VERSION 5.7 ;
  NOWIREEXTENSIONATPIN ON ;
  DIVIDERCHAR "/" ;
  BUSBITCHARS "[]" ;
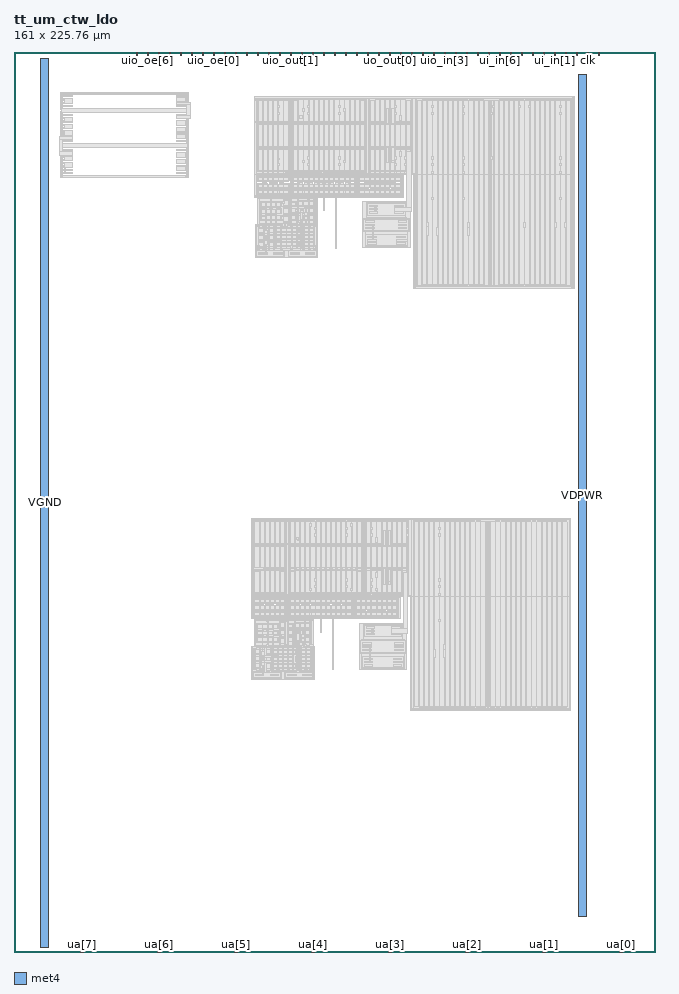
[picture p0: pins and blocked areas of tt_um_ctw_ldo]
MACRO tt_um_ctw_ldo
  CLASS BLOCK ;
  FOREIGN tt_um_ctw_ldo ;
  ORIGIN 0.000 0.000 ;
  SIZE 161.000 BY 225.760 ;
  PIN clk
    DIRECTION INPUT ;
    USE SIGNAL ;
    PORT
      LAYER met4 ;
        RECT 143.830 224.760 144.130 225.760 ;
    END
  END clk
  PIN ena
    DIRECTION INPUT ;
    USE SIGNAL ;
    PORT
      LAYER met4 ;
        RECT 146.590 224.760 146.890 225.760 ;
    END
  END ena
  PIN rst_n
    DIRECTION INPUT ;
    USE SIGNAL ;
    PORT
      LAYER met4 ;
        RECT 141.070 224.760 141.370 225.760 ;
    END
  END rst_n
  PIN ua[0]
    DIRECTION INOUT ;
    USE SIGNAL ;
    ANTENNAGATEAREA 46.000000 ;
    ANTENNADIFFAREA 186.759995 ;
    PORT
      LAYER met4 ;
        RECT 151.810 0.000 152.710 1.000 ;
    END
  END ua[0]
  PIN ua[1]
    DIRECTION INOUT ;
    USE SIGNAL ;
    ANTENNAGATEAREA 46.000000 ;
    ANTENNADIFFAREA 186.759995 ;
    PORT
      LAYER met4 ;
        RECT 132.490 0.000 133.390 1.000 ;
    END
  END ua[1]
  PIN ua[2]
    DIRECTION INOUT ;
    USE SIGNAL ;
    ANTENNAGATEAREA 886.259949 ;
    ANTENNADIFFAREA 831.391174 ;
    PORT
      LAYER met4 ;
        RECT 113.170 0.000 114.070 1.000 ;
    END
  END ua[2]
  PIN ua[3]
    DIRECTION INOUT ;
    USE SIGNAL ;
    ANTENNAGATEAREA 2.000000 ;
    PORT
      LAYER met4 ;
        RECT 93.850 0.000 94.750 1.000 ;
    END
  END ua[3]
  PIN ua[4]
    DIRECTION INOUT ;
    USE SIGNAL ;
    PORT
      LAYER met4 ;
        RECT 74.530 0.000 75.430 1.000 ;
    END
  END ua[4]
  PIN ua[5]
    DIRECTION INOUT ;
    USE SIGNAL ;
    PORT
      LAYER met4 ;
        RECT 55.210 0.000 56.110 1.000 ;
    END
  END ua[5]
  PIN ua[6]
    DIRECTION INOUT ;
    USE SIGNAL ;
    PORT
      LAYER met4 ;
        RECT 35.890 0.000 36.790 1.000 ;
    END
  END ua[6]
  PIN ua[7]
    DIRECTION INOUT ;
    USE SIGNAL ;
    PORT
      LAYER met4 ;
        RECT 16.570 0.000 17.470 1.000 ;
    END
  END ua[7]
  PIN ui_in[0]
    DIRECTION INPUT ;
    USE SIGNAL ;
    PORT
      LAYER met4 ;
        RECT 138.310 224.760 138.610 225.760 ;
    END
  END ui_in[0]
  PIN ui_in[1]
    DIRECTION INPUT ;
    USE SIGNAL ;
    PORT
      LAYER met4 ;
        RECT 135.550 224.760 135.850 225.760 ;
    END
  END ui_in[1]
  PIN ui_in[2]
    DIRECTION INPUT ;
    USE SIGNAL ;
    PORT
      LAYER met4 ;
        RECT 132.790 224.760 133.090 225.760 ;
    END
  END ui_in[2]
  PIN ui_in[3]
    DIRECTION INPUT ;
    USE SIGNAL ;
    PORT
      LAYER met4 ;
        RECT 130.030 224.760 130.330 225.760 ;
    END
  END ui_in[3]
  PIN ui_in[4]
    DIRECTION INPUT ;
    USE SIGNAL ;
    PORT
      LAYER met4 ;
        RECT 127.270 224.760 127.570 225.760 ;
    END
  END ui_in[4]
  PIN ui_in[5]
    DIRECTION INPUT ;
    USE SIGNAL ;
    PORT
      LAYER met4 ;
        RECT 124.510 224.760 124.810 225.760 ;
    END
  END ui_in[5]
  PIN ui_in[6]
    DIRECTION INPUT ;
    USE SIGNAL ;
    PORT
      LAYER met4 ;
        RECT 121.750 224.760 122.050 225.760 ;
    END
  END ui_in[6]
  PIN ui_in[7]
    DIRECTION INPUT ;
    USE SIGNAL ;
    PORT
      LAYER met4 ;
        RECT 118.990 224.760 119.290 225.760 ;
    END
  END ui_in[7]
  PIN uio_in[0]
    DIRECTION INPUT ;
    USE SIGNAL ;
    PORT
      LAYER met4 ;
        RECT 116.230 224.760 116.530 225.760 ;
    END
  END uio_in[0]
  PIN uio_in[1]
    DIRECTION INPUT ;
    USE SIGNAL ;
    PORT
      LAYER met4 ;
        RECT 113.470 224.760 113.770 225.760 ;
    END
  END uio_in[1]
  PIN uio_in[2]
    DIRECTION INPUT ;
    USE SIGNAL ;
    PORT
      LAYER met4 ;
        RECT 110.710 224.760 111.010 225.760 ;
    END
  END uio_in[2]
  PIN uio_in[3]
    DIRECTION INPUT ;
    USE SIGNAL ;
    PORT
      LAYER met4 ;
        RECT 107.950 224.760 108.250 225.760 ;
    END
  END uio_in[3]
  PIN uio_in[4]
    DIRECTION INPUT ;
    USE SIGNAL ;
    PORT
      LAYER met4 ;
        RECT 105.190 224.760 105.490 225.760 ;
    END
  END uio_in[4]
  PIN uio_in[5]
    DIRECTION INPUT ;
    USE SIGNAL ;
    PORT
      LAYER met4 ;
        RECT 102.430 224.760 102.730 225.760 ;
    END
  END uio_in[5]
  PIN uio_in[6]
    DIRECTION INPUT ;
    USE SIGNAL ;
    PORT
      LAYER met4 ;
        RECT 99.670 224.760 99.970 225.760 ;
    END
  END uio_in[6]
  PIN uio_in[7]
    DIRECTION INPUT ;
    USE SIGNAL ;
    PORT
      LAYER met4 ;
        RECT 96.910 224.760 97.210 225.760 ;
    END
  END uio_in[7]
  PIN uio_oe[0]
    DIRECTION OUTPUT ;
    USE SIGNAL ;
    PORT
      LAYER met4 ;
        RECT 49.990 224.760 50.290 225.760 ;
    END
  END uio_oe[0]
  PIN uio_oe[1]
    DIRECTION OUTPUT ;
    USE SIGNAL ;
    PORT
      LAYER met4 ;
        RECT 47.230 224.760 47.530 225.760 ;
    END
  END uio_oe[1]
  PIN uio_oe[2]
    DIRECTION OUTPUT ;
    USE SIGNAL ;
    PORT
      LAYER met4 ;
        RECT 44.470 224.760 44.770 225.760 ;
    END
  END uio_oe[2]
  PIN uio_oe[3]
    DIRECTION OUTPUT ;
    USE SIGNAL ;
    PORT
      LAYER met4 ;
        RECT 41.710 224.760 42.010 225.760 ;
    END
  END uio_oe[3]
  PIN uio_oe[4]
    DIRECTION OUTPUT ;
    USE SIGNAL ;
    PORT
      LAYER met4 ;
        RECT 38.950 224.760 39.250 225.760 ;
    END
  END uio_oe[4]
  PIN uio_oe[5]
    DIRECTION OUTPUT ;
    USE SIGNAL ;
    PORT
      LAYER met4 ;
        RECT 36.190 224.760 36.490 225.760 ;
    END
  END uio_oe[5]
  PIN uio_oe[6]
    DIRECTION OUTPUT ;
    USE SIGNAL ;
    PORT
      LAYER met4 ;
        RECT 33.430 224.760 33.730 225.760 ;
    END
  END uio_oe[6]
  PIN uio_oe[7]
    DIRECTION OUTPUT ;
    USE SIGNAL ;
    PORT
      LAYER met4 ;
        RECT 30.670 224.760 30.970 225.760 ;
    END
  END uio_oe[7]
  PIN uio_out[0]
    DIRECTION OUTPUT ;
    USE SIGNAL ;
    PORT
      LAYER met4 ;
        RECT 72.070 224.760 72.370 225.760 ;
    END
  END uio_out[0]
  PIN uio_out[1]
    DIRECTION OUTPUT ;
    USE SIGNAL ;
    ANTENNAGATEAREA 80.379997 ;
    ANTENNADIFFAREA 155.779800 ;
    PORT
      LAYER met4 ;
        RECT 69.310 224.760 69.610 225.760 ;
    END
  END uio_out[1]
  PIN uio_out[2]
    DIRECTION OUTPUT ;
    USE SIGNAL ;
    PORT
      LAYER met4 ;
        RECT 66.550 224.760 66.850 225.760 ;
    END
  END uio_out[2]
  PIN uio_out[3]
    DIRECTION OUTPUT ;
    USE SIGNAL ;
    PORT
      LAYER met4 ;
        RECT 63.790 224.760 64.090 225.760 ;
    END
  END uio_out[3]
  PIN uio_out[4]
    DIRECTION OUTPUT ;
    USE SIGNAL ;
    PORT
      LAYER met4 ;
        RECT 61.030 224.760 61.330 225.760 ;
    END
  END uio_out[4]
  PIN uio_out[5]
    DIRECTION OUTPUT ;
    USE SIGNAL ;
    PORT
      LAYER met4 ;
        RECT 58.270 224.760 58.570 225.760 ;
    END
  END uio_out[5]
  PIN uio_out[6]
    DIRECTION OUTPUT ;
    USE SIGNAL ;
    PORT
      LAYER met4 ;
        RECT 55.510 224.760 55.810 225.760 ;
    END
  END uio_out[6]
  PIN uio_out[7]
    DIRECTION OUTPUT ;
    USE SIGNAL ;
    PORT
      LAYER met4 ;
        RECT 52.750 224.760 53.050 225.760 ;
    END
  END uio_out[7]
  PIN uo_out[0]
    DIRECTION OUTPUT ;
    USE SIGNAL ;
    PORT
      LAYER met4 ;
        RECT 94.150 224.760 94.450 225.760 ;
    END
  END uo_out[0]
  PIN uo_out[1]
    DIRECTION OUTPUT ;
    USE SIGNAL ;
    PORT
      LAYER met4 ;
        RECT 91.390 224.760 91.690 225.760 ;
    END
  END uo_out[1]
  PIN uo_out[2]
    DIRECTION OUTPUT ;
    USE SIGNAL ;
    PORT
      LAYER met4 ;
        RECT 88.630 224.760 88.930 225.760 ;
    END
  END uo_out[2]
  PIN uo_out[3]
    DIRECTION OUTPUT ;
    USE SIGNAL ;
    PORT
      LAYER met4 ;
        RECT 85.870 224.760 86.170 225.760 ;
    END
  END uo_out[3]
  PIN uo_out[4]
    DIRECTION OUTPUT ;
    USE SIGNAL ;
    PORT
      LAYER met4 ;
        RECT 83.110 224.760 83.410 225.760 ;
    END
  END uo_out[4]
  PIN uo_out[5]
    DIRECTION OUTPUT ;
    USE SIGNAL ;
    PORT
      LAYER met4 ;
        RECT 80.350 224.760 80.650 225.760 ;
    END
  END uo_out[5]
  PIN uo_out[6]
    DIRECTION OUTPUT ;
    USE SIGNAL ;
    PORT
      LAYER met4 ;
        RECT 77.590 224.760 77.890 225.760 ;
    END
  END uo_out[6]
  PIN uo_out[7]
    DIRECTION OUTPUT ;
    USE SIGNAL ;
    PORT
      LAYER met4 ;
        RECT 74.830 224.760 75.130 225.760 ;
    END
  END uo_out[7]
  PIN VDPWR
    DIRECTION INOUT ;
    USE POWER ;
    PORT
      LAYER met4 ;
        RECT 141.725 8.930 143.725 220.105 ;
    END
  END VDPWR
  PIN VGND
    DIRECTION INOUT ;
    USE GROUND ;
    PORT
      LAYER met4 ;
        RECT 6.770 1.140 8.770 224.210 ;
    END
  END VGND
  OBS
      LAYER pwell ;
        RECT 11.760 215.220 43.730 215.650 ;
        RECT 11.760 211.680 12.190 215.220 ;
        RECT 43.300 211.680 43.730 215.220 ;
        RECT 11.760 211.250 43.730 211.680 ;
        RECT 11.760 210.530 43.730 210.960 ;
        RECT 11.760 202.840 12.190 210.530 ;
        RECT 43.300 202.840 43.730 210.530 ;
        RECT 11.760 202.410 43.730 202.840 ;
        RECT 11.760 201.690 43.730 202.120 ;
        RECT 11.760 194.830 12.190 201.690 ;
        RECT 43.300 194.830 43.730 201.690 ;
      LAYER nwell ;
        RECT 60.320 195.050 140.500 214.600 ;
      LAYER pwell ;
        RECT 11.760 194.400 43.730 194.830 ;
        RECT 60.380 194.620 97.740 195.050 ;
        RECT 60.380 189.800 60.810 194.620 ;
        RECT 60.880 193.420 69.170 194.180 ;
        RECT 60.880 191.830 69.170 192.590 ;
        RECT 60.880 190.240 69.170 191.000 ;
        RECT 69.260 189.800 69.690 194.620 ;
        RECT 69.750 193.420 85.780 194.180 ;
        RECT 69.750 191.830 85.780 192.590 ;
        RECT 69.750 190.240 85.780 191.000 ;
        RECT 85.870 189.800 86.300 194.620 ;
        RECT 86.350 193.420 97.220 194.180 ;
        RECT 86.350 191.830 97.220 192.590 ;
        RECT 86.350 190.240 97.220 191.000 ;
        RECT 97.310 189.800 97.740 194.620 ;
        RECT 60.380 189.370 97.740 189.800 ;
      LAYER nwell ;
        RECT 61.055 182.415 76.015 189.370 ;
      LAYER pwell ;
        RECT 60.500 174.220 76.195 182.415 ;
        RECT 87.440 176.680 99.390 188.175 ;
        RECT 87.900 176.670 98.970 176.680 ;
      LAYER nwell ;
        RECT 100.280 166.410 140.500 195.050 ;
        RECT 59.480 89.255 139.660 108.805 ;
      LAYER pwell ;
        RECT 59.540 88.825 96.900 89.255 ;
        RECT 59.540 84.005 59.970 88.825 ;
        RECT 60.040 87.625 68.330 88.385 ;
        RECT 60.040 86.035 68.330 86.795 ;
        RECT 60.040 84.445 68.330 85.205 ;
        RECT 68.420 84.005 68.850 88.825 ;
        RECT 68.910 87.625 84.940 88.385 ;
        RECT 68.910 86.035 84.940 86.795 ;
        RECT 68.910 84.445 84.940 85.205 ;
        RECT 85.030 84.005 85.460 88.825 ;
        RECT 85.510 87.625 96.380 88.385 ;
        RECT 85.510 86.035 96.380 86.795 ;
        RECT 85.510 84.445 96.380 85.205 ;
        RECT 96.470 84.005 96.900 88.825 ;
        RECT 59.540 83.575 96.900 84.005 ;
      LAYER nwell ;
        RECT 60.215 76.620 75.175 83.575 ;
      LAYER pwell ;
        RECT 59.660 68.425 75.355 76.620 ;
        RECT 86.600 70.885 98.550 82.380 ;
        RECT 87.060 70.875 98.130 70.885 ;
      LAYER nwell ;
        RECT 99.440 60.615 139.660 89.255 ;
      LAYER li1 ;
        RECT 12.530 215.520 42.965 215.525 ;
        RECT 11.890 215.350 43.600 215.520 ;
        RECT 11.890 211.550 12.060 215.350 ;
        RECT 12.540 214.520 14.700 214.870 ;
        RECT 40.790 214.520 42.950 214.870 ;
        RECT 12.540 213.690 14.700 214.040 ;
        RECT 40.790 213.690 42.950 214.040 ;
        RECT 12.540 212.860 14.700 213.210 ;
        RECT 40.790 212.860 42.950 213.210 ;
        RECT 12.540 212.030 14.700 212.380 ;
        RECT 40.790 212.030 42.950 212.380 ;
        RECT 43.430 211.550 43.600 215.350 ;
        RECT 11.890 210.660 43.600 211.550 ;
        RECT 11.890 202.710 12.060 210.660 ;
        RECT 12.540 209.830 14.700 210.180 ;
        RECT 40.790 209.830 42.950 210.180 ;
        RECT 12.540 209.000 14.700 209.350 ;
        RECT 40.790 209.000 42.950 209.350 ;
        RECT 12.540 208.170 14.700 208.520 ;
        RECT 40.790 208.170 42.950 208.520 ;
        RECT 12.540 207.340 14.700 207.690 ;
        RECT 40.790 207.340 42.950 207.690 ;
        RECT 12.540 206.510 14.700 206.860 ;
        RECT 40.790 206.510 42.950 206.860 ;
        RECT 12.540 205.680 14.700 206.030 ;
        RECT 40.790 205.680 42.950 206.030 ;
        RECT 12.540 204.850 14.700 205.200 ;
        RECT 40.790 204.850 42.950 205.200 ;
        RECT 12.540 204.020 14.700 204.370 ;
        RECT 40.790 204.020 42.950 204.370 ;
        RECT 12.540 203.190 14.700 203.540 ;
        RECT 40.790 203.190 42.950 203.540 ;
        RECT 43.430 202.710 43.600 210.660 ;
        RECT 11.890 201.820 43.600 202.710 ;
        RECT 11.890 194.700 12.060 201.820 ;
        RECT 12.540 200.990 14.700 201.340 ;
        RECT 40.790 200.990 42.950 201.340 ;
        RECT 12.540 200.160 14.700 200.510 ;
        RECT 40.790 200.160 42.950 200.510 ;
        RECT 12.540 199.330 14.700 199.680 ;
        RECT 40.790 199.330 42.950 199.680 ;
        RECT 12.540 198.500 14.700 198.850 ;
        RECT 40.790 198.500 42.950 198.850 ;
        RECT 12.540 197.670 14.700 198.020 ;
        RECT 40.790 197.670 42.950 198.020 ;
        RECT 12.540 196.840 14.700 197.190 ;
        RECT 40.790 196.840 42.950 197.190 ;
        RECT 12.540 196.010 14.700 196.360 ;
        RECT 40.790 196.010 42.950 196.360 ;
        RECT 12.540 195.180 14.700 195.530 ;
        RECT 40.790 195.180 42.950 195.530 ;
        RECT 43.430 194.700 43.600 201.820 ;
        RECT 60.500 214.250 100.190 214.420 ;
        RECT 60.500 201.550 60.670 214.250 ;
        RECT 61.380 213.740 62.220 213.910 ;
        RECT 62.670 213.740 63.510 213.910 ;
        RECT 63.880 213.740 66.170 213.910 ;
        RECT 66.460 213.740 67.460 213.910 ;
        RECT 67.750 213.740 68.750 213.910 ;
        RECT 61.070 208.485 61.240 213.525 ;
        RECT 62.360 208.485 62.530 213.525 ;
        RECT 63.650 208.485 63.820 213.525 ;
        RECT 64.940 208.270 65.110 213.740 ;
        RECT 66.230 208.485 66.400 213.525 ;
        RECT 67.520 208.485 67.690 213.525 ;
        RECT 68.810 208.485 68.980 213.525 ;
        RECT 61.380 208.100 62.220 208.270 ;
        RECT 62.670 208.100 63.510 208.270 ;
        RECT 63.880 208.100 66.170 208.270 ;
        RECT 66.460 208.100 67.460 208.270 ;
        RECT 67.750 208.100 68.750 208.270 ;
        RECT 61.300 207.560 62.300 207.730 ;
        RECT 62.695 207.560 63.485 207.730 ;
        RECT 63.985 207.560 64.775 207.730 ;
        RECT 65.275 207.560 66.065 207.730 ;
        RECT 66.565 207.560 67.355 207.730 ;
        RECT 67.750 207.560 68.750 207.730 ;
        RECT 61.070 202.305 61.240 207.345 ;
        RECT 62.360 202.305 62.530 207.345 ;
        RECT 63.650 202.305 63.820 207.345 ;
        RECT 64.940 202.305 65.110 207.345 ;
        RECT 66.230 202.305 66.400 207.345 ;
        RECT 67.520 202.305 67.690 207.345 ;
        RECT 68.810 202.305 68.980 207.345 ;
        RECT 61.300 201.920 62.300 202.090 ;
        RECT 62.695 201.920 63.485 202.090 ;
        RECT 63.985 201.920 64.775 202.090 ;
        RECT 65.275 201.920 66.065 202.090 ;
        RECT 66.565 201.920 67.355 202.090 ;
        RECT 67.750 201.920 68.750 202.090 ;
        RECT 69.380 201.550 69.550 214.250 ;
        RECT 69.950 213.910 70.120 214.250 ;
        RECT 72.530 213.910 72.700 214.250 ;
        RECT 73.820 213.910 73.990 214.250 ;
        RECT 75.110 213.910 75.280 214.250 ;
        RECT 76.400 213.910 76.570 214.250 ;
        RECT 77.690 213.910 77.860 214.250 ;
        RECT 78.980 213.910 79.150 214.250 ;
        RECT 80.270 213.910 80.440 214.250 ;
        RECT 81.560 213.910 81.730 214.250 ;
        RECT 82.850 213.910 83.020 214.250 ;
        RECT 84.140 213.910 84.310 214.250 ;
        RECT 85.430 213.910 85.600 214.250 ;
        RECT 86.720 213.910 86.890 214.250 ;
        RECT 88.010 213.910 88.180 214.250 ;
        RECT 69.950 213.740 88.180 213.910 ;
        RECT 69.950 208.270 70.120 213.740 ;
        RECT 71.240 208.485 71.410 213.525 ;
        RECT 72.530 208.270 72.700 213.740 ;
        RECT 73.820 208.270 73.990 213.740 ;
        RECT 75.110 208.270 75.280 213.740 ;
        RECT 76.400 208.270 76.570 213.740 ;
        RECT 77.690 208.270 77.860 213.740 ;
        RECT 78.980 208.270 79.150 213.740 ;
        RECT 80.270 208.270 80.440 213.740 ;
        RECT 81.560 208.270 81.730 213.740 ;
        RECT 82.850 208.270 83.020 213.740 ;
        RECT 84.140 208.270 84.310 213.740 ;
        RECT 85.430 208.270 85.600 213.740 ;
        RECT 86.720 208.270 86.890 213.740 ;
        RECT 88.010 208.270 88.180 213.740 ;
        RECT 69.950 208.100 88.180 208.270 ;
        RECT 70.180 207.560 71.180 207.730 ;
        RECT 71.575 207.560 72.365 207.730 ;
        RECT 72.865 207.560 73.655 207.730 ;
        RECT 74.155 207.560 74.945 207.730 ;
        RECT 75.445 207.560 76.235 207.730 ;
        RECT 76.735 207.560 77.525 207.730 ;
        RECT 78.025 207.560 78.815 207.730 ;
        RECT 79.315 207.560 80.105 207.730 ;
        RECT 80.605 207.560 81.395 207.730 ;
        RECT 81.895 207.560 82.685 207.730 ;
        RECT 83.185 207.560 83.975 207.730 ;
        RECT 84.475 207.560 85.265 207.730 ;
        RECT 85.765 207.560 86.555 207.730 ;
        RECT 86.950 207.560 87.950 207.730 ;
        RECT 69.950 202.305 70.120 207.345 ;
        RECT 71.240 202.305 71.410 207.345 ;
        RECT 72.530 202.305 72.700 207.345 ;
        RECT 73.820 202.305 73.990 207.345 ;
        RECT 75.110 202.305 75.280 207.345 ;
        RECT 76.400 202.305 76.570 207.345 ;
        RECT 77.690 202.305 77.860 207.345 ;
        RECT 78.980 202.305 79.150 207.345 ;
        RECT 80.270 202.305 80.440 207.345 ;
        RECT 81.560 202.305 81.730 207.345 ;
        RECT 82.850 202.305 83.020 207.345 ;
        RECT 84.140 202.305 84.310 207.345 ;
        RECT 85.430 202.305 85.600 207.345 ;
        RECT 86.720 202.305 86.890 207.345 ;
        RECT 88.010 202.305 88.180 207.345 ;
        RECT 70.180 201.920 71.180 202.090 ;
        RECT 71.575 201.920 72.365 202.090 ;
        RECT 72.865 201.920 73.655 202.090 ;
        RECT 74.155 201.920 74.945 202.090 ;
        RECT 75.445 201.920 76.235 202.090 ;
        RECT 76.735 201.920 77.525 202.090 ;
        RECT 78.025 201.920 78.815 202.090 ;
        RECT 79.315 201.920 80.105 202.090 ;
        RECT 80.605 201.920 81.395 202.090 ;
        RECT 81.895 201.920 82.685 202.090 ;
        RECT 83.185 201.920 83.975 202.090 ;
        RECT 84.475 201.920 85.265 202.090 ;
        RECT 85.765 201.920 86.555 202.090 ;
        RECT 86.950 201.920 87.950 202.090 ;
        RECT 88.560 201.550 88.750 214.250 ;
        RECT 89.130 213.910 89.300 214.250 ;
        RECT 90.420 213.910 90.590 214.250 ;
        RECT 91.710 213.910 91.880 214.250 ;
        RECT 93.000 213.910 93.170 214.250 ;
        RECT 94.290 213.910 94.460 214.250 ;
        RECT 95.580 213.910 95.750 214.250 ;
        RECT 96.870 213.910 97.040 214.250 ;
        RECT 98.160 213.910 98.330 214.250 ;
        RECT 99.450 213.910 99.620 214.250 ;
        RECT 89.130 213.740 99.620 213.910 ;
        RECT 89.130 208.270 89.300 213.740 ;
        RECT 90.420 208.270 90.590 213.740 ;
        RECT 91.710 208.270 91.880 213.740 ;
        RECT 93.000 208.270 93.170 213.740 ;
        RECT 94.290 208.270 94.460 213.740 ;
        RECT 95.580 208.270 95.750 213.740 ;
        RECT 96.870 208.270 97.040 213.740 ;
        RECT 98.160 208.270 98.330 213.740 ;
        RECT 99.450 208.270 99.620 213.740 ;
        RECT 89.130 208.100 99.620 208.270 ;
        RECT 89.360 207.560 90.360 207.730 ;
        RECT 90.755 207.560 91.545 207.730 ;
        RECT 92.045 207.560 92.835 207.730 ;
        RECT 93.335 207.560 94.125 207.730 ;
        RECT 94.625 207.560 95.415 207.730 ;
        RECT 95.915 207.560 96.705 207.730 ;
        RECT 97.205 207.560 97.995 207.730 ;
        RECT 98.390 207.560 99.390 207.730 ;
        RECT 89.130 202.305 89.300 207.345 ;
        RECT 90.420 202.305 90.590 207.345 ;
        RECT 91.710 202.305 91.880 207.345 ;
        RECT 93.000 202.305 93.170 207.345 ;
        RECT 94.290 202.305 94.460 207.345 ;
        RECT 95.580 202.305 95.750 207.345 ;
        RECT 96.870 202.305 97.040 207.345 ;
        RECT 98.160 202.305 98.330 207.345 ;
        RECT 99.450 202.305 99.620 207.345 ;
        RECT 89.360 201.920 90.360 202.090 ;
        RECT 90.755 201.920 91.545 202.090 ;
        RECT 92.045 201.920 92.835 202.090 ;
        RECT 93.335 201.920 94.125 202.090 ;
        RECT 94.625 201.920 95.415 202.090 ;
        RECT 95.915 201.920 96.705 202.090 ;
        RECT 97.205 201.920 97.995 202.090 ;
        RECT 98.390 201.920 99.390 202.090 ;
        RECT 100.020 201.550 100.190 214.250 ;
        RECT 60.500 201.380 100.190 201.550 ;
        RECT 60.500 195.910 60.670 201.380 ;
        RECT 61.070 196.125 61.240 201.165 ;
        RECT 62.360 195.910 62.530 201.380 ;
        RECT 63.650 195.910 63.820 201.380 ;
        RECT 64.940 195.910 65.110 201.380 ;
        RECT 66.230 195.910 66.400 201.380 ;
        RECT 67.520 195.910 67.690 201.380 ;
        RECT 68.810 196.125 68.980 201.165 ;
        RECT 69.380 195.910 69.550 201.380 ;
        RECT 69.950 195.910 70.120 201.380 ;
        RECT 71.240 195.910 71.410 201.380 ;
        RECT 72.530 195.910 72.700 201.380 ;
        RECT 73.820 195.910 73.990 201.380 ;
        RECT 75.110 195.910 75.280 201.380 ;
        RECT 76.400 195.910 76.570 201.380 ;
        RECT 77.690 195.910 77.860 201.380 ;
        RECT 78.980 195.910 79.150 201.380 ;
        RECT 80.270 195.910 80.440 201.380 ;
        RECT 81.560 195.910 81.730 201.380 ;
        RECT 82.850 195.910 83.020 201.380 ;
        RECT 84.140 195.910 84.310 201.380 ;
        RECT 85.430 195.910 85.600 201.380 ;
        RECT 86.720 195.910 86.890 201.380 ;
        RECT 88.010 195.910 88.180 201.380 ;
        RECT 88.560 195.910 88.750 201.380 ;
        RECT 89.130 195.910 89.300 201.380 ;
        RECT 90.420 195.910 90.590 201.380 ;
        RECT 91.710 195.910 91.880 201.380 ;
        RECT 93.000 195.910 93.170 201.380 ;
        RECT 94.290 195.910 94.460 201.380 ;
        RECT 95.580 195.910 95.750 201.380 ;
        RECT 96.870 195.910 97.040 201.380 ;
        RECT 98.160 195.910 98.330 201.380 ;
        RECT 99.450 195.910 99.620 201.380 ;
        RECT 100.020 195.910 100.190 201.380 ;
        RECT 100.460 214.250 140.320 214.420 ;
        RECT 100.460 197.840 100.630 214.250 ;
        RECT 101.260 213.740 102.260 213.910 ;
        RECT 102.550 213.740 103.550 213.910 ;
        RECT 103.840 213.740 104.840 213.910 ;
        RECT 105.130 213.740 106.130 213.910 ;
        RECT 106.420 213.740 107.420 213.910 ;
        RECT 107.710 213.740 108.710 213.910 ;
        RECT 109.000 213.740 110.000 213.910 ;
        RECT 110.290 213.740 111.290 213.910 ;
        RECT 111.580 213.740 112.580 213.910 ;
        RECT 112.870 213.740 113.870 213.910 ;
        RECT 114.160 213.740 115.160 213.910 ;
        RECT 115.450 213.740 116.450 213.910 ;
        RECT 116.740 213.740 117.740 213.910 ;
        RECT 118.030 213.740 119.030 213.910 ;
        RECT 100.455 197.200 100.630 197.840 ;
        RECT 60.500 195.740 100.190 195.910 ;
        RECT 60.500 195.400 60.670 195.740 ;
        RECT 69.380 195.400 69.550 195.740 ;
        RECT 69.950 195.400 70.120 195.740 ;
        RECT 71.240 195.400 71.410 195.740 ;
        RECT 72.530 195.400 72.700 195.740 ;
        RECT 73.820 195.400 73.990 195.740 ;
        RECT 75.110 195.400 75.280 195.740 ;
        RECT 76.400 195.400 76.570 195.740 ;
        RECT 77.690 195.400 77.860 195.740 ;
        RECT 78.980 195.400 79.150 195.740 ;
        RECT 80.270 195.400 80.440 195.740 ;
        RECT 81.560 195.400 81.730 195.740 ;
        RECT 82.850 195.400 83.020 195.740 ;
        RECT 84.140 195.400 84.310 195.740 ;
        RECT 85.430 195.400 85.600 195.740 ;
        RECT 86.720 195.400 86.890 195.740 ;
        RECT 88.010 195.400 88.180 195.740 ;
        RECT 88.560 195.400 88.750 195.740 ;
        RECT 89.130 195.400 89.300 195.740 ;
        RECT 90.420 195.400 90.590 195.740 ;
        RECT 91.710 195.400 91.880 195.740 ;
        RECT 93.000 195.400 93.170 195.740 ;
        RECT 94.290 195.400 94.460 195.740 ;
        RECT 95.580 195.400 95.750 195.740 ;
        RECT 96.870 195.400 97.040 195.740 ;
        RECT 98.160 195.400 98.330 195.740 ;
        RECT 99.450 195.400 99.620 195.740 ;
        RECT 100.020 195.400 100.190 195.740 ;
        RECT 60.500 195.230 100.190 195.400 ;
        RECT 11.890 194.530 43.600 194.700 ;
        RECT 60.510 194.750 97.610 194.920 ;
        RECT 60.510 189.670 60.680 194.750 ;
        RECT 61.070 194.410 61.240 194.750 ;
        RECT 62.360 194.410 62.530 194.750 ;
        RECT 63.650 194.410 63.820 194.750 ;
        RECT 64.940 194.410 65.110 194.750 ;
        RECT 66.230 194.410 66.400 194.750 ;
        RECT 67.520 194.410 67.690 194.750 ;
        RECT 68.810 194.410 68.980 194.750 ;
        RECT 61.070 194.240 68.980 194.410 ;
        RECT 61.070 193.360 61.240 194.240 ;
        RECT 62.360 193.360 62.530 194.240 ;
        RECT 63.650 193.360 63.820 194.240 ;
        RECT 64.940 193.360 65.110 194.240 ;
        RECT 66.230 193.360 66.400 194.240 ;
        RECT 67.520 193.360 67.690 194.240 ;
        RECT 68.810 193.360 68.980 194.240 ;
        RECT 61.070 193.190 68.980 193.360 ;
        RECT 61.405 192.650 62.195 192.820 ;
        RECT 62.695 192.650 63.485 192.820 ;
        RECT 63.985 192.650 64.775 192.820 ;
        RECT 65.275 192.650 66.065 192.820 ;
        RECT 66.565 192.650 67.355 192.820 ;
        RECT 67.855 192.650 68.645 192.820 ;
        RECT 61.070 191.940 61.240 192.480 ;
        RECT 62.360 191.940 62.530 192.480 ;
        RECT 63.650 191.940 63.820 192.480 ;
        RECT 64.940 191.940 65.110 192.480 ;
        RECT 66.230 191.940 66.400 192.480 ;
        RECT 67.520 191.940 67.690 192.480 ;
        RECT 68.810 191.940 68.980 192.480 ;
        RECT 61.405 191.600 62.195 191.770 ;
        RECT 62.695 191.600 63.485 191.770 ;
        RECT 63.985 191.600 64.775 191.770 ;
        RECT 65.275 191.600 66.065 191.770 ;
        RECT 66.565 191.600 67.355 191.770 ;
        RECT 67.855 191.600 68.645 191.770 ;
        RECT 61.070 191.060 68.980 191.230 ;
        RECT 61.070 190.180 61.240 191.060 ;
        RECT 62.360 190.180 62.530 191.060 ;
        RECT 63.650 190.180 63.820 191.060 ;
        RECT 64.940 190.180 65.110 191.060 ;
        RECT 66.230 190.180 66.400 191.060 ;
        RECT 67.520 190.180 67.690 191.060 ;
        RECT 68.810 190.180 68.980 191.060 ;
        RECT 61.070 190.010 68.980 190.180 ;
        RECT 61.070 189.670 61.240 190.010 ;
        RECT 62.360 189.670 62.530 190.010 ;
        RECT 63.650 189.670 63.820 190.010 ;
        RECT 64.940 189.670 65.110 190.010 ;
        RECT 66.230 189.670 66.400 190.010 ;
        RECT 67.520 189.670 67.690 190.010 ;
        RECT 69.390 189.670 69.560 194.750 ;
        RECT 69.940 194.410 70.110 194.750 ;
        RECT 71.230 194.410 71.400 194.750 ;
        RECT 72.520 194.410 72.690 194.750 ;
        RECT 73.810 194.410 73.980 194.750 ;
        RECT 75.100 194.410 75.270 194.750 ;
        RECT 76.390 194.410 76.560 194.750 ;
        RECT 78.970 194.410 79.140 194.750 ;
        RECT 80.260 194.410 80.430 194.750 ;
        RECT 81.550 194.410 81.720 194.750 ;
        RECT 82.840 194.410 83.010 194.750 ;
        RECT 84.130 194.410 84.300 194.750 ;
        RECT 85.420 194.410 85.590 194.750 ;
        RECT 69.940 194.240 85.590 194.410 ;
        RECT 69.940 193.360 70.110 194.240 ;
        RECT 71.230 193.360 71.400 194.240 ;
        RECT 72.520 193.360 72.690 194.240 ;
        RECT 73.810 193.360 73.980 194.240 ;
        RECT 75.100 193.360 75.270 194.240 ;
        RECT 76.390 193.360 76.560 194.240 ;
        RECT 77.680 193.360 77.850 194.240 ;
        RECT 78.970 193.360 79.140 194.240 ;
        RECT 80.260 193.360 80.430 194.240 ;
        RECT 81.550 193.360 81.720 194.240 ;
        RECT 82.840 193.360 83.010 194.240 ;
        RECT 84.130 193.360 84.300 194.240 ;
        RECT 85.420 193.360 85.590 194.240 ;
        RECT 69.940 193.190 85.590 193.360 ;
        RECT 70.275 192.650 71.065 192.820 ;
        RECT 71.565 192.650 72.355 192.820 ;
        RECT 72.855 192.650 73.645 192.820 ;
        RECT 74.145 192.650 74.935 192.820 ;
        RECT 75.435 192.650 76.225 192.820 ;
        RECT 76.725 192.650 77.515 192.820 ;
        RECT 78.015 192.650 78.805 192.820 ;
        RECT 79.305 192.650 80.095 192.820 ;
        RECT 80.595 192.650 81.385 192.820 ;
        RECT 81.885 192.650 82.675 192.820 ;
        RECT 83.175 192.650 83.965 192.820 ;
        RECT 84.465 192.650 85.255 192.820 ;
        RECT 69.940 191.940 70.110 192.480 ;
        RECT 71.230 191.940 71.400 192.480 ;
        RECT 72.520 191.940 72.690 192.480 ;
        RECT 73.810 191.940 73.980 192.480 ;
        RECT 75.100 191.940 75.270 192.480 ;
        RECT 76.390 191.940 76.560 192.480 ;
        RECT 77.680 191.940 77.850 192.480 ;
        RECT 78.970 191.940 79.140 192.480 ;
        RECT 80.260 191.940 80.430 192.480 ;
        RECT 81.550 191.940 81.720 192.480 ;
        RECT 82.840 191.940 83.010 192.480 ;
        RECT 84.130 191.940 84.300 192.480 ;
        RECT 85.420 191.940 85.590 192.480 ;
        RECT 70.275 191.600 71.065 191.770 ;
        RECT 71.565 191.600 72.355 191.770 ;
        RECT 72.855 191.600 73.645 191.770 ;
        RECT 74.145 191.600 74.935 191.770 ;
        RECT 75.435 191.600 76.225 191.770 ;
        RECT 76.725 191.600 77.515 191.770 ;
        RECT 78.015 191.600 78.805 191.770 ;
        RECT 79.305 191.600 80.095 191.770 ;
        RECT 80.595 191.600 81.385 191.770 ;
        RECT 81.885 191.600 82.675 191.770 ;
        RECT 83.175 191.600 83.965 191.770 ;
        RECT 84.465 191.600 85.255 191.770 ;
        RECT 69.940 191.060 85.590 191.230 ;
        RECT 69.940 190.180 70.110 191.060 ;
        RECT 71.230 190.180 71.400 191.060 ;
        RECT 72.520 190.180 72.690 191.060 ;
        RECT 73.810 190.180 73.980 191.060 ;
        RECT 75.100 190.180 75.270 191.060 ;
        RECT 76.390 190.180 76.560 191.060 ;
        RECT 77.680 190.180 77.850 191.060 ;
        RECT 78.970 190.180 79.140 191.060 ;
        RECT 80.260 190.180 80.430 191.060 ;
        RECT 81.550 190.180 81.720 191.060 ;
        RECT 82.840 190.180 83.010 191.060 ;
        RECT 84.130 190.180 84.300 191.060 ;
        RECT 85.420 190.180 85.590 191.060 ;
        RECT 69.940 190.010 85.590 190.180 ;
        RECT 69.940 189.670 70.110 190.010 ;
        RECT 71.230 189.670 71.400 190.010 ;
        RECT 72.520 189.670 72.690 190.010 ;
        RECT 73.810 189.670 73.980 190.010 ;
        RECT 75.100 189.670 75.270 190.010 ;
        RECT 76.390 189.670 76.560 190.010 ;
        RECT 77.680 189.670 77.850 190.010 ;
        RECT 78.970 189.670 79.140 190.010 ;
        RECT 80.260 189.670 80.430 190.010 ;
        RECT 81.550 189.670 81.720 190.010 ;
        RECT 82.840 189.670 83.010 190.010 ;
        RECT 84.130 189.670 84.300 190.010 ;
        RECT 85.420 189.670 85.590 190.010 ;
        RECT 86.000 189.670 86.170 194.750 ;
        RECT 86.540 194.410 86.710 194.750 ;
        RECT 87.830 194.410 88.000 194.750 ;
        RECT 89.120 194.410 89.290 194.750 ;
        RECT 90.410 194.410 90.580 194.750 ;
        RECT 91.700 194.410 91.870 194.750 ;
        RECT 92.990 194.410 93.160 194.750 ;
        RECT 94.280 194.410 94.450 194.750 ;
        RECT 95.570 194.410 95.740 194.750 ;
        RECT 96.860 194.410 97.030 194.750 ;
        RECT 86.540 194.240 97.030 194.410 ;
        RECT 86.540 193.360 86.710 194.240 ;
        RECT 87.830 193.360 88.000 194.240 ;
        RECT 89.120 193.360 89.290 194.240 ;
        RECT 90.410 193.360 90.580 194.240 ;
        RECT 91.700 193.360 91.870 194.240 ;
        RECT 92.990 193.360 93.160 194.240 ;
        RECT 94.280 193.360 94.450 194.240 ;
        RECT 95.570 193.360 95.740 194.240 ;
        RECT 96.860 193.360 97.030 194.240 ;
        RECT 86.540 193.190 97.030 193.360 ;
        RECT 86.875 192.650 87.665 192.820 ;
        RECT 88.165 192.650 88.955 192.820 ;
        RECT 89.455 192.650 90.245 192.820 ;
        RECT 90.745 192.650 91.535 192.820 ;
        RECT 92.035 192.650 92.825 192.820 ;
        RECT 93.325 192.650 94.115 192.820 ;
        RECT 94.615 192.650 95.405 192.820 ;
        RECT 95.905 192.650 96.695 192.820 ;
        RECT 86.540 191.940 86.710 192.480 ;
        RECT 87.830 191.940 88.000 192.480 ;
        RECT 89.120 191.940 89.290 192.480 ;
        RECT 90.410 191.940 90.580 192.480 ;
        RECT 91.700 191.940 91.870 192.480 ;
        RECT 92.990 191.940 93.160 192.480 ;
        RECT 94.280 191.940 94.450 192.480 ;
        RECT 95.570 191.940 95.740 192.480 ;
        RECT 96.860 191.940 97.030 192.480 ;
        RECT 86.875 191.600 87.665 191.770 ;
        RECT 88.165 191.600 88.955 191.770 ;
        RECT 89.455 191.600 90.245 191.770 ;
        RECT 90.745 191.600 91.535 191.770 ;
        RECT 92.035 191.600 92.825 191.770 ;
        RECT 93.325 191.600 94.115 191.770 ;
        RECT 94.615 191.600 95.405 191.770 ;
        RECT 95.905 191.600 96.695 191.770 ;
        RECT 86.540 191.060 97.030 191.230 ;
        RECT 86.540 190.180 86.710 191.060 ;
        RECT 87.830 190.180 88.000 191.060 ;
        RECT 89.120 190.180 89.290 191.060 ;
        RECT 90.410 190.180 90.580 191.060 ;
        RECT 91.700 190.180 91.870 191.060 ;
        RECT 92.990 190.180 93.160 191.060 ;
        RECT 94.280 190.180 94.450 191.060 ;
        RECT 95.570 190.180 95.740 191.060 ;
        RECT 96.860 190.180 97.030 191.060 ;
        RECT 86.540 190.010 97.030 190.180 ;
        RECT 86.540 189.670 86.710 190.010 ;
        RECT 87.830 189.670 88.000 190.010 ;
        RECT 89.120 189.670 89.290 190.010 ;
        RECT 90.410 189.670 90.580 190.010 ;
        RECT 91.700 189.670 91.870 190.010 ;
        RECT 92.990 189.670 93.160 190.010 ;
        RECT 94.280 189.670 94.450 190.010 ;
        RECT 95.570 189.670 95.740 190.010 ;
        RECT 96.860 189.670 97.030 190.010 ;
        RECT 97.440 189.670 97.610 194.750 ;
        RECT 60.510 189.500 97.610 189.670 ;
        RECT 61.235 189.020 75.835 189.190 ;
        RECT 61.235 182.765 61.405 189.020 ;
        RECT 67.525 188.505 68.985 188.675 ;
        RECT 67.525 188.160 67.695 188.505 ;
        RECT 62.115 187.990 67.695 188.160 ;
        RECT 61.805 187.235 61.975 187.775 ;
        RECT 63.095 187.235 63.265 187.775 ;
        RECT 64.385 187.020 64.555 187.990 ;
        RECT 65.675 187.020 65.845 187.990 ;
        RECT 66.965 187.055 67.135 187.990 ;
        RECT 67.525 187.235 67.695 187.990 ;
        RECT 68.815 187.235 68.985 188.505 ;
        RECT 69.685 188.085 70.525 188.255 ;
        RECT 71.535 188.210 72.375 188.380 ;
        RECT 72.825 188.210 73.665 188.380 ;
        RECT 74.115 188.210 74.955 188.380 ;
        RECT 69.375 187.330 69.545 187.870 ;
        RECT 70.665 187.330 70.835 187.870 ;
        RECT 71.225 187.365 71.395 187.995 ;
        RECT 72.515 187.365 72.685 187.995 ;
        RECT 73.805 187.365 73.975 187.995 ;
        RECT 75.095 187.365 75.265 187.995 ;
        RECT 67.525 187.065 68.985 187.235 ;
        RECT 67.525 187.055 67.695 187.065 ;
        RECT 66.625 187.020 67.695 187.055 ;
        RECT 62.115 186.885 67.695 187.020 ;
        RECT 69.685 186.945 70.525 187.115 ;
        RECT 71.535 186.980 72.375 187.150 ;
        RECT 72.825 186.980 73.665 187.150 ;
        RECT 74.115 186.980 74.955 187.150 ;
        RECT 62.115 186.850 66.795 186.885 ;
        RECT 67.865 186.525 68.645 186.695 ;
        RECT 71.225 186.575 72.685 186.610 ;
        RECT 62.115 186.310 62.955 186.480 ;
        RECT 63.435 186.310 64.215 186.480 ;
        RECT 64.725 186.310 65.505 186.480 ;
        RECT 65.675 186.310 67.135 186.480 ;
        RECT 69.715 186.440 72.685 186.575 ;
        RECT 72.855 186.440 73.635 186.610 ;
        RECT 74.115 186.440 74.955 186.610 ;
        RECT 69.715 186.405 71.395 186.440 ;
        RECT 61.805 185.555 61.975 186.095 ;
        RECT 63.095 185.555 63.265 186.095 ;
        RECT 64.385 185.555 64.555 186.095 ;
        RECT 65.675 185.340 65.845 186.310 ;
        RECT 66.965 185.340 67.135 186.310 ;
        RECT 67.525 185.470 67.695 186.310 ;
        RECT 68.815 185.470 68.985 186.310 ;
        RECT 69.375 185.650 69.545 186.190 ;
        RECT 70.665 185.650 70.835 186.190 ;
        RECT 71.225 185.435 71.395 186.405 ;
        RECT 62.115 185.170 62.955 185.340 ;
        RECT 63.435 185.170 64.215 185.340 ;
        RECT 64.725 185.170 65.505 185.340 ;
        RECT 65.675 185.170 67.135 185.340 ;
        RECT 69.715 185.380 71.395 185.435 ;
        RECT 72.515 185.380 72.685 186.440 ;
        RECT 73.805 185.595 73.975 186.225 ;
        RECT 75.095 185.595 75.265 186.225 ;
        RECT 69.715 185.265 72.685 185.380 ;
        RECT 67.865 185.085 68.645 185.255 ;
        RECT 71.225 185.210 72.685 185.265 ;
        RECT 72.855 185.210 73.635 185.380 ;
        RECT 74.115 185.210 74.955 185.380 ;
        RECT 69.375 184.840 71.400 184.895 ;
        RECT 62.115 184.715 67.135 184.800 ;
        RECT 69.375 184.725 74.955 184.840 ;
        RECT 62.115 184.630 68.985 184.715 ;
        RECT 61.805 183.875 61.975 184.415 ;
        RECT 63.095 183.875 63.265 184.415 ;
        RECT 64.385 183.660 64.555 184.630 ;
        RECT 65.675 183.660 65.845 184.630 ;
        RECT 66.965 184.545 68.985 184.630 ;
        RECT 66.965 183.660 67.135 184.545 ;
        RECT 67.525 183.660 67.695 184.545 ;
        RECT 62.115 183.490 67.695 183.660 ;
        RECT 67.525 183.275 67.695 183.490 ;
        RECT 68.815 183.275 68.985 184.545 ;
        RECT 69.375 183.755 69.545 184.725 ;
        RECT 70.665 183.755 70.835 184.725 ;
        RECT 71.225 184.670 74.955 184.725 ;
        RECT 71.225 183.755 71.395 184.670 ;
        RECT 69.375 183.610 71.395 183.755 ;
        RECT 72.515 183.610 72.685 184.670 ;
        RECT 73.805 183.825 73.975 184.455 ;
        RECT 75.095 183.825 75.265 184.455 ;
        RECT 69.375 183.585 74.955 183.610 ;
        RECT 71.225 183.440 74.955 183.585 ;
        RECT 67.525 183.105 68.985 183.275 ;
        RECT 71.275 182.765 71.470 182.770 ;
        RECT 75.665 182.765 75.835 189.020 ;
        RECT 88.490 187.810 98.330 187.980 ;
        RECT 88.490 184.840 88.660 187.810 ;
        RECT 89.140 186.980 91.300 187.330 ;
        RECT 95.520 186.980 97.680 187.330 ;
        RECT 89.140 186.150 91.300 186.500 ;
        RECT 95.520 186.150 97.680 186.500 ;
        RECT 89.140 185.320 91.300 185.670 ;
        RECT 95.520 185.320 97.680 185.670 ;
        RECT 98.160 184.840 98.330 187.810 ;
        RECT 88.490 184.040 98.330 184.840 ;
        RECT 61.235 182.595 75.835 182.765 ;
        RECT 87.620 183.870 99.210 184.040 ;
        RECT 60.680 182.115 76.015 182.285 ;
        RECT 60.680 176.515 60.850 182.115 ;
        RECT 61.595 181.600 65.295 181.770 ;
        RECT 61.255 180.720 61.425 181.430 ;
        RECT 62.545 180.720 62.715 181.430 ;
        RECT 63.835 180.550 64.005 181.600 ;
        RECT 65.125 180.550 65.295 181.600 ;
        RECT 61.595 180.380 65.295 180.550 ;
        RECT 65.685 181.520 73.815 181.690 ;
        RECT 74.325 181.520 75.105 181.690 ;
        RECT 65.685 180.640 65.855 181.520 ;
        RECT 66.975 180.640 67.145 181.520 ;
        RECT 68.265 180.640 68.435 181.520 ;
        RECT 69.555 180.640 69.725 181.520 ;
        RECT 70.845 180.640 71.015 181.520 ;
        RECT 71.405 180.640 71.575 181.520 ;
        RECT 72.695 180.640 72.865 181.520 ;
        RECT 73.985 180.810 74.155 181.350 ;
        RECT 75.275 180.810 75.445 181.350 ;
        RECT 65.685 180.470 73.815 180.640 ;
        RECT 74.325 180.470 75.105 180.640 ;
        RECT 61.595 179.840 62.375 180.010 ;
        RECT 62.885 179.840 63.665 180.010 ;
        RECT 64.145 179.840 64.985 180.010 ;
        RECT 66.025 179.760 66.805 179.930 ;
        RECT 67.315 179.760 68.435 179.930 ;
        RECT 68.605 179.760 69.385 179.930 ;
        RECT 69.895 179.760 70.675 179.930 ;
        RECT 71.405 179.760 72.865 179.930 ;
        RECT 73.035 179.760 73.815 179.930 ;
        RECT 74.325 179.760 75.105 179.930 ;
        RECT 61.255 178.960 61.425 179.670 ;
        RECT 62.545 178.960 62.715 179.670 ;
        RECT 63.835 178.960 64.005 179.670 ;
        RECT 65.125 178.960 65.295 179.670 ;
        RECT 65.685 179.050 65.855 179.590 ;
        RECT 66.975 179.050 67.145 179.590 ;
        RECT 68.265 178.880 68.435 179.760 ;
        RECT 69.555 179.050 69.725 179.590 ;
        RECT 70.845 179.050 71.015 179.590 ;
        RECT 71.405 178.880 71.575 179.760 ;
        RECT 72.695 178.880 72.865 179.760 ;
        RECT 73.985 179.050 74.155 179.590 ;
        RECT 75.275 179.050 75.445 179.590 ;
        RECT 61.595 178.620 62.375 178.790 ;
        RECT 62.885 178.620 63.665 178.790 ;
        RECT 64.145 178.620 64.985 178.790 ;
        RECT 66.025 178.710 66.805 178.880 ;
        RECT 67.315 178.710 68.435 178.880 ;
        RECT 68.605 178.710 69.385 178.880 ;
        RECT 69.895 178.710 70.675 178.880 ;
        RECT 71.405 178.710 72.865 178.880 ;
        RECT 73.035 178.710 73.815 178.880 ;
        RECT 74.325 178.710 75.105 178.880 ;
        RECT 61.595 178.080 65.295 178.250 ;
        RECT 61.255 177.200 61.425 177.910 ;
        RECT 62.545 177.200 62.715 177.910 ;
        RECT 63.835 177.030 64.005 178.080 ;
        RECT 65.125 177.030 65.295 178.080 ;
        RECT 61.595 176.860 65.295 177.030 ;
        RECT 65.685 178.000 73.815 178.170 ;
        RECT 74.295 178.000 75.135 178.170 ;
        RECT 65.685 177.120 65.855 178.000 ;
        RECT 66.975 177.120 67.145 178.000 ;
        RECT 68.265 177.120 68.435 178.000 ;
        RECT 69.555 177.120 69.725 178.000 ;
        RECT 70.845 177.120 71.015 178.000 ;
        RECT 71.405 177.120 71.575 178.000 ;
        RECT 72.695 177.120 72.865 178.000 ;
        RECT 73.985 177.290 74.155 177.830 ;
        RECT 75.275 177.290 75.445 177.830 ;
        RECT 65.685 176.950 73.815 177.120 ;
        RECT 74.295 176.950 75.135 177.120 ;
        RECT 75.845 176.515 76.015 182.115 ;
        RECT 87.620 180.900 87.790 183.870 ;
        RECT 88.270 183.040 90.430 183.390 ;
        RECT 96.400 183.040 98.560 183.390 ;
        RECT 88.270 182.210 90.430 182.560 ;
        RECT 96.400 182.210 98.560 182.560 ;
        RECT 88.270 181.380 90.430 181.730 ;
        RECT 96.400 181.380 98.560 181.730 ;
        RECT 99.040 180.900 99.210 183.870 ;
        RECT 87.620 180.730 99.210 180.900 ;
        RECT 88.080 179.990 98.790 180.730 ;
        RECT 88.080 177.020 88.250 179.990 ;
        RECT 88.730 179.160 90.890 179.510 ;
        RECT 95.980 179.160 98.140 179.510 ;
        RECT 98.620 178.690 98.790 179.990 ;
        RECT 97.990 178.680 98.790 178.690 ;
        RECT 88.730 178.330 90.890 178.680 ;
        RECT 95.980 178.340 98.790 178.680 ;
        RECT 95.980 178.330 98.140 178.340 ;
        RECT 88.730 177.500 90.890 177.850 ;
        RECT 95.980 177.500 98.140 177.850 ;
        RECT 88.560 177.020 98.310 177.030 ;
        RECT 98.620 177.020 98.790 178.340 ;
        RECT 88.080 176.850 98.790 177.020 ;
        RECT 60.680 176.045 76.015 176.515 ;
        RECT 60.680 175.880 67.890 176.045 ;
        RECT 60.680 174.570 60.850 175.880 ;
        RECT 61.330 175.050 63.490 175.400 ;
        RECT 65.080 175.050 67.240 175.400 ;
        RECT 67.720 174.570 67.890 175.880 ;
        RECT 60.680 174.400 67.890 174.570 ;
        RECT 68.805 175.880 76.015 176.045 ;
        RECT 68.805 174.570 68.975 175.880 ;
        RECT 69.455 175.050 71.615 175.400 ;
        RECT 73.205 175.050 75.365 175.400 ;
        RECT 75.845 174.570 76.015 175.880 ;
        RECT 68.805 174.400 76.015 174.570 ;
        RECT 100.460 166.760 100.630 197.200 ;
        RECT 101.030 167.485 101.200 213.525 ;
        RECT 102.320 167.485 102.490 213.525 ;
        RECT 103.610 167.485 103.780 213.525 ;
        RECT 104.900 167.485 105.070 213.525 ;
        RECT 106.190 167.485 106.360 213.525 ;
        RECT 107.480 167.485 107.650 213.525 ;
        RECT 108.770 167.485 108.940 213.525 ;
        RECT 110.060 167.485 110.230 213.525 ;
        RECT 111.350 167.485 111.520 213.525 ;
        RECT 112.640 167.485 112.810 213.525 ;
        RECT 113.930 167.485 114.100 213.525 ;
        RECT 115.220 167.485 115.390 213.525 ;
        RECT 116.510 167.485 116.680 213.525 ;
        RECT 117.800 167.485 117.970 213.525 ;
        RECT 119.090 167.485 119.260 213.525 ;
        RECT 101.260 167.100 102.260 167.270 ;
        RECT 102.550 167.100 103.550 167.270 ;
        RECT 103.840 167.100 104.840 167.270 ;
        RECT 105.130 167.100 106.130 167.270 ;
        RECT 106.420 167.100 107.420 167.270 ;
        RECT 107.710 167.100 108.710 167.270 ;
        RECT 109.000 167.100 110.000 167.270 ;
        RECT 110.290 167.100 111.290 167.270 ;
        RECT 111.580 167.100 112.580 167.270 ;
        RECT 112.870 167.100 113.870 167.270 ;
        RECT 114.160 167.100 115.160 167.270 ;
        RECT 115.450 167.100 116.450 167.270 ;
        RECT 116.740 167.100 117.740 167.270 ;
        RECT 118.030 167.100 119.030 167.270 ;
        RECT 119.660 166.760 119.830 214.250 ;
        RECT 120.460 213.740 121.460 213.910 ;
        RECT 121.750 213.740 122.750 213.910 ;
        RECT 123.040 213.740 124.040 213.910 ;
        RECT 124.330 213.740 125.330 213.910 ;
        RECT 125.620 213.740 126.620 213.910 ;
        RECT 126.910 213.740 127.910 213.910 ;
        RECT 128.200 213.740 129.200 213.910 ;
        RECT 129.490 213.740 130.490 213.910 ;
        RECT 130.780 213.740 131.780 213.910 ;
        RECT 132.070 213.740 133.070 213.910 ;
        RECT 133.360 213.740 134.360 213.910 ;
        RECT 134.650 213.740 135.650 213.910 ;
        RECT 135.940 213.740 136.940 213.910 ;
        RECT 137.230 213.740 138.230 213.910 ;
        RECT 138.520 213.740 139.520 213.910 ;
        RECT 120.230 167.485 120.400 213.525 ;
        RECT 121.520 167.485 121.690 213.525 ;
        RECT 122.810 167.485 122.980 213.525 ;
        RECT 124.100 167.485 124.270 213.525 ;
        RECT 125.390 167.485 125.560 213.525 ;
        RECT 126.680 167.485 126.850 213.525 ;
        RECT 127.970 167.485 128.140 213.525 ;
        RECT 129.260 167.485 129.430 213.525 ;
        RECT 130.550 167.485 130.720 213.525 ;
        RECT 131.840 167.485 132.010 213.525 ;
        RECT 133.130 167.485 133.300 213.525 ;
        RECT 134.420 167.485 134.590 213.525 ;
        RECT 135.710 167.485 135.880 213.525 ;
        RECT 137.000 167.485 137.170 213.525 ;
        RECT 138.290 167.485 138.460 213.525 ;
        RECT 139.580 167.485 139.750 213.525 ;
        RECT 120.460 167.100 121.460 167.270 ;
        RECT 121.750 167.100 122.750 167.270 ;
        RECT 123.040 167.100 124.040 167.270 ;
        RECT 124.330 167.100 125.330 167.270 ;
        RECT 125.620 167.100 126.620 167.270 ;
        RECT 126.910 167.100 127.910 167.270 ;
        RECT 128.200 167.100 129.200 167.270 ;
        RECT 129.490 167.100 130.490 167.270 ;
        RECT 130.780 167.100 131.780 167.270 ;
        RECT 132.070 167.100 133.070 167.270 ;
        RECT 133.360 167.100 134.360 167.270 ;
        RECT 134.650 167.100 135.650 167.270 ;
        RECT 135.940 167.100 136.940 167.270 ;
        RECT 137.230 167.100 138.230 167.270 ;
        RECT 138.520 167.100 139.520 167.270 ;
        RECT 140.150 166.760 140.320 214.250 ;
        RECT 100.460 166.590 140.320 166.760 ;
        RECT 59.660 108.455 99.350 108.625 ;
        RECT 59.660 95.755 59.830 108.455 ;
        RECT 60.540 107.945 61.380 108.115 ;
        RECT 61.830 107.945 62.670 108.115 ;
        RECT 63.040 107.945 65.330 108.115 ;
        RECT 65.620 107.945 66.620 108.115 ;
        RECT 66.910 107.945 67.910 108.115 ;
        RECT 60.230 102.690 60.400 107.730 ;
        RECT 61.520 102.690 61.690 107.730 ;
        RECT 62.810 102.690 62.980 107.730 ;
        RECT 64.100 102.475 64.270 107.945 ;
        RECT 65.390 102.690 65.560 107.730 ;
        RECT 66.680 102.690 66.850 107.730 ;
        RECT 67.970 102.690 68.140 107.730 ;
        RECT 60.540 102.305 61.380 102.475 ;
        RECT 61.830 102.305 62.670 102.475 ;
        RECT 63.040 102.305 65.330 102.475 ;
        RECT 65.620 102.305 66.620 102.475 ;
        RECT 66.910 102.305 67.910 102.475 ;
        RECT 60.460 101.765 61.460 101.935 ;
        RECT 61.855 101.765 62.645 101.935 ;
        RECT 63.145 101.765 63.935 101.935 ;
        RECT 64.435 101.765 65.225 101.935 ;
        RECT 65.725 101.765 66.515 101.935 ;
        RECT 66.910 101.765 67.910 101.935 ;
        RECT 60.230 96.510 60.400 101.550 ;
        RECT 61.520 96.510 61.690 101.550 ;
        RECT 62.810 96.510 62.980 101.550 ;
        RECT 64.100 96.510 64.270 101.550 ;
        RECT 65.390 96.510 65.560 101.550 ;
        RECT 66.680 96.510 66.850 101.550 ;
        RECT 67.970 96.510 68.140 101.550 ;
        RECT 60.460 96.125 61.460 96.295 ;
        RECT 61.855 96.125 62.645 96.295 ;
        RECT 63.145 96.125 63.935 96.295 ;
        RECT 64.435 96.125 65.225 96.295 ;
        RECT 65.725 96.125 66.515 96.295 ;
        RECT 66.910 96.125 67.910 96.295 ;
        RECT 68.540 95.755 68.710 108.455 ;
        RECT 69.110 108.115 69.280 108.455 ;
        RECT 71.690 108.115 71.860 108.455 ;
        RECT 72.980 108.115 73.150 108.455 ;
        RECT 74.270 108.115 74.440 108.455 ;
        RECT 75.560 108.115 75.730 108.455 ;
        RECT 76.850 108.115 77.020 108.455 ;
        RECT 78.140 108.115 78.310 108.455 ;
        RECT 79.430 108.115 79.600 108.455 ;
        RECT 80.720 108.115 80.890 108.455 ;
        RECT 82.010 108.115 82.180 108.455 ;
        RECT 83.300 108.115 83.470 108.455 ;
        RECT 84.590 108.115 84.760 108.455 ;
        RECT 85.880 108.115 86.050 108.455 ;
        RECT 87.170 108.115 87.340 108.455 ;
        RECT 69.110 107.945 87.340 108.115 ;
        RECT 69.110 102.475 69.280 107.945 ;
        RECT 70.400 102.690 70.570 107.730 ;
        RECT 71.690 102.475 71.860 107.945 ;
        RECT 72.980 102.475 73.150 107.945 ;
        RECT 74.270 102.475 74.440 107.945 ;
        RECT 75.560 102.475 75.730 107.945 ;
        RECT 76.850 102.475 77.020 107.945 ;
        RECT 78.140 102.475 78.310 107.945 ;
        RECT 79.430 102.475 79.600 107.945 ;
        RECT 80.720 102.475 80.890 107.945 ;
        RECT 82.010 102.475 82.180 107.945 ;
        RECT 83.300 102.475 83.470 107.945 ;
        RECT 84.590 102.475 84.760 107.945 ;
        RECT 85.880 102.475 86.050 107.945 ;
        RECT 87.170 102.475 87.340 107.945 ;
        RECT 69.110 102.305 87.340 102.475 ;
        RECT 69.340 101.765 70.340 101.935 ;
        RECT 70.735 101.765 71.525 101.935 ;
        RECT 72.025 101.765 72.815 101.935 ;
        RECT 73.315 101.765 74.105 101.935 ;
        RECT 74.605 101.765 75.395 101.935 ;
        RECT 75.895 101.765 76.685 101.935 ;
        RECT 77.185 101.765 77.975 101.935 ;
        RECT 78.475 101.765 79.265 101.935 ;
        RECT 79.765 101.765 80.555 101.935 ;
        RECT 81.055 101.765 81.845 101.935 ;
        RECT 82.345 101.765 83.135 101.935 ;
        RECT 83.635 101.765 84.425 101.935 ;
        RECT 84.925 101.765 85.715 101.935 ;
        RECT 86.110 101.765 87.110 101.935 ;
        RECT 69.110 96.510 69.280 101.550 ;
        RECT 70.400 96.510 70.570 101.550 ;
        RECT 71.690 96.510 71.860 101.550 ;
        RECT 72.980 96.510 73.150 101.550 ;
        RECT 74.270 96.510 74.440 101.550 ;
        RECT 75.560 96.510 75.730 101.550 ;
        RECT 76.850 96.510 77.020 101.550 ;
        RECT 78.140 96.510 78.310 101.550 ;
        RECT 79.430 96.510 79.600 101.550 ;
        RECT 80.720 96.510 80.890 101.550 ;
        RECT 82.010 96.510 82.180 101.550 ;
        RECT 83.300 96.510 83.470 101.550 ;
        RECT 84.590 96.510 84.760 101.550 ;
        RECT 85.880 96.510 86.050 101.550 ;
        RECT 87.170 96.510 87.340 101.550 ;
        RECT 69.340 96.125 70.340 96.295 ;
        RECT 70.735 96.125 71.525 96.295 ;
        RECT 72.025 96.125 72.815 96.295 ;
        RECT 73.315 96.125 74.105 96.295 ;
        RECT 74.605 96.125 75.395 96.295 ;
        RECT 75.895 96.125 76.685 96.295 ;
        RECT 77.185 96.125 77.975 96.295 ;
        RECT 78.475 96.125 79.265 96.295 ;
        RECT 79.765 96.125 80.555 96.295 ;
        RECT 81.055 96.125 81.845 96.295 ;
        RECT 82.345 96.125 83.135 96.295 ;
        RECT 83.635 96.125 84.425 96.295 ;
        RECT 84.925 96.125 85.715 96.295 ;
        RECT 86.110 96.125 87.110 96.295 ;
        RECT 87.720 95.755 87.910 108.455 ;
        RECT 88.290 108.115 88.460 108.455 ;
        RECT 89.580 108.115 89.750 108.455 ;
        RECT 90.870 108.115 91.040 108.455 ;
        RECT 92.160 108.115 92.330 108.455 ;
        RECT 93.450 108.115 93.620 108.455 ;
        RECT 94.740 108.115 94.910 108.455 ;
        RECT 96.030 108.115 96.200 108.455 ;
        RECT 97.320 108.115 97.490 108.455 ;
        RECT 98.610 108.115 98.780 108.455 ;
        RECT 88.290 107.945 98.780 108.115 ;
        RECT 88.290 102.475 88.460 107.945 ;
        RECT 89.580 102.475 89.750 107.945 ;
        RECT 90.870 102.475 91.040 107.945 ;
        RECT 92.160 102.475 92.330 107.945 ;
        RECT 93.450 102.475 93.620 107.945 ;
        RECT 94.740 102.475 94.910 107.945 ;
        RECT 96.030 102.475 96.200 107.945 ;
        RECT 97.320 102.475 97.490 107.945 ;
        RECT 98.610 102.475 98.780 107.945 ;
        RECT 88.290 102.305 98.780 102.475 ;
        RECT 88.520 101.765 89.520 101.935 ;
        RECT 89.915 101.765 90.705 101.935 ;
        RECT 91.205 101.765 91.995 101.935 ;
        RECT 92.495 101.765 93.285 101.935 ;
        RECT 93.785 101.765 94.575 101.935 ;
        RECT 95.075 101.765 95.865 101.935 ;
        RECT 96.365 101.765 97.155 101.935 ;
        RECT 97.550 101.765 98.550 101.935 ;
        RECT 88.290 96.510 88.460 101.550 ;
        RECT 89.580 96.510 89.750 101.550 ;
        RECT 90.870 96.510 91.040 101.550 ;
        RECT 92.160 96.510 92.330 101.550 ;
        RECT 93.450 96.510 93.620 101.550 ;
        RECT 94.740 96.510 94.910 101.550 ;
        RECT 96.030 96.510 96.200 101.550 ;
        RECT 97.320 96.510 97.490 101.550 ;
        RECT 98.610 96.510 98.780 101.550 ;
        RECT 88.520 96.125 89.520 96.295 ;
        RECT 89.915 96.125 90.705 96.295 ;
        RECT 91.205 96.125 91.995 96.295 ;
        RECT 92.495 96.125 93.285 96.295 ;
        RECT 93.785 96.125 94.575 96.295 ;
        RECT 95.075 96.125 95.865 96.295 ;
        RECT 96.365 96.125 97.155 96.295 ;
        RECT 97.550 96.125 98.550 96.295 ;
        RECT 99.180 95.755 99.350 108.455 ;
        RECT 59.660 95.585 99.350 95.755 ;
        RECT 59.660 90.115 59.830 95.585 ;
        RECT 60.230 90.330 60.400 95.370 ;
        RECT 61.520 90.115 61.690 95.585 ;
        RECT 62.810 90.115 62.980 95.585 ;
        RECT 64.100 90.115 64.270 95.585 ;
        RECT 65.390 90.115 65.560 95.585 ;
        RECT 66.680 90.115 66.850 95.585 ;
        RECT 67.970 90.330 68.140 95.370 ;
        RECT 68.540 90.115 68.710 95.585 ;
        RECT 69.110 90.115 69.280 95.585 ;
        RECT 70.400 90.115 70.570 95.585 ;
        RECT 71.690 90.115 71.860 95.585 ;
        RECT 72.980 90.115 73.150 95.585 ;
        RECT 74.270 90.115 74.440 95.585 ;
        RECT 75.560 90.115 75.730 95.585 ;
        RECT 76.850 90.115 77.020 95.585 ;
        RECT 78.140 90.115 78.310 95.585 ;
        RECT 79.430 90.115 79.600 95.585 ;
        RECT 80.720 90.115 80.890 95.585 ;
        RECT 82.010 90.115 82.180 95.585 ;
        RECT 83.300 90.115 83.470 95.585 ;
        RECT 84.590 90.115 84.760 95.585 ;
        RECT 85.880 90.115 86.050 95.585 ;
        RECT 87.170 90.115 87.340 95.585 ;
        RECT 87.720 90.115 87.910 95.585 ;
        RECT 88.290 90.115 88.460 95.585 ;
        RECT 89.580 90.115 89.750 95.585 ;
        RECT 90.870 90.115 91.040 95.585 ;
        RECT 92.160 90.115 92.330 95.585 ;
        RECT 93.450 90.115 93.620 95.585 ;
        RECT 94.740 90.115 94.910 95.585 ;
        RECT 96.030 90.115 96.200 95.585 ;
        RECT 97.320 90.115 97.490 95.585 ;
        RECT 98.610 90.115 98.780 95.585 ;
        RECT 99.180 90.115 99.350 95.585 ;
        RECT 99.620 108.455 139.480 108.625 ;
        RECT 99.620 92.045 99.790 108.455 ;
        RECT 100.420 107.945 101.420 108.115 ;
        RECT 101.710 107.945 102.710 108.115 ;
        RECT 103.000 107.945 104.000 108.115 ;
        RECT 104.290 107.945 105.290 108.115 ;
        RECT 105.580 107.945 106.580 108.115 ;
        RECT 106.870 107.945 107.870 108.115 ;
        RECT 108.160 107.945 109.160 108.115 ;
        RECT 109.450 107.945 110.450 108.115 ;
        RECT 110.740 107.945 111.740 108.115 ;
        RECT 112.030 107.945 113.030 108.115 ;
        RECT 113.320 107.945 114.320 108.115 ;
        RECT 114.610 107.945 115.610 108.115 ;
        RECT 115.900 107.945 116.900 108.115 ;
        RECT 117.190 107.945 118.190 108.115 ;
        RECT 99.615 91.405 99.790 92.045 ;
        RECT 59.660 89.945 99.350 90.115 ;
        RECT 59.660 89.605 59.830 89.945 ;
        RECT 68.540 89.605 68.710 89.945 ;
        RECT 69.110 89.605 69.280 89.945 ;
        RECT 70.400 89.605 70.570 89.945 ;
        RECT 71.690 89.605 71.860 89.945 ;
        RECT 72.980 89.605 73.150 89.945 ;
        RECT 74.270 89.605 74.440 89.945 ;
        RECT 75.560 89.605 75.730 89.945 ;
        RECT 76.850 89.605 77.020 89.945 ;
        RECT 78.140 89.605 78.310 89.945 ;
        RECT 79.430 89.605 79.600 89.945 ;
        RECT 80.720 89.605 80.890 89.945 ;
        RECT 82.010 89.605 82.180 89.945 ;
        RECT 83.300 89.605 83.470 89.945 ;
        RECT 84.590 89.605 84.760 89.945 ;
        RECT 85.880 89.605 86.050 89.945 ;
        RECT 87.170 89.605 87.340 89.945 ;
        RECT 87.720 89.605 87.910 89.945 ;
        RECT 88.290 89.605 88.460 89.945 ;
        RECT 89.580 89.605 89.750 89.945 ;
        RECT 90.870 89.605 91.040 89.945 ;
        RECT 92.160 89.605 92.330 89.945 ;
        RECT 93.450 89.605 93.620 89.945 ;
        RECT 94.740 89.605 94.910 89.945 ;
        RECT 96.030 89.605 96.200 89.945 ;
        RECT 97.320 89.605 97.490 89.945 ;
        RECT 98.610 89.605 98.780 89.945 ;
        RECT 99.180 89.605 99.350 89.945 ;
        RECT 59.660 89.435 99.350 89.605 ;
        RECT 59.670 88.955 96.770 89.125 ;
        RECT 59.670 83.875 59.840 88.955 ;
        RECT 60.230 88.615 60.400 88.955 ;
        RECT 61.520 88.615 61.690 88.955 ;
        RECT 62.810 88.615 62.980 88.955 ;
        RECT 64.100 88.615 64.270 88.955 ;
        RECT 65.390 88.615 65.560 88.955 ;
        RECT 66.680 88.615 66.850 88.955 ;
        RECT 67.970 88.615 68.140 88.955 ;
        RECT 60.230 88.445 68.140 88.615 ;
        RECT 60.230 87.565 60.400 88.445 ;
        RECT 61.520 87.565 61.690 88.445 ;
        RECT 62.810 87.565 62.980 88.445 ;
        RECT 64.100 87.565 64.270 88.445 ;
        RECT 65.390 87.565 65.560 88.445 ;
        RECT 66.680 87.565 66.850 88.445 ;
        RECT 67.970 87.565 68.140 88.445 ;
        RECT 60.230 87.395 68.140 87.565 ;
        RECT 60.565 86.855 61.355 87.025 ;
        RECT 61.855 86.855 62.645 87.025 ;
        RECT 63.145 86.855 63.935 87.025 ;
        RECT 64.435 86.855 65.225 87.025 ;
        RECT 65.725 86.855 66.515 87.025 ;
        RECT 67.015 86.855 67.805 87.025 ;
        RECT 60.230 86.145 60.400 86.685 ;
        RECT 61.520 86.145 61.690 86.685 ;
        RECT 62.810 86.145 62.980 86.685 ;
        RECT 64.100 86.145 64.270 86.685 ;
        RECT 65.390 86.145 65.560 86.685 ;
        RECT 66.680 86.145 66.850 86.685 ;
        RECT 67.970 86.145 68.140 86.685 ;
        RECT 60.565 85.805 61.355 85.975 ;
        RECT 61.855 85.805 62.645 85.975 ;
        RECT 63.145 85.805 63.935 85.975 ;
        RECT 64.435 85.805 65.225 85.975 ;
        RECT 65.725 85.805 66.515 85.975 ;
        RECT 67.015 85.805 67.805 85.975 ;
        RECT 60.230 85.265 68.140 85.435 ;
        RECT 60.230 84.385 60.400 85.265 ;
        RECT 61.520 84.385 61.690 85.265 ;
        RECT 62.810 84.385 62.980 85.265 ;
        RECT 64.100 84.385 64.270 85.265 ;
        RECT 65.390 84.385 65.560 85.265 ;
        RECT 66.680 84.385 66.850 85.265 ;
        RECT 67.970 84.385 68.140 85.265 ;
        RECT 60.230 84.215 68.140 84.385 ;
        RECT 60.230 83.875 60.400 84.215 ;
        RECT 61.520 83.875 61.690 84.215 ;
        RECT 62.810 83.875 62.980 84.215 ;
        RECT 64.100 83.875 64.270 84.215 ;
        RECT 65.390 83.875 65.560 84.215 ;
        RECT 66.680 83.875 66.850 84.215 ;
        RECT 68.550 83.875 68.720 88.955 ;
        RECT 69.100 88.615 69.270 88.955 ;
        RECT 70.390 88.615 70.560 88.955 ;
        RECT 71.680 88.615 71.850 88.955 ;
        RECT 72.970 88.615 73.140 88.955 ;
        RECT 74.260 88.615 74.430 88.955 ;
        RECT 75.550 88.615 75.720 88.955 ;
        RECT 78.130 88.615 78.300 88.955 ;
        RECT 79.420 88.615 79.590 88.955 ;
        RECT 80.710 88.615 80.880 88.955 ;
        RECT 82.000 88.615 82.170 88.955 ;
        RECT 83.290 88.615 83.460 88.955 ;
        RECT 84.580 88.615 84.750 88.955 ;
        RECT 69.100 88.445 84.750 88.615 ;
        RECT 69.100 87.565 69.270 88.445 ;
        RECT 70.390 87.565 70.560 88.445 ;
        RECT 71.680 87.565 71.850 88.445 ;
        RECT 72.970 87.565 73.140 88.445 ;
        RECT 74.260 87.565 74.430 88.445 ;
        RECT 75.550 87.565 75.720 88.445 ;
        RECT 76.840 87.565 77.010 88.445 ;
        RECT 78.130 87.565 78.300 88.445 ;
        RECT 79.420 87.565 79.590 88.445 ;
        RECT 80.710 87.565 80.880 88.445 ;
        RECT 82.000 87.565 82.170 88.445 ;
        RECT 83.290 87.565 83.460 88.445 ;
        RECT 84.580 87.565 84.750 88.445 ;
        RECT 69.100 87.395 84.750 87.565 ;
        RECT 69.435 86.855 70.225 87.025 ;
        RECT 70.725 86.855 71.515 87.025 ;
        RECT 72.015 86.855 72.805 87.025 ;
        RECT 73.305 86.855 74.095 87.025 ;
        RECT 74.595 86.855 75.385 87.025 ;
        RECT 75.885 86.855 76.675 87.025 ;
        RECT 77.175 86.855 77.965 87.025 ;
        RECT 78.465 86.855 79.255 87.025 ;
        RECT 79.755 86.855 80.545 87.025 ;
        RECT 81.045 86.855 81.835 87.025 ;
        RECT 82.335 86.855 83.125 87.025 ;
        RECT 83.625 86.855 84.415 87.025 ;
        RECT 69.100 86.145 69.270 86.685 ;
        RECT 70.390 86.145 70.560 86.685 ;
        RECT 71.680 86.145 71.850 86.685 ;
        RECT 72.970 86.145 73.140 86.685 ;
        RECT 74.260 86.145 74.430 86.685 ;
        RECT 75.550 86.145 75.720 86.685 ;
        RECT 76.840 86.145 77.010 86.685 ;
        RECT 78.130 86.145 78.300 86.685 ;
        RECT 79.420 86.145 79.590 86.685 ;
        RECT 80.710 86.145 80.880 86.685 ;
        RECT 82.000 86.145 82.170 86.685 ;
        RECT 83.290 86.145 83.460 86.685 ;
        RECT 84.580 86.145 84.750 86.685 ;
        RECT 69.435 85.805 70.225 85.975 ;
        RECT 70.725 85.805 71.515 85.975 ;
        RECT 72.015 85.805 72.805 85.975 ;
        RECT 73.305 85.805 74.095 85.975 ;
        RECT 74.595 85.805 75.385 85.975 ;
        RECT 75.885 85.805 76.675 85.975 ;
        RECT 77.175 85.805 77.965 85.975 ;
        RECT 78.465 85.805 79.255 85.975 ;
        RECT 79.755 85.805 80.545 85.975 ;
        RECT 81.045 85.805 81.835 85.975 ;
        RECT 82.335 85.805 83.125 85.975 ;
        RECT 83.625 85.805 84.415 85.975 ;
        RECT 69.100 85.265 84.750 85.435 ;
        RECT 69.100 84.385 69.270 85.265 ;
        RECT 70.390 84.385 70.560 85.265 ;
        RECT 71.680 84.385 71.850 85.265 ;
        RECT 72.970 84.385 73.140 85.265 ;
        RECT 74.260 84.385 74.430 85.265 ;
        RECT 75.550 84.385 75.720 85.265 ;
        RECT 76.840 84.385 77.010 85.265 ;
        RECT 78.130 84.385 78.300 85.265 ;
        RECT 79.420 84.385 79.590 85.265 ;
        RECT 80.710 84.385 80.880 85.265 ;
        RECT 82.000 84.385 82.170 85.265 ;
        RECT 83.290 84.385 83.460 85.265 ;
        RECT 84.580 84.385 84.750 85.265 ;
        RECT 69.100 84.215 84.750 84.385 ;
        RECT 69.100 83.875 69.270 84.215 ;
        RECT 70.390 83.875 70.560 84.215 ;
        RECT 71.680 83.875 71.850 84.215 ;
        RECT 72.970 83.875 73.140 84.215 ;
        RECT 74.260 83.875 74.430 84.215 ;
        RECT 75.550 83.875 75.720 84.215 ;
        RECT 76.840 83.875 77.010 84.215 ;
        RECT 78.130 83.875 78.300 84.215 ;
        RECT 79.420 83.875 79.590 84.215 ;
        RECT 80.710 83.875 80.880 84.215 ;
        RECT 82.000 83.875 82.170 84.215 ;
        RECT 83.290 83.875 83.460 84.215 ;
        RECT 84.580 83.875 84.750 84.215 ;
        RECT 85.160 83.875 85.330 88.955 ;
        RECT 85.700 88.615 85.870 88.955 ;
        RECT 86.990 88.615 87.160 88.955 ;
        RECT 88.280 88.615 88.450 88.955 ;
        RECT 89.570 88.615 89.740 88.955 ;
        RECT 90.860 88.615 91.030 88.955 ;
        RECT 92.150 88.615 92.320 88.955 ;
        RECT 93.440 88.615 93.610 88.955 ;
        RECT 94.730 88.615 94.900 88.955 ;
        RECT 96.020 88.615 96.190 88.955 ;
        RECT 85.700 88.445 96.190 88.615 ;
        RECT 85.700 87.565 85.870 88.445 ;
        RECT 86.990 87.565 87.160 88.445 ;
        RECT 88.280 87.565 88.450 88.445 ;
        RECT 89.570 87.565 89.740 88.445 ;
        RECT 90.860 87.565 91.030 88.445 ;
        RECT 92.150 87.565 92.320 88.445 ;
        RECT 93.440 87.565 93.610 88.445 ;
        RECT 94.730 87.565 94.900 88.445 ;
        RECT 96.020 87.565 96.190 88.445 ;
        RECT 85.700 87.395 96.190 87.565 ;
        RECT 86.035 86.855 86.825 87.025 ;
        RECT 87.325 86.855 88.115 87.025 ;
        RECT 88.615 86.855 89.405 87.025 ;
        RECT 89.905 86.855 90.695 87.025 ;
        RECT 91.195 86.855 91.985 87.025 ;
        RECT 92.485 86.855 93.275 87.025 ;
        RECT 93.775 86.855 94.565 87.025 ;
        RECT 95.065 86.855 95.855 87.025 ;
        RECT 85.700 86.145 85.870 86.685 ;
        RECT 86.990 86.145 87.160 86.685 ;
        RECT 88.280 86.145 88.450 86.685 ;
        RECT 89.570 86.145 89.740 86.685 ;
        RECT 90.860 86.145 91.030 86.685 ;
        RECT 92.150 86.145 92.320 86.685 ;
        RECT 93.440 86.145 93.610 86.685 ;
        RECT 94.730 86.145 94.900 86.685 ;
        RECT 96.020 86.145 96.190 86.685 ;
        RECT 86.035 85.805 86.825 85.975 ;
        RECT 87.325 85.805 88.115 85.975 ;
        RECT 88.615 85.805 89.405 85.975 ;
        RECT 89.905 85.805 90.695 85.975 ;
        RECT 91.195 85.805 91.985 85.975 ;
        RECT 92.485 85.805 93.275 85.975 ;
        RECT 93.775 85.805 94.565 85.975 ;
        RECT 95.065 85.805 95.855 85.975 ;
        RECT 85.700 85.265 96.190 85.435 ;
        RECT 85.700 84.385 85.870 85.265 ;
        RECT 86.990 84.385 87.160 85.265 ;
        RECT 88.280 84.385 88.450 85.265 ;
        RECT 89.570 84.385 89.740 85.265 ;
        RECT 90.860 84.385 91.030 85.265 ;
        RECT 92.150 84.385 92.320 85.265 ;
        RECT 93.440 84.385 93.610 85.265 ;
        RECT 94.730 84.385 94.900 85.265 ;
        RECT 96.020 84.385 96.190 85.265 ;
        RECT 85.700 84.215 96.190 84.385 ;
        RECT 85.700 83.875 85.870 84.215 ;
        RECT 86.990 83.875 87.160 84.215 ;
        RECT 88.280 83.875 88.450 84.215 ;
        RECT 89.570 83.875 89.740 84.215 ;
        RECT 90.860 83.875 91.030 84.215 ;
        RECT 92.150 83.875 92.320 84.215 ;
        RECT 93.440 83.875 93.610 84.215 ;
        RECT 94.730 83.875 94.900 84.215 ;
        RECT 96.020 83.875 96.190 84.215 ;
        RECT 96.600 83.875 96.770 88.955 ;
        RECT 59.670 83.705 96.770 83.875 ;
        RECT 60.395 83.225 74.995 83.395 ;
        RECT 60.395 76.970 60.565 83.225 ;
        RECT 66.685 82.710 68.145 82.880 ;
        RECT 66.685 82.365 66.855 82.710 ;
        RECT 61.275 82.195 66.855 82.365 ;
        RECT 60.965 81.440 61.135 81.980 ;
        RECT 62.255 81.440 62.425 81.980 ;
        RECT 63.545 81.225 63.715 82.195 ;
        RECT 64.835 81.225 65.005 82.195 ;
        RECT 66.125 81.260 66.295 82.195 ;
        RECT 66.685 81.440 66.855 82.195 ;
        RECT 67.975 81.440 68.145 82.710 ;
        RECT 68.845 82.290 69.685 82.460 ;
        RECT 70.695 82.415 71.535 82.585 ;
        RECT 71.985 82.415 72.825 82.585 ;
        RECT 73.275 82.415 74.115 82.585 ;
        RECT 68.535 81.535 68.705 82.075 ;
        RECT 69.825 81.535 69.995 82.075 ;
        RECT 70.385 81.570 70.555 82.200 ;
        RECT 71.675 81.570 71.845 82.200 ;
        RECT 72.965 81.570 73.135 82.200 ;
        RECT 74.255 81.570 74.425 82.200 ;
        RECT 66.685 81.270 68.145 81.440 ;
        RECT 66.685 81.260 66.855 81.270 ;
        RECT 65.785 81.225 66.855 81.260 ;
        RECT 61.275 81.090 66.855 81.225 ;
        RECT 68.845 81.150 69.685 81.320 ;
        RECT 70.695 81.185 71.535 81.355 ;
        RECT 71.985 81.185 72.825 81.355 ;
        RECT 73.275 81.185 74.115 81.355 ;
        RECT 61.275 81.055 65.955 81.090 ;
        RECT 67.025 80.730 67.805 80.900 ;
        RECT 70.385 80.780 71.845 80.815 ;
        RECT 61.275 80.515 62.115 80.685 ;
        RECT 62.595 80.515 63.375 80.685 ;
        RECT 63.885 80.515 64.665 80.685 ;
        RECT 64.835 80.515 66.295 80.685 ;
        RECT 68.875 80.645 71.845 80.780 ;
        RECT 72.015 80.645 72.795 80.815 ;
        RECT 73.275 80.645 74.115 80.815 ;
        RECT 68.875 80.610 70.555 80.645 ;
        RECT 60.965 79.760 61.135 80.300 ;
        RECT 62.255 79.760 62.425 80.300 ;
        RECT 63.545 79.760 63.715 80.300 ;
        RECT 64.835 79.545 65.005 80.515 ;
        RECT 66.125 79.545 66.295 80.515 ;
        RECT 66.685 79.675 66.855 80.515 ;
        RECT 67.975 79.675 68.145 80.515 ;
        RECT 68.535 79.855 68.705 80.395 ;
        RECT 69.825 79.855 69.995 80.395 ;
        RECT 70.385 79.640 70.555 80.610 ;
        RECT 61.275 79.375 62.115 79.545 ;
        RECT 62.595 79.375 63.375 79.545 ;
        RECT 63.885 79.375 64.665 79.545 ;
        RECT 64.835 79.375 66.295 79.545 ;
        RECT 68.875 79.585 70.555 79.640 ;
        RECT 71.675 79.585 71.845 80.645 ;
        RECT 72.965 79.800 73.135 80.430 ;
        RECT 74.255 79.800 74.425 80.430 ;
        RECT 68.875 79.470 71.845 79.585 ;
        RECT 67.025 79.290 67.805 79.460 ;
        RECT 70.385 79.415 71.845 79.470 ;
        RECT 72.015 79.415 72.795 79.585 ;
        RECT 73.275 79.415 74.115 79.585 ;
        RECT 68.535 79.045 70.560 79.100 ;
        RECT 61.275 78.920 66.295 79.005 ;
        RECT 68.535 78.930 74.115 79.045 ;
        RECT 61.275 78.835 68.145 78.920 ;
        RECT 60.965 78.080 61.135 78.620 ;
        RECT 62.255 78.080 62.425 78.620 ;
        RECT 63.545 77.865 63.715 78.835 ;
        RECT 64.835 77.865 65.005 78.835 ;
        RECT 66.125 78.750 68.145 78.835 ;
        RECT 66.125 77.865 66.295 78.750 ;
        RECT 66.685 77.865 66.855 78.750 ;
        RECT 61.275 77.695 66.855 77.865 ;
        RECT 66.685 77.480 66.855 77.695 ;
        RECT 67.975 77.480 68.145 78.750 ;
        RECT 68.535 77.960 68.705 78.930 ;
        RECT 69.825 77.960 69.995 78.930 ;
        RECT 70.385 78.875 74.115 78.930 ;
        RECT 70.385 77.960 70.555 78.875 ;
        RECT 68.535 77.815 70.555 77.960 ;
        RECT 71.675 77.815 71.845 78.875 ;
        RECT 72.965 78.030 73.135 78.660 ;
        RECT 74.255 78.030 74.425 78.660 ;
        RECT 68.535 77.790 74.115 77.815 ;
        RECT 70.385 77.645 74.115 77.790 ;
        RECT 66.685 77.310 68.145 77.480 ;
        RECT 70.435 76.970 70.630 76.975 ;
        RECT 74.825 76.970 74.995 83.225 ;
        RECT 87.650 82.015 97.490 82.185 ;
        RECT 87.650 79.045 87.820 82.015 ;
        RECT 88.300 81.185 90.460 81.535 ;
        RECT 94.680 81.185 96.840 81.535 ;
        RECT 88.300 80.355 90.460 80.705 ;
        RECT 94.680 80.355 96.840 80.705 ;
        RECT 88.300 79.525 90.460 79.875 ;
        RECT 94.680 79.525 96.840 79.875 ;
        RECT 97.320 79.045 97.490 82.015 ;
        RECT 87.650 78.245 97.490 79.045 ;
        RECT 60.395 76.800 74.995 76.970 ;
        RECT 86.780 78.075 98.370 78.245 ;
        RECT 59.840 76.320 75.175 76.490 ;
        RECT 59.840 70.720 60.010 76.320 ;
        RECT 60.755 75.805 64.455 75.975 ;
        RECT 60.415 74.925 60.585 75.635 ;
        RECT 61.705 74.925 61.875 75.635 ;
        RECT 62.995 74.755 63.165 75.805 ;
        RECT 64.285 74.755 64.455 75.805 ;
        RECT 60.755 74.585 64.455 74.755 ;
        RECT 64.845 75.725 72.975 75.895 ;
        RECT 73.485 75.725 74.265 75.895 ;
        RECT 64.845 74.845 65.015 75.725 ;
        RECT 66.135 74.845 66.305 75.725 ;
        RECT 67.425 74.845 67.595 75.725 ;
        RECT 68.715 74.845 68.885 75.725 ;
        RECT 70.005 74.845 70.175 75.725 ;
        RECT 70.565 74.845 70.735 75.725 ;
        RECT 71.855 74.845 72.025 75.725 ;
        RECT 73.145 75.015 73.315 75.555 ;
        RECT 74.435 75.015 74.605 75.555 ;
        RECT 64.845 74.675 72.975 74.845 ;
        RECT 73.485 74.675 74.265 74.845 ;
        RECT 60.755 74.045 61.535 74.215 ;
        RECT 62.045 74.045 62.825 74.215 ;
        RECT 63.305 74.045 64.145 74.215 ;
        RECT 65.185 73.965 65.965 74.135 ;
        RECT 66.475 73.965 67.595 74.135 ;
        RECT 67.765 73.965 68.545 74.135 ;
        RECT 69.055 73.965 69.835 74.135 ;
        RECT 70.565 73.965 72.025 74.135 ;
        RECT 72.195 73.965 72.975 74.135 ;
        RECT 73.485 73.965 74.265 74.135 ;
        RECT 60.415 73.165 60.585 73.875 ;
        RECT 61.705 73.165 61.875 73.875 ;
        RECT 62.995 73.165 63.165 73.875 ;
        RECT 64.285 73.165 64.455 73.875 ;
        RECT 64.845 73.255 65.015 73.795 ;
        RECT 66.135 73.255 66.305 73.795 ;
        RECT 67.425 73.085 67.595 73.965 ;
        RECT 68.715 73.255 68.885 73.795 ;
        RECT 70.005 73.255 70.175 73.795 ;
        RECT 70.565 73.085 70.735 73.965 ;
        RECT 71.855 73.085 72.025 73.965 ;
        RECT 73.145 73.255 73.315 73.795 ;
        RECT 74.435 73.255 74.605 73.795 ;
        RECT 60.755 72.825 61.535 72.995 ;
        RECT 62.045 72.825 62.825 72.995 ;
        RECT 63.305 72.825 64.145 72.995 ;
        RECT 65.185 72.915 65.965 73.085 ;
        RECT 66.475 72.915 67.595 73.085 ;
        RECT 67.765 72.915 68.545 73.085 ;
        RECT 69.055 72.915 69.835 73.085 ;
        RECT 70.565 72.915 72.025 73.085 ;
        RECT 72.195 72.915 72.975 73.085 ;
        RECT 73.485 72.915 74.265 73.085 ;
        RECT 60.755 72.285 64.455 72.455 ;
        RECT 60.415 71.405 60.585 72.115 ;
        RECT 61.705 71.405 61.875 72.115 ;
        RECT 62.995 71.235 63.165 72.285 ;
        RECT 64.285 71.235 64.455 72.285 ;
        RECT 60.755 71.065 64.455 71.235 ;
        RECT 64.845 72.205 72.975 72.375 ;
        RECT 73.455 72.205 74.295 72.375 ;
        RECT 64.845 71.325 65.015 72.205 ;
        RECT 66.135 71.325 66.305 72.205 ;
        RECT 67.425 71.325 67.595 72.205 ;
        RECT 68.715 71.325 68.885 72.205 ;
        RECT 70.005 71.325 70.175 72.205 ;
        RECT 70.565 71.325 70.735 72.205 ;
        RECT 71.855 71.325 72.025 72.205 ;
        RECT 73.145 71.495 73.315 72.035 ;
        RECT 74.435 71.495 74.605 72.035 ;
        RECT 64.845 71.155 72.975 71.325 ;
        RECT 73.455 71.155 74.295 71.325 ;
        RECT 75.005 70.720 75.175 76.320 ;
        RECT 86.780 75.105 86.950 78.075 ;
        RECT 87.430 77.245 89.590 77.595 ;
        RECT 95.560 77.245 97.720 77.595 ;
        RECT 87.430 76.415 89.590 76.765 ;
        RECT 95.560 76.415 97.720 76.765 ;
        RECT 87.430 75.585 89.590 75.935 ;
        RECT 95.560 75.585 97.720 75.935 ;
        RECT 98.200 75.105 98.370 78.075 ;
        RECT 86.780 74.935 98.370 75.105 ;
        RECT 87.240 74.195 97.950 74.935 ;
        RECT 87.240 71.225 87.410 74.195 ;
        RECT 87.890 73.365 90.050 73.715 ;
        RECT 95.140 73.365 97.300 73.715 ;
        RECT 97.780 72.895 97.950 74.195 ;
        RECT 97.150 72.885 97.950 72.895 ;
        RECT 87.890 72.535 90.050 72.885 ;
        RECT 95.140 72.545 97.950 72.885 ;
        RECT 95.140 72.535 97.300 72.545 ;
        RECT 87.890 71.705 90.050 72.055 ;
        RECT 95.140 71.705 97.300 72.055 ;
        RECT 87.720 71.225 97.470 71.235 ;
        RECT 97.780 71.225 97.950 72.545 ;
        RECT 87.240 71.055 97.950 71.225 ;
        RECT 59.840 70.250 75.175 70.720 ;
        RECT 59.840 70.085 67.050 70.250 ;
        RECT 59.840 68.775 60.010 70.085 ;
        RECT 60.490 69.255 62.650 69.605 ;
        RECT 64.240 69.255 66.400 69.605 ;
        RECT 66.880 68.775 67.050 70.085 ;
        RECT 59.840 68.605 67.050 68.775 ;
        RECT 67.965 70.085 75.175 70.250 ;
        RECT 67.965 68.775 68.135 70.085 ;
        RECT 68.615 69.255 70.775 69.605 ;
        RECT 72.365 69.255 74.525 69.605 ;
        RECT 75.005 68.775 75.175 70.085 ;
        RECT 67.965 68.605 75.175 68.775 ;
        RECT 99.620 60.965 99.790 91.405 ;
        RECT 100.190 61.690 100.360 107.730 ;
        RECT 101.480 61.690 101.650 107.730 ;
        RECT 102.770 61.690 102.940 107.730 ;
        RECT 104.060 61.690 104.230 107.730 ;
        RECT 105.350 61.690 105.520 107.730 ;
        RECT 106.640 61.690 106.810 107.730 ;
        RECT 107.930 61.690 108.100 107.730 ;
        RECT 109.220 61.690 109.390 107.730 ;
        RECT 110.510 61.690 110.680 107.730 ;
        RECT 111.800 61.690 111.970 107.730 ;
        RECT 113.090 61.690 113.260 107.730 ;
        RECT 114.380 61.690 114.550 107.730 ;
        RECT 115.670 61.690 115.840 107.730 ;
        RECT 116.960 61.690 117.130 107.730 ;
        RECT 118.250 61.690 118.420 107.730 ;
        RECT 100.420 61.305 101.420 61.475 ;
        RECT 101.710 61.305 102.710 61.475 ;
        RECT 103.000 61.305 104.000 61.475 ;
        RECT 104.290 61.305 105.290 61.475 ;
        RECT 105.580 61.305 106.580 61.475 ;
        RECT 106.870 61.305 107.870 61.475 ;
        RECT 108.160 61.305 109.160 61.475 ;
        RECT 109.450 61.305 110.450 61.475 ;
        RECT 110.740 61.305 111.740 61.475 ;
        RECT 112.030 61.305 113.030 61.475 ;
        RECT 113.320 61.305 114.320 61.475 ;
        RECT 114.610 61.305 115.610 61.475 ;
        RECT 115.900 61.305 116.900 61.475 ;
        RECT 117.190 61.305 118.190 61.475 ;
        RECT 118.820 60.965 118.990 108.455 ;
        RECT 119.620 107.945 120.620 108.115 ;
        RECT 120.910 107.945 121.910 108.115 ;
        RECT 122.200 107.945 123.200 108.115 ;
        RECT 123.490 107.945 124.490 108.115 ;
        RECT 124.780 107.945 125.780 108.115 ;
        RECT 126.070 107.945 127.070 108.115 ;
        RECT 127.360 107.945 128.360 108.115 ;
        RECT 128.650 107.945 129.650 108.115 ;
        RECT 129.940 107.945 130.940 108.115 ;
        RECT 131.230 107.945 132.230 108.115 ;
        RECT 132.520 107.945 133.520 108.115 ;
        RECT 133.810 107.945 134.810 108.115 ;
        RECT 135.100 107.945 136.100 108.115 ;
        RECT 136.390 107.945 137.390 108.115 ;
        RECT 137.680 107.945 138.680 108.115 ;
        RECT 119.390 61.690 119.560 107.730 ;
        RECT 120.680 61.690 120.850 107.730 ;
        RECT 121.970 61.690 122.140 107.730 ;
        RECT 123.260 61.690 123.430 107.730 ;
        RECT 124.550 61.690 124.720 107.730 ;
        RECT 125.840 61.690 126.010 107.730 ;
        RECT 127.130 61.690 127.300 107.730 ;
        RECT 128.420 61.690 128.590 107.730 ;
        RECT 129.710 61.690 129.880 107.730 ;
        RECT 131.000 61.690 131.170 107.730 ;
        RECT 132.290 61.690 132.460 107.730 ;
        RECT 133.580 61.690 133.750 107.730 ;
        RECT 134.870 61.690 135.040 107.730 ;
        RECT 136.160 61.690 136.330 107.730 ;
        RECT 137.450 61.690 137.620 107.730 ;
        RECT 138.740 61.690 138.910 107.730 ;
        RECT 119.620 61.305 120.620 61.475 ;
        RECT 120.910 61.305 121.910 61.475 ;
        RECT 122.200 61.305 123.200 61.475 ;
        RECT 123.490 61.305 124.490 61.475 ;
        RECT 124.780 61.305 125.780 61.475 ;
        RECT 126.070 61.305 127.070 61.475 ;
        RECT 127.360 61.305 128.360 61.475 ;
        RECT 128.650 61.305 129.650 61.475 ;
        RECT 129.940 61.305 130.940 61.475 ;
        RECT 131.230 61.305 132.230 61.475 ;
        RECT 132.520 61.305 133.520 61.475 ;
        RECT 133.810 61.305 134.810 61.475 ;
        RECT 135.100 61.305 136.100 61.475 ;
        RECT 136.390 61.305 137.390 61.475 ;
        RECT 137.680 61.305 138.680 61.475 ;
        RECT 139.310 60.965 139.480 108.455 ;
        RECT 99.620 60.795 139.480 60.965 ;
      LAYER met1 ;
        RECT 12.430 215.235 43.015 215.655 ;
        RECT 12.570 214.570 14.675 214.820 ;
        RECT 40.815 214.570 42.920 214.820 ;
        RECT 60.420 214.500 60.740 214.505 ;
        RECT 60.420 214.495 136.335 214.500 ;
        RECT 12.570 212.910 14.675 213.990 ;
        RECT 40.815 213.380 42.920 214.340 ;
        RECT 60.420 214.180 140.000 214.495 ;
        RECT 60.420 213.940 62.560 214.180 ;
        RECT 63.620 213.940 63.850 214.180 ;
        RECT 66.200 213.940 66.430 214.180 ;
        RECT 67.490 213.940 67.720 214.180 ;
        RECT 68.780 213.940 69.625 214.180 ;
        RECT 60.420 213.710 64.755 213.940 ;
        RECT 65.295 213.710 69.625 213.940 ;
        RECT 42.905 213.160 44.255 213.165 ;
        RECT 40.815 212.475 44.255 213.160 ;
        RECT 12.570 212.080 14.675 212.330 ;
        RECT 40.815 212.080 42.920 212.330 ;
        RECT 12.570 209.880 14.675 210.130 ;
        RECT 40.815 209.880 42.920 210.130 ;
        RECT 43.355 209.740 44.255 212.475 ;
        RECT 12.570 208.220 14.675 209.300 ;
        RECT 40.815 209.050 44.255 209.740 ;
        RECT 42.780 209.045 44.255 209.050 ;
        RECT 12.570 206.560 14.675 207.640 ;
        RECT 40.815 207.390 42.920 208.470 ;
        RECT 60.420 208.300 60.740 213.710 ;
        RECT 61.040 208.300 61.270 213.710 ;
        RECT 62.330 208.300 62.560 213.710 ;
        RECT 63.620 212.380 63.850 213.710 ;
        RECT 66.200 212.380 66.430 213.710 ;
        RECT 63.575 211.740 63.895 212.380 ;
        RECT 66.155 211.740 66.475 212.380 ;
        RECT 63.620 210.650 63.850 211.740 ;
        RECT 66.200 210.650 66.430 211.740 ;
        RECT 63.575 210.010 63.895 210.650 ;
        RECT 66.155 210.010 66.475 210.650 ;
        RECT 63.620 208.300 63.850 210.010 ;
        RECT 64.865 209.145 65.185 209.785 ;
        RECT 60.420 208.070 64.755 208.300 ;
        RECT 12.570 204.900 14.675 205.980 ;
        RECT 40.815 205.730 42.920 206.810 ;
        RECT 11.320 203.735 14.675 204.650 ;
        RECT 40.815 204.070 42.920 205.150 ;
        RECT 11.320 200.805 12.255 203.735 ;
        RECT 12.570 203.240 14.675 203.490 ;
        RECT 40.815 203.240 42.920 203.490 ;
        RECT 12.570 201.040 14.675 201.290 ;
        RECT 40.815 201.040 42.920 201.290 ;
        RECT 11.320 199.890 14.675 200.805 ;
        RECT 12.570 198.550 14.675 199.630 ;
        RECT 40.815 199.380 42.920 200.460 ;
        RECT 12.570 196.890 14.675 197.970 ;
        RECT 40.815 197.720 42.920 198.800 ;
        RECT 12.570 196.310 12.890 196.665 ;
        RECT 12.570 196.060 14.675 196.310 ;
        RECT 40.815 196.060 42.920 197.140 ;
        RECT 12.570 195.705 12.890 196.060 ;
        RECT 12.570 195.230 14.675 195.480 ;
        RECT 40.815 195.230 42.920 195.480 ;
        RECT 60.420 195.135 60.740 208.070 ;
        RECT 61.040 207.855 62.745 207.860 ;
        RECT 61.040 207.535 63.470 207.855 ;
        RECT 61.040 202.125 61.270 207.535 ;
        RECT 61.425 207.530 62.175 207.535 ;
        RECT 62.715 207.530 63.465 207.535 ;
        RECT 62.330 203.015 62.560 207.325 ;
        RECT 62.330 202.325 62.565 203.015 ;
        RECT 62.335 202.125 62.565 202.325 ;
        RECT 61.040 201.805 63.470 202.125 ;
        RECT 61.040 201.800 62.565 201.805 ;
        RECT 61.040 201.350 62.175 201.580 ;
        RECT 61.040 195.940 61.270 201.350 ;
        RECT 61.040 195.710 62.175 195.940 ;
        RECT 12.260 194.390 43.065 194.830 ;
        RECT 60.395 189.755 60.755 194.995 ;
        RECT 62.335 192.850 62.565 201.800 ;
        RECT 63.620 199.475 63.850 208.070 ;
        RECT 64.010 207.760 64.760 207.855 ;
        RECT 64.005 207.535 64.760 207.760 ;
        RECT 64.005 207.530 64.755 207.535 ;
        RECT 64.010 202.120 64.760 202.125 ;
        RECT 64.005 201.890 64.760 202.120 ;
        RECT 64.010 201.805 64.760 201.890 ;
        RECT 64.060 201.800 64.700 201.805 ;
        RECT 64.910 200.520 65.140 209.145 ;
        RECT 66.200 208.300 66.430 210.010 ;
        RECT 67.490 208.300 67.720 213.710 ;
        RECT 68.780 208.300 69.010 213.710 ;
        RECT 69.305 208.300 69.625 213.710 ;
        RECT 69.920 213.940 70.150 214.180 ;
        RECT 71.210 213.940 71.450 214.180 ;
        RECT 69.920 213.710 71.490 213.940 ;
        RECT 73.745 213.830 74.065 214.180 ;
        RECT 76.325 213.830 76.645 214.180 ;
        RECT 78.905 213.830 79.225 214.180 ;
        RECT 81.485 213.830 81.805 214.180 ;
        RECT 84.065 213.830 84.385 214.180 ;
        RECT 86.645 213.830 88.250 214.180 ;
        RECT 69.920 212.380 70.150 213.710 ;
        RECT 71.210 212.380 71.450 213.710 ;
        RECT 73.790 212.380 74.020 213.830 ;
        RECT 75.035 212.610 75.355 213.250 ;
        RECT 69.875 211.740 70.195 212.380 ;
        RECT 71.165 211.740 71.485 212.380 ;
        RECT 73.745 211.740 74.065 212.380 ;
        RECT 69.920 210.650 70.150 211.740 ;
        RECT 71.210 210.650 71.450 211.740 ;
        RECT 72.455 210.855 72.775 211.495 ;
        RECT 69.875 210.010 70.195 210.650 ;
        RECT 71.165 210.010 71.485 210.650 ;
        RECT 65.295 208.070 69.625 208.300 ;
        RECT 65.300 207.760 66.050 207.855 ;
        RECT 65.295 207.535 66.050 207.760 ;
        RECT 65.295 207.530 66.045 207.535 ;
        RECT 65.300 202.120 66.050 202.125 ;
        RECT 65.295 201.890 66.050 202.120 ;
        RECT 65.300 201.805 66.050 201.890 ;
        RECT 65.350 201.800 65.990 201.805 ;
        RECT 64.865 199.880 65.185 200.520 ;
        RECT 63.575 198.835 63.895 199.475 ;
        RECT 63.620 197.840 63.850 198.835 ;
        RECT 63.575 197.200 63.895 197.840 ;
        RECT 63.620 195.230 63.850 197.200 ;
        RECT 63.575 194.995 63.895 195.000 ;
        RECT 62.705 194.690 64.770 194.995 ;
        RECT 63.575 194.680 63.895 194.690 ;
        RECT 62.770 192.850 63.410 192.940 ;
        RECT 64.060 192.850 64.700 192.940 ;
        RECT 61.040 192.620 62.565 192.850 ;
        RECT 62.715 192.620 63.465 192.850 ;
        RECT 64.005 192.620 64.755 192.850 ;
        RECT 61.040 191.800 61.270 192.620 ;
        RECT 62.330 191.800 62.565 192.620 ;
        RECT 61.040 191.570 62.565 191.800 ;
        RECT 62.715 191.570 63.465 191.800 ;
        RECT 62.770 191.480 63.410 191.570 ;
        RECT 61.040 191.030 62.560 191.260 ;
        RECT 61.040 190.210 61.270 191.030 ;
        RECT 62.330 190.210 62.560 191.030 ;
        RECT 63.620 190.925 63.850 192.460 ;
        RECT 64.910 191.960 65.140 199.880 ;
        RECT 66.200 199.475 66.430 208.070 ;
        RECT 67.315 207.855 69.010 207.860 ;
        RECT 66.590 207.760 69.010 207.855 ;
        RECT 66.585 207.535 69.010 207.760 ;
        RECT 66.585 207.530 67.335 207.535 ;
        RECT 67.875 207.530 68.625 207.535 ;
        RECT 67.490 203.005 67.720 207.325 ;
        RECT 67.490 202.325 67.725 203.005 ;
        RECT 67.495 202.130 67.725 202.325 ;
        RECT 68.780 202.130 69.010 207.535 ;
        RECT 67.315 202.125 69.010 202.130 ;
        RECT 66.590 202.120 69.010 202.125 ;
        RECT 66.585 201.890 69.010 202.120 ;
        RECT 66.590 201.805 69.010 201.890 ;
        RECT 66.640 201.800 67.280 201.805 ;
        RECT 66.150 199.155 66.470 199.475 ;
        RECT 66.155 198.835 66.475 199.155 ;
        RECT 66.200 197.840 66.430 198.835 ;
        RECT 66.155 197.200 66.475 197.840 ;
        RECT 66.200 195.230 66.430 197.200 ;
        RECT 65.280 194.690 67.355 194.995 ;
        RECT 66.155 194.675 66.475 194.690 ;
        RECT 65.350 192.850 65.990 192.940 ;
        RECT 66.640 192.850 67.280 192.940 ;
        RECT 67.495 192.850 67.725 201.805 ;
        RECT 67.875 201.350 69.010 201.580 ;
        RECT 68.780 195.940 69.010 201.350 ;
        RECT 67.875 195.710 69.010 195.940 ;
        RECT 68.780 195.705 69.010 195.710 ;
        RECT 69.305 195.455 69.625 208.070 ;
        RECT 69.920 208.300 70.150 210.010 ;
        RECT 71.210 208.300 71.450 210.010 ;
        RECT 71.655 209.780 71.975 209.785 ;
        RECT 71.655 209.145 72.295 209.780 ;
        RECT 71.975 209.140 72.295 209.145 ;
        RECT 69.920 208.070 71.450 208.300 ;
        RECT 69.920 207.760 70.150 208.070 ;
        RECT 71.210 207.760 71.450 208.070 ;
        RECT 69.920 207.530 71.450 207.760 ;
        RECT 71.595 207.530 72.345 207.850 ;
        RECT 69.920 202.120 70.150 207.530 ;
        RECT 71.210 207.160 71.450 207.530 ;
        RECT 71.210 202.120 71.440 207.160 ;
        RECT 69.920 201.890 71.440 202.120 ;
        RECT 69.920 201.580 70.150 201.890 ;
        RECT 71.210 201.580 71.440 201.890 ;
        RECT 71.595 201.800 72.345 202.120 ;
        RECT 69.920 201.350 71.440 201.580 ;
        RECT 69.920 199.475 70.150 201.350 ;
        RECT 71.210 199.475 71.440 201.350 ;
        RECT 69.875 198.835 70.195 199.475 ;
        RECT 71.165 198.835 71.485 199.475 ;
        RECT 69.920 197.840 70.150 198.835 ;
        RECT 71.210 197.840 71.440 198.835 ;
        RECT 72.500 198.650 72.730 210.855 ;
        RECT 73.790 210.650 74.020 211.740 ;
        RECT 73.745 210.010 74.065 210.650 ;
        RECT 72.885 207.530 73.635 207.850 ;
        RECT 72.885 201.800 73.635 202.120 ;
        RECT 73.790 199.475 74.020 210.010 ;
        RECT 74.175 207.530 74.925 207.850 ;
        RECT 74.175 201.800 74.925 202.120 ;
        RECT 73.745 198.835 74.065 199.475 ;
        RECT 72.455 198.010 72.775 198.650 ;
        RECT 73.790 197.840 74.020 198.835 ;
        RECT 69.875 197.200 70.195 197.840 ;
        RECT 71.165 197.200 71.485 197.840 ;
        RECT 73.745 197.200 74.065 197.840 ;
        RECT 69.920 195.940 70.150 197.200 ;
        RECT 71.210 195.940 71.440 197.200 ;
        RECT 69.920 195.805 71.485 195.940 ;
        RECT 73.790 195.805 74.020 197.200 ;
        RECT 75.080 197.050 75.310 212.610 ;
        RECT 76.370 212.380 76.600 213.830 ;
        RECT 78.950 212.385 79.180 213.830 ;
        RECT 80.195 212.610 80.515 213.250 ;
        RECT 76.320 211.740 76.640 212.380 ;
        RECT 78.905 211.745 79.225 212.385 ;
        RECT 76.370 210.650 76.600 211.740 ;
        RECT 77.615 210.855 77.935 211.495 ;
        RECT 76.325 210.010 76.645 210.650 ;
        RECT 75.465 207.530 76.215 207.850 ;
        RECT 75.465 201.800 76.215 202.120 ;
        RECT 76.370 199.475 76.600 210.010 ;
        RECT 76.755 207.530 77.505 207.850 ;
        RECT 77.665 207.325 77.895 210.855 ;
        RECT 78.950 210.650 79.180 211.745 ;
        RECT 78.905 210.010 79.225 210.650 ;
        RECT 78.045 207.530 78.795 207.850 ;
        RECT 77.660 202.325 77.895 207.325 ;
        RECT 76.755 201.800 77.505 202.120 ;
        RECT 76.325 198.835 76.645 199.475 ;
        RECT 76.370 197.840 76.600 198.835 ;
        RECT 77.665 198.650 77.895 202.325 ;
        RECT 78.045 201.800 78.795 202.120 ;
        RECT 78.950 199.475 79.180 210.010 ;
        RECT 79.335 207.530 80.085 207.850 ;
        RECT 79.335 201.800 80.085 202.120 ;
        RECT 78.905 198.835 79.225 199.475 ;
        RECT 77.615 198.010 77.935 198.650 ;
        RECT 76.325 197.200 76.645 197.840 ;
        RECT 75.035 196.410 75.355 197.050 ;
        RECT 76.370 195.805 76.600 197.200 ;
        RECT 69.875 195.710 71.485 195.805 ;
        RECT 69.875 195.455 70.195 195.710 ;
        RECT 71.165 195.455 71.485 195.710 ;
        RECT 73.745 195.455 74.065 195.805 ;
        RECT 76.325 195.455 76.645 195.805 ;
        RECT 68.045 195.185 77.220 195.455 ;
        RECT 69.875 195.165 70.195 195.185 ;
        RECT 71.165 195.165 71.485 195.185 ;
        RECT 73.745 195.165 74.065 195.185 ;
        RECT 76.325 195.165 76.645 195.185 ;
        RECT 68.025 194.690 77.265 194.995 ;
        RECT 69.305 194.600 69.625 194.690 ;
        RECT 65.295 192.620 66.045 192.850 ;
        RECT 66.585 192.620 67.335 192.850 ;
        RECT 67.495 192.620 69.010 192.850 ;
        RECT 67.495 192.460 67.725 192.620 ;
        RECT 64.005 191.570 64.755 191.800 ;
        RECT 64.060 191.480 64.700 191.570 ;
        RECT 63.575 190.285 63.895 190.925 ;
        RECT 61.040 189.980 62.560 190.210 ;
        RECT 61.040 189.755 61.270 189.980 ;
        RECT 62.330 189.755 62.560 189.980 ;
        RECT 64.910 189.755 65.140 191.785 ;
        RECT 65.295 191.570 66.045 191.800 ;
        RECT 65.350 191.480 65.990 191.570 ;
        RECT 66.200 190.935 66.430 192.460 ;
        RECT 67.490 192.445 67.725 192.460 ;
        RECT 67.490 191.800 67.720 192.445 ;
        RECT 68.780 191.800 69.010 192.620 ;
        RECT 66.585 191.570 67.335 191.800 ;
        RECT 67.490 191.570 69.010 191.800 ;
        RECT 66.640 191.480 67.280 191.570 ;
        RECT 67.490 191.030 69.010 191.260 ;
        RECT 66.155 190.295 66.475 190.935 ;
        RECT 67.490 190.210 67.720 191.030 ;
        RECT 68.780 190.210 69.010 191.030 ;
        RECT 67.490 189.980 69.010 190.210 ;
        RECT 69.360 190.070 69.590 194.600 ;
        RECT 69.865 194.440 70.185 194.690 ;
        RECT 71.155 194.440 71.475 194.690 ;
        RECT 73.735 194.440 74.055 194.690 ;
        RECT 76.315 194.440 76.635 194.690 ;
        RECT 69.865 194.355 77.495 194.440 ;
        RECT 69.910 194.210 77.495 194.355 ;
        RECT 69.910 193.390 70.140 194.210 ;
        RECT 71.200 193.390 71.430 194.210 ;
        RECT 72.490 193.390 72.720 194.210 ;
        RECT 73.780 193.390 74.010 194.210 ;
        RECT 75.070 193.390 75.300 194.210 ;
        RECT 76.360 193.390 76.590 194.210 ;
        RECT 69.910 193.160 77.515 193.390 ;
        RECT 69.910 192.850 70.140 193.160 ;
        RECT 71.200 192.850 71.430 193.160 ;
        RECT 69.910 192.620 71.430 192.850 ;
        RECT 71.585 192.620 72.335 192.940 ;
        RECT 72.875 192.620 73.625 192.940 ;
        RECT 69.910 191.800 70.140 192.620 ;
        RECT 71.200 191.800 71.430 192.620 ;
        RECT 69.910 191.570 71.430 191.800 ;
        RECT 69.910 191.260 70.140 191.570 ;
        RECT 71.200 191.260 71.430 191.570 ;
        RECT 71.585 191.480 72.335 191.800 ;
        RECT 69.910 191.030 71.430 191.260 ;
        RECT 69.910 190.210 70.140 191.030 ;
        RECT 71.200 190.210 71.430 191.030 ;
        RECT 72.490 190.935 72.720 192.460 ;
        RECT 72.875 191.480 73.625 191.800 ;
        RECT 72.445 190.295 72.765 190.935 ;
        RECT 72.490 190.285 72.720 190.295 ;
        RECT 69.910 190.070 71.430 190.210 ;
        RECT 73.780 190.070 74.010 193.160 ;
        RECT 74.165 192.620 74.915 192.940 ;
        RECT 75.455 192.620 76.205 192.940 ;
        RECT 74.165 191.480 74.915 191.800 ;
        RECT 75.070 190.935 75.300 192.460 ;
        RECT 75.455 191.480 76.205 191.800 ;
        RECT 75.025 190.295 75.345 190.935 ;
        RECT 75.070 190.285 75.300 190.295 ;
        RECT 76.360 190.070 76.590 193.160 ;
        RECT 76.745 192.620 77.495 192.940 ;
        RECT 77.665 192.460 77.895 198.010 ;
        RECT 78.950 197.840 79.180 198.835 ;
        RECT 78.905 197.200 79.225 197.840 ;
        RECT 78.950 195.805 79.180 197.200 ;
        RECT 80.240 197.050 80.470 212.610 ;
        RECT 81.530 212.380 81.760 213.830 ;
        RECT 84.110 212.380 84.340 213.830 ;
        RECT 86.645 213.710 88.210 213.830 ;
        RECT 85.355 212.610 85.675 213.250 ;
        RECT 81.485 211.740 81.805 212.380 ;
        RECT 84.065 211.740 84.385 212.380 ;
        RECT 81.530 210.650 81.760 211.740 ;
        RECT 82.775 210.855 83.095 211.495 ;
        RECT 81.485 210.010 81.805 210.650 ;
        RECT 80.625 207.530 81.375 207.850 ;
        RECT 80.625 201.800 81.375 202.120 ;
        RECT 81.530 199.475 81.760 210.010 ;
        RECT 81.915 207.530 82.665 207.850 ;
        RECT 81.915 201.800 82.665 202.120 ;
        RECT 81.485 198.835 81.805 199.475 ;
        RECT 81.530 197.840 81.760 198.835 ;
        RECT 82.820 198.650 83.050 210.855 ;
        RECT 84.110 210.650 84.340 211.740 ;
        RECT 84.065 210.010 84.385 210.650 ;
        RECT 83.205 207.530 83.955 207.850 ;
        RECT 83.205 201.800 83.955 202.120 ;
        RECT 84.110 199.475 84.340 210.010 ;
        RECT 84.495 207.530 85.245 207.850 ;
        RECT 84.495 201.800 85.245 202.120 ;
        RECT 84.065 198.835 84.385 199.475 ;
        RECT 82.775 198.010 83.095 198.650 ;
        RECT 84.110 197.840 84.340 198.835 ;
        RECT 81.485 197.200 81.805 197.840 ;
        RECT 84.065 197.200 84.385 197.840 ;
        RECT 80.195 196.410 80.515 197.050 ;
        RECT 81.530 195.805 81.760 197.200 ;
        RECT 84.110 195.805 84.340 197.200 ;
        RECT 85.400 197.050 85.630 212.610 ;
        RECT 86.690 212.380 86.920 213.710 ;
        RECT 87.980 212.380 88.210 213.710 ;
        RECT 86.645 211.740 86.965 212.380 ;
        RECT 87.935 211.740 88.255 212.380 ;
        RECT 86.690 210.650 86.920 211.740 ;
        RECT 87.980 210.650 88.210 211.740 ;
        RECT 86.645 210.010 86.965 210.650 ;
        RECT 87.935 210.010 88.255 210.650 ;
        RECT 86.690 208.300 86.920 210.010 ;
        RECT 87.980 208.300 88.210 210.010 ;
        RECT 86.690 208.070 88.210 208.300 ;
        RECT 85.785 207.530 86.535 207.850 ;
        RECT 86.690 207.760 86.920 208.070 ;
        RECT 87.980 207.760 88.210 208.070 ;
        RECT 86.690 207.530 88.210 207.760 ;
        RECT 86.690 202.120 86.920 207.530 ;
        RECT 87.980 202.120 88.210 207.530 ;
        RECT 85.785 201.800 86.535 202.120 ;
        RECT 86.690 201.890 88.210 202.120 ;
        RECT 86.690 201.580 86.920 201.890 ;
        RECT 87.980 201.580 88.210 201.890 ;
        RECT 86.690 201.350 88.210 201.580 ;
        RECT 86.690 199.475 86.920 201.350 ;
        RECT 87.980 199.475 88.210 201.350 ;
        RECT 86.645 198.835 86.965 199.475 ;
        RECT 87.935 198.835 88.255 199.475 ;
        RECT 86.690 197.840 86.920 198.835 ;
        RECT 87.980 197.840 88.210 198.835 ;
        RECT 86.645 197.200 86.965 197.840 ;
        RECT 87.935 197.200 88.255 197.840 ;
        RECT 85.360 196.410 85.680 197.050 ;
        RECT 86.690 195.940 86.920 197.200 ;
        RECT 87.980 195.940 88.210 197.200 ;
        RECT 86.645 195.805 88.210 195.940 ;
        RECT 78.905 195.445 79.225 195.805 ;
        RECT 81.485 195.445 81.805 195.805 ;
        RECT 84.065 195.445 84.385 195.805 ;
        RECT 86.645 195.710 88.250 195.805 ;
        RECT 86.645 195.445 86.965 195.710 ;
        RECT 87.930 195.445 88.250 195.710 ;
        RECT 78.200 195.170 88.250 195.445 ;
        RECT 88.500 195.220 88.820 214.180 ;
        RECT 89.100 213.710 90.620 214.180 ;
        RECT 89.100 213.505 89.325 213.710 ;
        RECT 89.100 212.380 89.330 213.505 ;
        RECT 90.390 212.380 90.620 213.710 ;
        RECT 92.970 212.380 93.200 214.180 ;
        RECT 95.550 212.380 95.780 214.180 ;
        RECT 98.130 213.710 99.650 214.180 ;
        RECT 98.130 212.380 98.360 213.710 ;
        RECT 99.420 212.380 99.650 213.710 ;
        RECT 89.055 211.740 89.375 212.380 ;
        RECT 90.345 211.740 90.665 212.380 ;
        RECT 92.925 211.740 93.245 212.380 ;
        RECT 95.505 211.740 95.825 212.380 ;
        RECT 98.085 211.740 98.405 212.380 ;
        RECT 99.375 211.740 99.695 212.380 ;
        RECT 89.100 210.650 89.330 211.740 ;
        RECT 90.390 210.650 90.620 211.740 ;
        RECT 92.970 210.650 93.200 211.740 ;
        RECT 89.055 210.010 89.375 210.650 ;
        RECT 90.345 210.010 90.665 210.650 ;
        RECT 92.925 210.010 93.245 210.650 ;
        RECT 89.100 208.300 89.330 210.010 ;
        RECT 90.390 208.300 90.620 210.010 ;
        RECT 91.635 208.535 91.955 209.870 ;
        RECT 89.100 208.070 90.620 208.300 ;
        RECT 89.100 207.760 89.330 208.070 ;
        RECT 90.390 207.760 90.620 208.070 ;
        RECT 90.830 207.760 91.470 207.850 ;
        RECT 89.100 207.530 90.620 207.760 ;
        RECT 90.775 207.530 91.525 207.760 ;
        RECT 89.100 202.120 89.330 207.530 ;
        RECT 90.390 202.120 90.620 207.530 ;
        RECT 89.100 201.890 90.620 202.120 ;
        RECT 90.775 201.890 91.525 202.120 ;
        RECT 89.100 201.140 89.330 201.890 ;
        RECT 89.055 199.630 89.375 200.910 ;
        RECT 78.905 195.165 79.225 195.170 ;
        RECT 81.485 195.165 81.805 195.170 ;
        RECT 84.065 195.165 84.385 195.170 ;
        RECT 86.645 195.165 86.965 195.170 ;
        RECT 87.930 195.165 88.250 195.170 ;
        RECT 78.175 194.700 88.075 194.995 ;
        RECT 78.900 194.440 79.220 194.700 ;
        RECT 81.475 194.440 81.795 194.700 ;
        RECT 84.055 194.440 84.375 194.700 ;
        RECT 85.345 194.440 85.665 194.700 ;
        RECT 78.035 194.355 85.665 194.440 ;
        RECT 78.035 194.210 85.620 194.355 ;
        RECT 78.940 193.390 79.170 194.210 ;
        RECT 80.230 193.390 80.460 194.210 ;
        RECT 81.520 193.390 81.750 194.210 ;
        RECT 82.810 193.390 83.040 194.210 ;
        RECT 84.100 193.390 84.330 194.210 ;
        RECT 85.390 193.390 85.620 194.210 ;
        RECT 78.035 193.160 85.620 193.390 ;
        RECT 78.035 192.620 78.785 192.940 ;
        RECT 77.650 191.960 77.895 192.460 ;
        RECT 76.745 191.480 77.495 191.800 ;
        RECT 67.490 189.755 67.720 189.980 ;
        RECT 68.780 189.755 69.010 189.980 ;
        RECT 69.305 189.755 69.625 190.070 ;
        RECT 69.855 189.980 71.465 190.070 ;
        RECT 69.855 189.755 70.175 189.980 ;
        RECT 71.145 189.755 71.465 189.980 ;
        RECT 73.725 189.755 74.045 190.070 ;
        RECT 76.305 189.755 76.625 190.070 ;
        RECT 60.395 189.430 77.300 189.755 ;
        RECT 76.360 189.420 76.590 189.430 ;
        RECT 61.155 189.285 61.475 189.290 ;
        RECT 69.020 189.285 69.340 189.290 ;
        RECT 71.150 189.285 71.470 189.290 ;
        RECT 73.730 189.285 74.050 189.290 ;
        RECT 74.785 189.285 75.330 189.290 ;
        RECT 61.155 188.945 75.900 189.285 ;
        RECT 61.155 182.595 61.475 188.945 ;
        RECT 64.290 188.645 64.610 188.945 ;
        RECT 68.785 188.650 69.575 188.945 ;
        RECT 71.150 188.650 71.470 188.945 ;
        RECT 73.730 188.650 74.050 188.945 ;
        RECT 75.010 188.650 75.330 188.945 ;
        RECT 61.775 187.960 63.295 188.190 ;
        RECT 61.775 187.050 62.005 187.960 ;
        RECT 63.065 187.050 63.295 187.960 ;
        RECT 61.775 186.820 63.295 187.050 ;
        RECT 61.775 186.510 62.005 186.820 ;
        RECT 63.065 186.510 63.295 186.820 ;
        RECT 61.775 186.280 63.295 186.510 ;
        RECT 63.450 186.280 64.200 186.745 ;
        RECT 61.775 185.370 62.005 186.280 ;
        RECT 63.065 185.370 63.295 186.280 ;
        RECT 61.775 185.140 63.295 185.370 ;
        RECT 61.775 184.830 62.005 185.140 ;
        RECT 63.065 184.830 63.295 185.140 ;
        RECT 63.450 185.005 64.200 185.370 ;
        RECT 61.775 184.600 63.295 184.830 ;
        RECT 61.775 183.690 62.005 184.600 ;
        RECT 63.065 183.690 63.295 184.600 ;
        RECT 61.775 183.460 63.295 183.690 ;
        RECT 60.595 182.340 60.915 182.395 ;
        RECT 60.595 182.050 61.640 182.340 ;
        RECT 62.285 182.335 62.905 182.345 ;
        RECT 62.275 182.065 62.905 182.335 ;
        RECT 62.285 182.055 62.905 182.065 ;
        RECT 60.595 176.570 60.915 182.050 ;
        RECT 61.225 181.800 61.455 182.050 ;
        RECT 62.515 181.800 62.755 182.055 ;
        RECT 61.225 181.570 62.755 181.800 ;
        RECT 61.225 180.580 61.455 181.570 ;
        RECT 62.515 180.580 62.755 181.570 ;
        RECT 63.065 181.050 63.295 183.460 ;
        RECT 64.355 182.830 64.585 188.645 ;
        RECT 67.440 187.635 67.760 188.275 ;
        RECT 64.740 186.280 65.885 186.745 ;
        RECT 65.645 185.370 65.885 186.280 ;
        RECT 64.740 185.005 65.885 185.370 ;
        RECT 64.175 182.540 64.765 182.830 ;
        RECT 61.225 180.350 62.755 180.580 ;
        RECT 61.225 180.040 61.455 180.350 ;
        RECT 62.515 180.040 62.755 180.350 ;
        RECT 62.900 180.270 63.655 181.050 ;
        RECT 61.225 179.810 62.755 180.040 ;
        RECT 61.225 178.820 61.455 179.810 ;
        RECT 62.515 178.830 62.755 179.810 ;
        RECT 62.900 179.810 63.650 180.130 ;
        RECT 62.515 178.820 62.745 178.830 ;
        RECT 61.225 178.590 62.745 178.820 ;
        RECT 61.225 178.280 61.455 178.590 ;
        RECT 62.515 178.280 62.745 178.590 ;
        RECT 62.900 178.820 63.145 179.810 ;
        RECT 63.395 178.820 63.650 179.810 ;
        RECT 62.900 178.500 63.650 178.820 ;
        RECT 63.800 180.100 64.120 182.070 ;
        RECT 65.095 180.100 65.325 182.020 ;
        RECT 63.800 179.780 65.325 180.100 ;
        RECT 63.800 178.850 64.120 179.780 ;
        RECT 65.095 178.850 65.325 179.780 ;
        RECT 63.800 178.530 65.325 178.850 ;
        RECT 61.225 178.050 62.745 178.280 ;
        RECT 61.225 177.255 61.455 178.050 ;
        RECT 61.165 177.060 61.485 177.255 ;
        RECT 62.515 177.220 62.745 178.050 ;
        RECT 62.900 177.580 63.650 178.360 ;
        RECT 62.470 177.060 62.790 177.220 ;
        RECT 61.165 176.830 62.790 177.060 ;
        RECT 61.165 176.570 61.485 176.830 ;
        RECT 62.470 176.575 62.790 176.830 ;
        RECT 60.595 176.280 61.670 176.570 ;
        RECT 62.325 176.310 62.915 176.575 ;
        RECT 60.595 174.845 60.915 176.280 ;
        RECT 63.140 175.350 63.460 177.580 ;
        RECT 63.800 176.020 64.120 178.530 ;
        RECT 65.095 176.340 65.325 178.530 ;
        RECT 65.645 176.515 65.885 185.005 ;
        RECT 67.495 182.740 67.725 187.635 ;
        RECT 67.945 186.725 68.585 186.745 ;
        RECT 67.880 186.495 68.630 186.725 ;
        RECT 67.945 186.425 68.585 186.495 ;
        RECT 67.880 185.005 68.630 185.325 ;
        RECT 68.785 182.845 69.015 188.650 ;
        RECT 69.345 188.285 69.575 188.650 ;
        RECT 71.195 188.410 71.425 188.650 ;
        RECT 73.775 188.410 74.005 188.650 ;
        RECT 75.065 188.410 75.295 188.650 ;
        RECT 71.195 188.285 75.295 188.410 ;
        RECT 69.345 188.180 75.295 188.285 ;
        RECT 69.345 188.055 71.425 188.180 ;
        RECT 69.345 187.180 69.575 188.055 ;
        RECT 70.635 187.180 70.865 188.055 ;
        RECT 71.195 187.180 71.425 188.055 ;
        RECT 72.485 187.180 72.715 188.180 ;
        RECT 73.775 187.180 74.005 188.180 ;
        RECT 75.065 187.180 75.295 188.180 ;
        RECT 69.345 186.915 75.295 187.180 ;
        RECT 69.345 182.845 69.575 186.915 ;
        RECT 70.635 185.670 71.045 186.170 ;
        RECT 66.885 182.085 67.235 182.345 ;
        RECT 67.440 182.100 67.760 182.740 ;
        RECT 68.200 182.100 68.520 182.740 ;
        RECT 68.785 182.555 69.575 182.845 ;
        RECT 66.090 179.960 66.730 180.080 ;
        RECT 66.040 179.730 66.790 179.960 ;
        RECT 66.040 178.680 66.790 178.910 ;
        RECT 66.105 178.560 66.745 178.680 ;
        RECT 66.945 177.270 67.175 182.085 ;
        RECT 66.910 176.950 67.230 177.270 ;
        RECT 66.905 176.565 67.225 176.950 ;
        RECT 65.050 176.020 65.370 176.340 ;
        RECT 66.755 176.315 67.345 176.565 ;
        RECT 68.235 176.515 68.465 182.100 ;
        RECT 69.330 182.060 69.950 182.350 ;
        RECT 68.675 179.960 69.315 180.030 ;
        RECT 68.620 179.730 69.370 179.960 ;
        RECT 68.675 179.710 69.315 179.730 ;
        RECT 68.670 178.910 69.310 178.950 ;
        RECT 68.620 178.680 69.370 178.910 ;
        RECT 68.670 178.630 69.310 178.680 ;
        RECT 69.525 177.270 69.755 182.060 ;
        RECT 70.815 180.030 71.045 185.670 ;
        RECT 71.195 182.890 71.425 186.915 ;
        RECT 73.775 186.640 74.005 186.915 ;
        RECT 75.065 186.640 75.295 186.915 ;
        RECT 72.875 186.410 73.615 186.640 ;
        RECT 71.780 186.040 72.715 186.205 ;
        RECT 71.775 185.615 72.715 186.040 ;
        RECT 71.775 183.845 72.415 185.615 ;
        RECT 73.125 185.410 73.355 186.410 ;
        RECT 73.775 186.405 75.295 186.640 ;
        RECT 73.775 185.415 74.005 186.405 ;
        RECT 75.065 185.415 75.295 186.405 ;
        RECT 72.875 184.630 73.615 185.410 ;
        RECT 73.775 185.180 75.295 185.415 ;
        RECT 73.775 184.875 74.005 185.180 ;
        RECT 75.065 184.875 75.295 185.180 ;
        RECT 73.775 184.640 75.295 184.875 ;
        RECT 71.195 182.540 71.530 182.890 ;
        RECT 69.960 179.960 71.045 180.030 ;
        RECT 69.910 179.730 71.045 179.960 ;
        RECT 69.960 179.710 71.045 179.730 ;
        RECT 70.815 178.950 71.045 179.710 ;
        RECT 69.965 178.910 71.045 178.950 ;
        RECT 69.910 178.680 71.045 178.910 ;
        RECT 69.965 178.630 71.045 178.680 ;
        RECT 69.480 176.565 69.800 177.270 ;
        RECT 69.345 176.310 69.935 176.565 ;
        RECT 70.815 176.515 71.045 178.630 ;
        RECT 71.775 176.345 71.990 183.845 ;
        RECT 72.180 176.345 72.415 183.845 ;
        RECT 72.875 183.710 73.615 184.490 ;
        RECT 73.125 182.780 73.355 183.710 ;
        RECT 73.775 183.640 74.005 184.640 ;
        RECT 75.065 183.640 75.295 184.640 ;
        RECT 73.775 183.405 75.295 183.640 ;
        RECT 73.775 182.825 74.005 183.405 ;
        RECT 75.065 182.825 75.295 183.405 ;
        RECT 75.580 182.825 75.900 188.945 ;
        RECT 77.655 186.695 77.895 191.960 ;
        RECT 78.035 191.480 78.785 191.800 ;
        RECT 78.940 190.070 79.170 193.160 ;
        RECT 79.325 192.620 80.075 192.940 ;
        RECT 80.615 192.620 81.365 192.940 ;
        RECT 79.325 191.480 80.075 191.800 ;
        RECT 80.230 190.935 80.460 192.460 ;
        RECT 80.615 191.480 81.365 191.800 ;
        RECT 80.185 190.295 80.505 190.935 ;
        RECT 80.230 190.285 80.460 190.295 ;
        RECT 81.520 190.070 81.750 193.160 ;
        RECT 81.905 192.620 82.655 192.940 ;
        RECT 83.195 192.620 83.945 192.940 ;
        RECT 84.100 192.850 84.330 193.160 ;
        RECT 85.390 192.850 85.620 193.160 ;
        RECT 84.100 192.620 85.620 192.850 ;
        RECT 81.905 191.480 82.655 191.800 ;
        RECT 82.810 190.935 83.040 192.460 ;
        RECT 84.100 191.800 84.330 192.620 ;
        RECT 85.390 191.800 85.620 192.620 ;
        RECT 83.195 191.480 83.945 191.800 ;
        RECT 84.100 191.570 85.620 191.800 ;
        RECT 84.100 191.260 84.330 191.570 ;
        RECT 85.390 191.260 85.620 191.570 ;
        RECT 84.100 191.030 85.620 191.260 ;
        RECT 82.765 190.295 83.085 190.935 ;
        RECT 82.810 190.285 83.040 190.295 ;
        RECT 84.100 190.210 84.330 191.030 ;
        RECT 85.390 190.210 85.620 191.030 ;
        RECT 84.100 190.070 85.620 190.210 ;
        RECT 78.890 189.755 79.210 190.070 ;
        RECT 81.470 189.755 81.790 190.070 ;
        RECT 84.050 189.980 85.660 190.070 ;
        RECT 84.050 189.755 84.370 189.980 ;
        RECT 85.340 189.755 85.660 189.980 ;
        RECT 85.970 189.755 86.200 194.700 ;
        RECT 86.465 194.440 86.785 194.700 ;
        RECT 87.755 194.440 88.075 194.700 ;
        RECT 86.465 194.355 88.075 194.440 ;
        RECT 86.510 194.210 88.030 194.355 ;
        RECT 86.510 193.390 86.740 194.210 ;
        RECT 87.800 193.390 88.030 194.210 ;
        RECT 86.510 193.160 88.030 193.390 ;
        RECT 86.510 192.850 86.740 193.160 ;
        RECT 87.800 192.850 88.030 193.160 ;
        RECT 88.240 192.850 88.880 192.940 ;
        RECT 86.510 192.620 88.030 192.850 ;
        RECT 88.185 192.620 88.935 192.850 ;
        RECT 86.510 191.800 86.740 192.620 ;
        RECT 87.800 191.800 88.030 192.620 ;
        RECT 89.090 192.415 89.330 199.630 ;
        RECT 90.390 199.475 90.620 201.890 ;
        RECT 90.830 201.800 91.470 201.890 ;
        RECT 91.680 200.910 91.910 208.535 ;
        RECT 92.120 207.760 92.760 207.850 ;
        RECT 92.065 207.530 92.815 207.760 ;
        RECT 92.065 201.890 92.815 202.120 ;
        RECT 92.120 201.800 92.760 201.890 ;
        RECT 91.635 199.630 91.955 200.910 ;
        RECT 92.970 199.475 93.200 210.010 ;
        RECT 93.410 207.760 94.050 211.495 ;
        RECT 94.260 209.815 94.490 210.095 ;
        RECT 94.215 208.535 94.535 209.815 ;
        RECT 93.355 207.530 94.105 207.760 ;
        RECT 93.355 201.890 94.105 202.120 ;
        RECT 90.345 198.835 90.665 199.475 ;
        RECT 92.925 198.835 93.245 199.475 ;
        RECT 90.390 197.840 90.620 198.835 ;
        RECT 92.970 197.840 93.200 198.835 ;
        RECT 93.410 198.010 94.050 201.890 ;
        RECT 94.260 200.915 94.490 208.535 ;
        RECT 94.700 207.760 95.340 211.495 ;
        RECT 95.550 210.650 95.780 211.740 ;
        RECT 98.130 210.650 98.360 211.740 ;
        RECT 99.420 210.650 99.650 211.740 ;
        RECT 95.505 210.010 95.825 210.650 ;
        RECT 94.645 207.530 95.395 207.760 ;
        RECT 94.645 201.890 95.395 202.120 ;
        RECT 94.700 201.790 95.340 201.890 ;
        RECT 94.215 199.630 94.535 200.915 ;
        RECT 90.345 197.200 90.665 197.840 ;
        RECT 92.925 197.200 93.245 197.840 ;
        RECT 90.390 195.805 90.620 197.200 ;
        RECT 91.670 197.050 91.900 197.100 ;
        RECT 91.635 196.410 91.955 197.050 ;
        RECT 90.340 195.165 90.660 195.805 ;
        RECT 89.470 194.695 91.520 194.995 ;
        RECT 90.335 194.355 90.655 194.695 ;
        RECT 89.530 192.850 90.170 192.940 ;
        RECT 89.475 192.620 90.225 192.850 ;
        RECT 89.090 191.960 89.320 192.415 ;
        RECT 86.510 191.570 88.030 191.800 ;
        RECT 88.185 191.570 88.935 191.800 ;
        RECT 89.475 191.570 90.225 191.800 ;
        RECT 86.510 191.260 86.740 191.570 ;
        RECT 87.800 191.260 88.030 191.570 ;
        RECT 88.240 191.480 88.880 191.570 ;
        RECT 89.530 191.480 90.170 191.570 ;
        RECT 86.510 191.030 88.030 191.260 ;
        RECT 86.510 190.210 86.740 191.030 ;
        RECT 87.800 190.210 88.030 191.030 ;
        RECT 86.510 190.070 88.030 190.210 ;
        RECT 90.380 190.070 90.610 194.355 ;
        RECT 90.820 192.850 91.460 192.940 ;
        RECT 91.670 192.850 91.900 196.410 ;
        RECT 92.970 195.800 93.200 197.200 ;
        RECT 92.920 195.160 93.240 195.800 ;
        RECT 92.060 194.695 94.110 194.995 ;
        RECT 92.920 194.355 93.240 194.695 ;
        RECT 92.110 192.850 92.750 192.940 ;
        RECT 90.765 192.620 92.805 192.850 ;
        RECT 91.670 191.800 91.900 192.620 ;
        RECT 90.765 191.570 92.805 191.800 ;
        RECT 90.820 191.480 91.460 191.570 ;
        RECT 92.110 191.480 92.750 191.570 ;
        RECT 92.960 190.070 93.190 194.355 ;
        RECT 93.400 192.850 94.040 192.940 ;
        RECT 93.345 192.620 94.095 192.850 ;
        RECT 94.250 192.430 94.490 199.630 ;
        RECT 94.700 198.650 95.335 201.790 ;
        RECT 95.550 199.475 95.780 210.010 ;
        RECT 96.840 209.815 97.070 210.120 ;
        RECT 98.085 210.010 98.405 210.650 ;
        RECT 99.375 210.010 99.695 210.650 ;
        RECT 96.795 208.535 97.115 209.815 ;
        RECT 95.990 207.760 96.630 207.850 ;
        RECT 95.935 207.530 96.685 207.760 ;
        RECT 95.935 201.890 96.685 202.120 ;
        RECT 95.990 201.800 96.630 201.890 ;
        RECT 96.840 200.910 97.070 208.535 ;
        RECT 98.130 208.300 98.360 210.010 ;
        RECT 99.420 208.300 99.650 210.010 ;
        RECT 98.130 208.070 99.650 208.300 ;
        RECT 97.280 207.760 97.920 207.850 ;
        RECT 98.130 207.760 98.360 208.070 ;
        RECT 99.420 207.760 99.650 208.070 ;
        RECT 97.225 207.530 97.975 207.760 ;
        RECT 98.130 207.530 99.650 207.760 ;
        RECT 98.130 202.120 98.360 207.530 ;
        RECT 99.420 202.120 99.650 207.530 ;
        RECT 97.225 201.890 97.975 202.120 ;
        RECT 98.130 201.890 99.650 202.120 ;
        RECT 97.280 201.800 97.920 201.890 ;
        RECT 96.795 199.630 97.115 200.910 ;
        RECT 98.130 199.475 98.360 201.890 ;
        RECT 99.420 201.185 99.650 201.890 ;
        RECT 95.505 198.835 95.825 199.475 ;
        RECT 98.075 198.835 98.395 199.475 ;
        RECT 94.695 198.010 95.335 198.650 ;
        RECT 95.550 197.840 95.780 198.835 ;
        RECT 98.130 197.840 98.360 198.835 ;
        RECT 95.505 197.200 95.825 197.840 ;
        RECT 98.075 197.200 98.395 197.840 ;
        RECT 95.550 195.800 95.780 197.200 ;
        RECT 98.130 195.805 98.360 197.200 ;
        RECT 95.505 195.160 95.825 195.800 ;
        RECT 98.075 195.165 98.395 195.805 ;
        RECT 94.650 194.700 97.705 195.000 ;
        RECT 95.495 194.495 95.815 194.700 ;
        RECT 96.780 194.495 97.100 194.700 ;
        RECT 95.495 194.355 97.100 194.495 ;
        RECT 95.540 194.210 97.060 194.355 ;
        RECT 95.540 193.390 95.770 194.210 ;
        RECT 96.830 193.390 97.060 194.210 ;
        RECT 95.540 193.160 97.060 193.390 ;
        RECT 94.690 192.850 95.330 192.940 ;
        RECT 95.540 192.850 95.770 193.160 ;
        RECT 96.830 192.850 97.060 193.160 ;
        RECT 94.635 192.620 95.385 192.850 ;
        RECT 95.540 192.620 97.060 192.850 ;
        RECT 94.250 191.960 94.480 192.430 ;
        RECT 95.540 191.800 95.770 192.620 ;
        RECT 96.830 191.800 97.060 192.620 ;
        RECT 93.345 191.570 94.095 191.800 ;
        RECT 94.635 191.570 95.385 191.800 ;
        RECT 95.540 191.570 97.060 191.800 ;
        RECT 93.400 191.480 94.040 191.570 ;
        RECT 94.690 191.480 95.330 191.570 ;
        RECT 95.540 191.260 95.770 191.570 ;
        RECT 96.830 191.260 97.060 191.570 ;
        RECT 95.540 191.030 97.060 191.260 ;
        RECT 95.540 190.210 95.770 191.030 ;
        RECT 96.830 190.210 97.060 191.030 ;
        RECT 95.540 190.070 97.060 190.210 ;
        RECT 86.465 189.980 88.070 190.070 ;
        RECT 86.465 189.755 86.785 189.980 ;
        RECT 87.750 189.755 88.070 189.980 ;
        RECT 90.330 189.755 90.650 190.070 ;
        RECT 92.910 189.755 93.230 190.070 ;
        RECT 95.495 189.980 97.105 190.070 ;
        RECT 95.495 189.755 95.815 189.980 ;
        RECT 96.785 189.755 97.105 189.980 ;
        RECT 78.105 189.435 97.105 189.755 ;
        RECT 97.345 189.435 97.705 194.700 ;
        RECT 78.890 189.430 79.210 189.435 ;
        RECT 77.610 186.055 77.930 186.695 ;
        RECT 72.610 182.140 72.930 182.780 ;
        RECT 73.075 182.140 73.395 182.780 ;
        RECT 73.670 182.535 74.260 182.825 ;
        RECT 74.900 182.535 75.900 182.825 ;
        RECT 75.580 182.510 75.900 182.535 ;
        RECT 72.665 179.070 72.895 182.140 ;
        RECT 73.760 182.055 74.380 182.345 ;
        RECT 75.040 182.070 76.085 182.360 ;
        RECT 73.925 181.720 74.185 182.055 ;
        RECT 75.245 181.720 75.475 182.070 ;
        RECT 73.050 181.490 75.475 181.720 ;
        RECT 73.925 180.670 74.185 181.490 ;
        RECT 75.245 180.670 75.475 181.490 ;
        RECT 73.050 180.440 75.475 180.670 ;
        RECT 73.110 179.710 73.750 180.030 ;
        RECT 73.925 179.960 74.185 180.440 ;
        RECT 75.245 179.960 75.475 180.440 ;
        RECT 73.925 179.730 75.475 179.960 ;
        RECT 71.775 176.025 72.415 176.345 ;
        RECT 72.635 176.345 72.895 179.070 ;
        RECT 73.105 178.630 73.745 178.950 ;
        RECT 73.925 178.910 74.185 179.730 ;
        RECT 75.245 178.910 75.475 179.730 ;
        RECT 73.925 178.680 75.475 178.910 ;
        RECT 73.925 178.200 74.185 178.680 ;
        RECT 75.245 178.200 75.475 178.680 ;
        RECT 73.050 177.970 75.475 178.200 ;
        RECT 73.925 177.270 74.185 177.970 ;
        RECT 75.245 177.285 75.475 177.970 ;
        RECT 73.895 177.150 74.215 177.270 ;
        RECT 75.200 177.150 75.520 177.285 ;
        RECT 73.050 176.965 75.520 177.150 ;
        RECT 73.050 176.920 75.525 176.965 ;
        RECT 73.895 176.575 74.215 176.920 ;
        RECT 75.205 176.585 75.525 176.920 ;
        RECT 75.765 176.585 76.085 182.070 ;
        RECT 72.635 176.025 72.955 176.345 ;
        RECT 73.755 176.285 74.345 176.575 ;
        RECT 75.045 176.295 76.085 176.585 ;
        RECT 80.700 176.550 81.020 189.435 ;
        RECT 81.470 189.430 81.790 189.435 ;
        RECT 84.050 189.430 84.370 189.435 ;
        RECT 85.340 189.430 85.660 189.435 ;
        RECT 86.465 189.430 86.785 189.435 ;
        RECT 87.750 189.430 88.070 189.435 ;
        RECT 90.330 189.430 90.650 189.435 ;
        RECT 92.910 189.430 93.230 189.435 ;
        RECT 95.495 189.430 95.815 189.435 ;
        RECT 96.785 189.430 97.105 189.435 ;
        RECT 98.535 186.865 99.595 200.915 ;
        RECT 99.915 195.165 100.675 214.180 ;
        RECT 101.000 213.710 102.520 214.180 ;
        RECT 102.730 213.940 103.370 214.020 ;
        RECT 104.020 213.940 104.660 214.020 ;
        RECT 102.675 213.710 103.425 213.940 ;
        RECT 103.965 213.710 104.715 213.940 ;
        RECT 101.000 212.380 101.230 213.710 ;
        RECT 102.290 212.380 102.520 213.710 ;
        RECT 102.730 213.700 103.370 213.710 ;
        RECT 104.020 213.700 104.660 213.710 ;
        RECT 100.955 211.740 101.275 212.380 ;
        RECT 102.245 211.740 102.565 212.380 ;
        RECT 101.000 210.650 101.230 211.740 ;
        RECT 102.290 210.650 102.520 211.740 ;
        RECT 100.955 210.010 101.275 210.650 ;
        RECT 102.245 210.010 102.565 210.650 ;
        RECT 101.000 199.475 101.230 210.010 ;
        RECT 102.290 199.475 102.520 210.010 ;
        RECT 100.955 198.835 101.275 199.475 ;
        RECT 102.245 198.835 102.565 199.475 ;
        RECT 101.000 197.840 101.230 198.835 ;
        RECT 102.290 197.840 102.520 198.835 ;
        RECT 100.955 197.200 101.275 197.840 ;
        RECT 102.245 197.200 102.565 197.840 ;
        RECT 101.000 195.805 101.230 197.200 ;
        RECT 102.290 195.805 102.520 197.200 ;
        RECT 100.955 195.165 101.275 195.805 ;
        RECT 102.245 195.165 102.565 195.805 ;
        RECT 101.000 189.290 101.230 195.165 ;
        RECT 102.290 189.290 102.520 195.165 ;
        RECT 100.955 188.650 101.275 189.290 ;
        RECT 102.245 188.650 102.565 189.290 ;
        RECT 90.400 186.450 91.040 186.695 ;
        RECT 89.170 186.200 91.275 186.450 ;
        RECT 90.400 186.055 91.040 186.200 ;
        RECT 95.545 185.640 99.595 186.865 ;
        RECT 88.640 184.115 98.340 184.210 ;
        RECT 88.630 184.085 98.350 184.115 ;
        RECT 87.980 183.825 98.840 184.085 ;
        RECT 96.745 182.510 98.025 182.540 ;
        RECT 88.300 182.260 90.405 182.510 ;
        RECT 96.425 182.260 98.530 182.510 ;
        RECT 89.905 178.655 90.225 182.260 ;
        RECT 96.745 182.220 98.025 182.260 ;
        RECT 88.795 178.345 90.890 178.655 ;
        RECT 88.510 177.060 98.360 177.115 ;
        RECT 88.500 176.830 98.370 177.060 ;
        RECT 88.510 176.810 98.360 176.830 ;
        RECT 65.105 175.350 65.425 175.410 ;
        RECT 71.270 175.350 71.590 175.390 ;
        RECT 61.360 175.100 63.465 175.350 ;
        RECT 65.105 175.100 67.210 175.350 ;
        RECT 69.485 175.100 71.590 175.350 ;
        RECT 65.105 175.090 65.425 175.100 ;
        RECT 71.270 175.070 71.590 175.100 ;
        RECT 73.230 175.350 73.550 175.385 ;
        RECT 73.230 175.100 75.335 175.350 ;
        RECT 73.230 175.065 73.550 175.100 ;
        RECT 75.765 174.810 76.085 176.295 ;
        RECT 101.000 167.300 101.230 188.650 ;
        RECT 102.290 167.300 102.520 188.650 ;
        RECT 103.580 183.020 103.810 213.505 ;
        RECT 104.870 212.380 105.100 214.180 ;
        RECT 105.310 213.940 105.950 214.020 ;
        RECT 106.600 213.940 107.240 214.020 ;
        RECT 105.255 213.710 106.005 213.940 ;
        RECT 106.545 213.710 107.295 213.940 ;
        RECT 105.310 213.700 105.950 213.710 ;
        RECT 106.600 213.700 107.240 213.710 ;
        RECT 104.825 211.740 105.145 212.380 ;
        RECT 104.870 210.650 105.100 211.740 ;
        RECT 104.825 210.010 105.145 210.650 ;
        RECT 104.870 199.475 105.100 210.010 ;
        RECT 104.825 198.835 105.145 199.475 ;
        RECT 104.870 197.840 105.100 198.835 ;
        RECT 104.825 197.200 105.145 197.840 ;
        RECT 104.870 195.805 105.100 197.200 ;
        RECT 104.825 195.165 105.145 195.805 ;
        RECT 104.870 189.290 105.100 195.165 ;
        RECT 104.825 188.650 105.145 189.290 ;
        RECT 103.535 181.965 103.855 183.020 ;
        RECT 103.515 179.695 103.875 181.965 ;
        RECT 103.580 167.505 103.810 179.695 ;
        RECT 102.730 167.300 103.370 167.390 ;
        RECT 104.020 167.300 104.660 167.390 ;
        RECT 101.000 166.835 102.520 167.300 ;
        RECT 102.675 167.070 103.425 167.300 ;
        RECT 103.965 167.070 104.715 167.300 ;
        RECT 104.870 166.835 105.100 188.650 ;
        RECT 106.160 183.020 106.390 213.505 ;
        RECT 107.450 212.380 107.680 214.180 ;
        RECT 107.890 213.940 108.530 214.020 ;
        RECT 109.180 213.940 109.820 214.020 ;
        RECT 107.835 213.710 108.585 213.940 ;
        RECT 109.125 213.710 109.875 213.940 ;
        RECT 107.890 213.700 108.530 213.710 ;
        RECT 109.180 213.700 109.820 213.710 ;
        RECT 107.405 211.740 107.725 212.380 ;
        RECT 107.450 210.650 107.680 211.740 ;
        RECT 107.405 210.010 107.725 210.650 ;
        RECT 107.450 199.475 107.680 210.010 ;
        RECT 107.405 198.835 107.725 199.475 ;
        RECT 107.450 197.840 107.680 198.835 ;
        RECT 107.405 197.200 107.725 197.840 ;
        RECT 107.450 195.805 107.680 197.200 ;
        RECT 107.405 195.165 107.725 195.805 ;
        RECT 107.450 189.290 107.680 195.165 ;
        RECT 107.405 188.650 107.725 189.290 ;
        RECT 106.110 181.795 106.430 183.020 ;
        RECT 106.090 179.630 106.450 181.795 ;
        RECT 106.160 167.505 106.390 179.630 ;
        RECT 105.310 167.300 105.950 167.390 ;
        RECT 106.600 167.300 107.240 167.390 ;
        RECT 105.255 167.070 106.005 167.300 ;
        RECT 106.545 167.070 107.295 167.300 ;
        RECT 107.450 166.835 107.680 188.650 ;
        RECT 108.740 183.020 108.970 213.505 ;
        RECT 110.030 212.380 110.260 214.180 ;
        RECT 110.470 213.940 111.110 214.020 ;
        RECT 111.760 213.940 112.400 214.020 ;
        RECT 110.415 213.710 111.165 213.940 ;
        RECT 111.705 213.710 112.455 213.940 ;
        RECT 110.470 213.700 111.110 213.710 ;
        RECT 111.760 213.700 112.400 213.710 ;
        RECT 109.985 211.740 110.305 212.380 ;
        RECT 110.030 210.650 110.260 211.740 ;
        RECT 109.985 210.010 110.305 210.650 ;
        RECT 110.030 199.475 110.260 210.010 ;
        RECT 109.985 198.835 110.305 199.475 ;
        RECT 110.030 197.840 110.260 198.835 ;
        RECT 109.985 197.200 110.305 197.840 ;
        RECT 110.030 195.805 110.260 197.200 ;
        RECT 109.985 195.165 110.305 195.805 ;
        RECT 110.030 189.290 110.260 195.165 ;
        RECT 109.985 188.650 110.305 189.290 ;
        RECT 108.695 181.775 109.015 183.020 ;
        RECT 108.675 179.635 109.035 181.775 ;
        RECT 108.740 167.505 108.970 179.635 ;
        RECT 107.890 167.300 108.530 167.390 ;
        RECT 109.175 167.300 109.815 167.390 ;
        RECT 107.835 167.070 108.585 167.300 ;
        RECT 109.125 167.070 109.875 167.300 ;
        RECT 110.030 166.835 110.260 188.650 ;
        RECT 111.320 183.020 111.550 213.505 ;
        RECT 112.610 212.380 112.840 214.180 ;
        RECT 113.050 213.940 113.690 214.020 ;
        RECT 114.340 213.940 114.980 214.020 ;
        RECT 112.995 213.710 113.745 213.940 ;
        RECT 114.285 213.710 115.035 213.940 ;
        RECT 113.050 213.700 113.690 213.710 ;
        RECT 114.340 213.700 114.980 213.710 ;
        RECT 112.565 211.740 112.885 212.380 ;
        RECT 112.610 210.650 112.840 211.740 ;
        RECT 112.565 210.010 112.885 210.650 ;
        RECT 112.610 199.475 112.840 210.010 ;
        RECT 112.565 198.835 112.885 199.475 ;
        RECT 112.610 197.840 112.840 198.835 ;
        RECT 112.565 197.200 112.885 197.840 ;
        RECT 112.610 195.805 112.840 197.200 ;
        RECT 112.565 195.165 112.885 195.805 ;
        RECT 112.610 189.290 112.840 195.165 ;
        RECT 112.565 188.650 112.885 189.290 ;
        RECT 111.275 181.765 111.595 183.020 ;
        RECT 111.255 179.615 111.615 181.765 ;
        RECT 111.275 179.140 111.595 179.615 ;
        RECT 111.320 167.505 111.550 179.140 ;
        RECT 110.465 167.300 111.105 167.390 ;
        RECT 111.755 167.300 112.395 167.390 ;
        RECT 110.415 167.070 111.165 167.300 ;
        RECT 111.705 167.070 112.455 167.300 ;
        RECT 100.790 166.830 102.730 166.835 ;
        RECT 104.660 166.830 105.300 166.835 ;
        RECT 107.240 166.830 107.895 166.835 ;
        RECT 109.780 166.830 110.420 166.835 ;
        RECT 112.610 166.830 112.840 188.650 ;
        RECT 113.900 183.020 114.130 213.505 ;
        RECT 115.190 212.380 115.420 214.180 ;
        RECT 115.630 213.940 116.270 214.020 ;
        RECT 116.920 213.940 117.560 214.020 ;
        RECT 115.575 213.710 116.325 213.940 ;
        RECT 116.865 213.710 117.615 213.940 ;
        RECT 117.770 213.710 121.720 214.180 ;
        RECT 121.930 213.940 122.570 214.020 ;
        RECT 123.220 213.940 123.860 214.020 ;
        RECT 121.875 213.710 122.625 213.940 ;
        RECT 123.165 213.710 123.915 213.940 ;
        RECT 115.630 213.700 116.270 213.710 ;
        RECT 116.920 213.700 117.560 213.710 ;
        RECT 115.145 211.740 115.465 212.380 ;
        RECT 115.190 210.650 115.420 211.740 ;
        RECT 115.145 210.010 115.465 210.650 ;
        RECT 115.190 199.475 115.420 210.010 ;
        RECT 115.145 198.835 115.465 199.475 ;
        RECT 115.190 197.840 115.420 198.835 ;
        RECT 115.145 197.200 115.465 197.840 ;
        RECT 115.190 195.805 115.420 197.200 ;
        RECT 115.145 195.165 115.465 195.805 ;
        RECT 115.190 189.290 115.420 195.165 ;
        RECT 115.145 188.650 115.465 189.290 ;
        RECT 113.855 181.785 114.175 183.020 ;
        RECT 113.835 179.645 114.195 181.785 ;
        RECT 113.900 167.505 114.130 179.645 ;
        RECT 113.050 167.300 113.690 167.390 ;
        RECT 114.340 167.300 114.980 167.390 ;
        RECT 112.995 167.070 113.745 167.300 ;
        RECT 114.285 167.070 115.035 167.300 ;
        RECT 115.190 166.830 115.420 188.650 ;
        RECT 116.480 183.020 116.710 213.505 ;
        RECT 117.770 212.380 118.000 213.710 ;
        RECT 117.725 211.740 118.045 212.380 ;
        RECT 119.060 212.350 119.290 213.710 ;
        RECT 119.630 212.380 119.860 213.710 ;
        RECT 118.995 211.770 119.355 212.350 ;
        RECT 117.770 210.650 118.000 211.740 ;
        RECT 119.060 210.650 119.290 211.770 ;
        RECT 119.580 211.740 119.900 212.380 ;
        RECT 120.200 212.350 120.430 213.710 ;
        RECT 121.490 212.350 121.720 213.710 ;
        RECT 121.930 213.700 122.570 213.710 ;
        RECT 123.220 213.700 123.860 213.710 ;
        RECT 120.135 211.770 120.495 212.350 ;
        RECT 121.425 211.770 121.785 212.350 ;
        RECT 119.630 210.650 119.860 211.740 ;
        RECT 120.200 210.650 120.430 211.770 ;
        RECT 121.490 210.650 121.720 211.770 ;
        RECT 117.725 210.010 118.045 210.650 ;
        RECT 119.015 210.010 119.335 210.650 ;
        RECT 119.585 210.010 119.905 210.650 ;
        RECT 120.155 210.010 120.475 210.650 ;
        RECT 121.445 210.010 121.765 210.650 ;
        RECT 117.770 199.475 118.000 210.010 ;
        RECT 117.725 198.835 118.045 199.475 ;
        RECT 119.060 199.470 119.290 210.010 ;
        RECT 119.630 199.475 119.860 210.010 ;
        RECT 120.200 199.475 120.430 210.010 ;
        RECT 121.490 199.475 121.720 210.010 ;
        RECT 117.770 197.840 118.000 198.835 ;
        RECT 119.015 198.830 119.335 199.470 ;
        RECT 119.585 198.835 119.905 199.475 ;
        RECT 120.160 198.835 120.480 199.475 ;
        RECT 121.445 198.835 121.765 199.475 ;
        RECT 119.060 197.840 119.290 198.830 ;
        RECT 119.630 197.840 119.860 198.835 ;
        RECT 120.200 197.840 120.430 198.835 ;
        RECT 121.490 197.840 121.720 198.835 ;
        RECT 117.725 197.200 118.045 197.840 ;
        RECT 119.015 197.200 119.335 197.840 ;
        RECT 119.575 197.200 119.895 197.840 ;
        RECT 120.155 197.200 120.475 197.840 ;
        RECT 121.445 197.200 121.765 197.840 ;
        RECT 117.770 195.800 118.000 197.200 ;
        RECT 119.060 195.805 119.290 197.200 ;
        RECT 119.630 195.805 119.860 197.200 ;
        RECT 120.200 195.805 120.430 197.200 ;
        RECT 121.490 195.805 121.720 197.200 ;
        RECT 117.725 195.160 118.045 195.800 ;
        RECT 119.015 195.165 119.335 195.805 ;
        RECT 119.580 195.165 119.900 195.805 ;
        RECT 120.155 195.165 120.475 195.805 ;
        RECT 121.445 195.165 121.765 195.805 ;
        RECT 117.770 189.290 118.000 195.160 ;
        RECT 119.060 189.290 119.290 195.165 ;
        RECT 119.630 189.290 119.860 195.165 ;
        RECT 120.200 189.290 120.430 195.165 ;
        RECT 121.490 189.290 121.720 195.165 ;
        RECT 117.725 188.650 118.045 189.290 ;
        RECT 119.015 188.650 119.335 189.290 ;
        RECT 119.580 188.650 119.900 189.290 ;
        RECT 120.155 188.650 120.475 189.290 ;
        RECT 121.445 188.650 121.765 189.290 ;
        RECT 116.435 181.790 116.755 183.020 ;
        RECT 116.415 179.640 116.775 181.790 ;
        RECT 116.480 167.505 116.710 179.640 ;
        RECT 115.625 167.300 116.265 167.390 ;
        RECT 116.920 167.300 117.560 167.390 ;
        RECT 117.770 167.300 118.000 188.650 ;
        RECT 119.060 180.435 119.290 188.650 ;
        RECT 119.015 179.140 119.335 180.435 ;
        RECT 119.060 167.300 119.290 179.140 ;
        RECT 119.630 167.300 119.860 188.650 ;
        RECT 120.200 167.300 120.430 188.650 ;
        RECT 121.490 167.300 121.720 188.650 ;
        RECT 122.780 182.930 123.010 213.505 ;
        RECT 124.070 212.350 124.300 214.180 ;
        RECT 124.510 213.940 125.150 214.020 ;
        RECT 125.800 213.940 126.440 214.020 ;
        RECT 124.455 213.710 125.205 213.940 ;
        RECT 125.745 213.710 126.495 213.940 ;
        RECT 124.510 213.700 125.150 213.710 ;
        RECT 125.800 213.700 126.440 213.710 ;
        RECT 124.005 211.770 124.365 212.350 ;
        RECT 124.070 210.650 124.300 211.770 ;
        RECT 124.025 210.010 124.345 210.650 ;
        RECT 124.070 199.475 124.300 210.010 ;
        RECT 124.025 198.835 124.345 199.475 ;
        RECT 124.070 197.840 124.300 198.835 ;
        RECT 124.025 197.200 124.345 197.840 ;
        RECT 124.070 195.805 124.300 197.200 ;
        RECT 124.025 195.165 124.345 195.805 ;
        RECT 124.070 189.290 124.300 195.165 ;
        RECT 124.025 188.650 124.345 189.290 ;
        RECT 122.715 181.665 123.075 182.930 ;
        RECT 122.780 167.505 123.010 181.665 ;
        RECT 121.930 167.300 122.570 167.390 ;
        RECT 123.220 167.300 123.860 167.390 ;
        RECT 115.575 167.070 116.325 167.300 ;
        RECT 116.865 167.070 117.615 167.300 ;
        RECT 117.770 166.830 121.720 167.300 ;
        RECT 121.875 167.070 122.625 167.300 ;
        RECT 123.165 167.070 123.915 167.300 ;
        RECT 124.070 166.830 124.300 188.650 ;
        RECT 125.360 182.915 125.590 213.505 ;
        RECT 126.650 212.350 126.880 214.180 ;
        RECT 127.090 213.940 127.730 214.020 ;
        RECT 128.380 213.940 129.020 214.020 ;
        RECT 127.035 213.710 127.785 213.940 ;
        RECT 128.325 213.710 129.075 213.940 ;
        RECT 127.090 213.700 127.730 213.710 ;
        RECT 128.380 213.700 129.020 213.710 ;
        RECT 126.585 211.770 126.945 212.350 ;
        RECT 126.650 210.650 126.880 211.770 ;
        RECT 126.605 210.010 126.925 210.650 ;
        RECT 126.650 199.475 126.880 210.010 ;
        RECT 126.605 198.835 126.925 199.475 ;
        RECT 126.650 197.840 126.880 198.835 ;
        RECT 126.605 197.200 126.925 197.840 ;
        RECT 126.650 195.805 126.880 197.200 ;
        RECT 126.605 195.165 126.925 195.805 ;
        RECT 126.650 189.290 126.880 195.165 ;
        RECT 126.605 188.650 126.925 189.290 ;
        RECT 125.295 181.665 125.655 182.915 ;
        RECT 125.360 167.505 125.590 181.665 ;
        RECT 124.510 167.300 125.150 167.390 ;
        RECT 125.800 167.300 126.440 167.390 ;
        RECT 124.455 167.070 125.205 167.300 ;
        RECT 125.745 167.070 126.495 167.300 ;
        RECT 125.305 166.830 125.945 166.835 ;
        RECT 126.650 166.830 126.880 188.650 ;
        RECT 127.940 182.930 128.170 213.505 ;
        RECT 129.230 212.350 129.460 214.180 ;
        RECT 129.670 213.940 130.310 214.020 ;
        RECT 130.960 213.940 131.600 214.020 ;
        RECT 129.615 213.710 130.365 213.940 ;
        RECT 130.905 213.710 131.655 213.940 ;
        RECT 129.670 213.700 130.310 213.710 ;
        RECT 130.960 213.700 131.600 213.710 ;
        RECT 129.165 211.770 129.525 212.350 ;
        RECT 129.230 210.650 129.460 211.770 ;
        RECT 129.185 210.010 129.505 210.650 ;
        RECT 129.230 199.475 129.460 210.010 ;
        RECT 129.185 198.835 129.505 199.475 ;
        RECT 129.230 197.840 129.460 198.835 ;
        RECT 129.185 197.200 129.505 197.840 ;
        RECT 129.230 195.805 129.460 197.200 ;
        RECT 129.185 195.165 129.505 195.805 ;
        RECT 129.230 189.290 129.460 195.165 ;
        RECT 129.185 188.650 129.505 189.290 ;
        RECT 127.875 181.665 128.235 182.930 ;
        RECT 127.940 167.505 128.170 181.665 ;
        RECT 127.090 167.300 127.730 167.390 ;
        RECT 128.380 167.300 129.020 167.390 ;
        RECT 127.035 167.070 127.785 167.300 ;
        RECT 128.325 167.070 129.075 167.300 ;
        RECT 127.885 166.830 128.525 166.835 ;
        RECT 129.230 166.830 129.460 188.650 ;
        RECT 130.520 182.930 130.750 213.505 ;
        RECT 131.810 212.350 132.040 214.180 ;
        RECT 132.250 213.940 132.890 214.020 ;
        RECT 133.540 213.940 134.180 214.020 ;
        RECT 132.195 213.710 132.945 213.940 ;
        RECT 133.485 213.710 134.235 213.940 ;
        RECT 132.250 213.700 132.890 213.710 ;
        RECT 133.540 213.700 134.180 213.710 ;
        RECT 131.745 211.770 132.105 212.350 ;
        RECT 131.810 210.650 132.040 211.770 ;
        RECT 131.765 210.010 132.085 210.650 ;
        RECT 131.810 199.475 132.040 210.010 ;
        RECT 131.765 198.835 132.085 199.475 ;
        RECT 131.810 197.840 132.040 198.835 ;
        RECT 131.765 197.200 132.085 197.840 ;
        RECT 131.810 195.805 132.040 197.200 ;
        RECT 131.765 195.165 132.085 195.805 ;
        RECT 131.810 189.290 132.040 195.165 ;
        RECT 131.765 188.650 132.085 189.290 ;
        RECT 130.455 181.665 130.815 182.930 ;
        RECT 130.520 167.505 130.750 181.665 ;
        RECT 129.670 167.300 130.310 167.390 ;
        RECT 130.960 167.300 131.600 167.390 ;
        RECT 129.615 167.070 130.365 167.300 ;
        RECT 130.905 167.070 131.655 167.300 ;
        RECT 130.465 166.830 131.105 166.835 ;
        RECT 131.810 166.830 132.040 188.650 ;
        RECT 133.100 182.950 133.330 213.505 ;
        RECT 134.390 212.350 134.620 214.180 ;
        RECT 134.830 213.940 135.470 214.020 ;
        RECT 136.120 213.940 136.760 214.020 ;
        RECT 134.775 213.710 135.525 213.940 ;
        RECT 136.065 213.710 136.815 213.940 ;
        RECT 134.830 213.700 135.470 213.710 ;
        RECT 136.120 213.700 136.760 213.710 ;
        RECT 134.325 211.770 134.685 212.350 ;
        RECT 134.390 210.650 134.620 211.770 ;
        RECT 134.345 210.010 134.665 210.650 ;
        RECT 134.390 199.475 134.620 210.010 ;
        RECT 134.345 198.835 134.665 199.475 ;
        RECT 134.390 197.840 134.620 198.835 ;
        RECT 134.345 197.200 134.665 197.840 ;
        RECT 134.390 195.805 134.620 197.200 ;
        RECT 134.345 195.165 134.665 195.805 ;
        RECT 134.390 189.290 134.620 195.165 ;
        RECT 134.345 188.650 134.665 189.290 ;
        RECT 133.035 181.665 133.395 182.950 ;
        RECT 133.100 167.505 133.330 181.665 ;
        RECT 132.250 167.300 132.890 167.390 ;
        RECT 133.540 167.300 134.180 167.390 ;
        RECT 132.195 167.070 132.945 167.300 ;
        RECT 133.485 167.070 134.235 167.300 ;
        RECT 133.050 166.830 133.690 166.835 ;
        RECT 134.390 166.830 134.620 188.650 ;
        RECT 135.680 182.935 135.910 213.505 ;
        RECT 136.970 212.350 137.200 214.180 ;
        RECT 137.410 213.940 138.050 214.020 ;
        RECT 137.355 213.710 138.105 213.940 ;
        RECT 138.260 213.710 139.780 213.940 ;
        RECT 137.410 213.700 138.050 213.710 ;
        RECT 136.905 211.770 137.265 212.350 ;
        RECT 136.970 210.650 137.200 211.770 ;
        RECT 136.925 210.010 137.245 210.650 ;
        RECT 136.970 199.475 137.200 210.010 ;
        RECT 136.925 198.835 137.245 199.475 ;
        RECT 136.970 197.840 137.200 198.835 ;
        RECT 136.925 197.200 137.245 197.840 ;
        RECT 136.970 195.805 137.200 197.200 ;
        RECT 136.925 195.165 137.245 195.805 ;
        RECT 136.970 189.290 137.200 195.165 ;
        RECT 136.925 188.650 137.245 189.290 ;
        RECT 135.615 181.665 135.975 182.935 ;
        RECT 135.680 167.505 135.910 181.665 ;
        RECT 134.830 167.300 135.470 167.390 ;
        RECT 136.120 167.300 136.760 167.390 ;
        RECT 134.775 167.070 135.525 167.300 ;
        RECT 136.065 167.070 136.815 167.300 ;
        RECT 136.970 166.830 137.200 188.650 ;
        RECT 138.260 182.920 138.490 213.710 ;
        RECT 139.550 182.930 139.780 213.710 ;
        RECT 138.195 181.665 138.555 182.920 ;
        RECT 139.485 181.670 139.845 182.930 ;
        RECT 137.410 167.300 138.050 167.390 ;
        RECT 138.260 167.300 138.490 181.665 ;
        RECT 139.550 167.300 139.780 181.670 ;
        RECT 137.355 167.070 138.105 167.300 ;
        RECT 138.260 167.070 139.780 167.300 ;
        RECT 100.790 166.515 139.900 166.830 ;
        RECT 59.580 108.705 59.900 108.710 ;
        RECT 59.580 108.700 135.495 108.705 ;
        RECT 59.580 108.385 139.160 108.700 ;
        RECT 59.580 108.145 60.430 108.385 ;
        RECT 61.490 108.145 61.720 108.385 ;
        RECT 62.780 108.145 63.010 108.385 ;
        RECT 65.360 108.145 65.590 108.385 ;
        RECT 66.650 108.145 66.880 108.385 ;
        RECT 67.940 108.145 68.785 108.385 ;
        RECT 59.580 107.915 63.915 108.145 ;
        RECT 64.455 107.915 68.785 108.145 ;
        RECT 59.580 102.505 59.900 107.915 ;
        RECT 60.200 102.505 60.430 107.915 ;
        RECT 61.490 102.505 61.720 107.915 ;
        RECT 62.780 106.585 63.010 107.915 ;
        RECT 65.360 106.585 65.590 107.915 ;
        RECT 62.735 105.945 63.055 106.585 ;
        RECT 65.315 105.945 65.635 106.585 ;
        RECT 62.780 104.855 63.010 105.945 ;
        RECT 65.360 104.855 65.590 105.945 ;
        RECT 62.735 104.215 63.055 104.855 ;
        RECT 65.315 104.215 65.635 104.855 ;
        RECT 62.780 102.505 63.010 104.215 ;
        RECT 64.025 103.350 64.345 103.990 ;
        RECT 59.580 102.275 63.915 102.505 ;
        RECT 59.580 89.340 59.900 102.275 ;
        RECT 60.200 102.060 61.905 102.065 ;
        RECT 60.200 101.740 62.630 102.060 ;
        RECT 60.200 96.330 60.430 101.740 ;
        RECT 60.585 101.735 61.335 101.740 ;
        RECT 61.875 101.735 62.625 101.740 ;
        RECT 61.490 97.220 61.720 101.530 ;
        RECT 61.490 96.530 61.725 97.220 ;
        RECT 61.495 96.330 61.725 96.530 ;
        RECT 60.200 96.010 62.630 96.330 ;
        RECT 60.200 96.005 61.725 96.010 ;
        RECT 60.200 95.555 61.335 95.785 ;
        RECT 60.200 90.145 60.430 95.555 ;
        RECT 60.200 89.915 61.335 90.145 ;
        RECT 59.555 83.960 59.915 89.200 ;
        RECT 61.495 87.055 61.725 96.005 ;
        RECT 62.780 93.680 63.010 102.275 ;
        RECT 63.170 101.965 63.920 102.060 ;
        RECT 63.165 101.740 63.920 101.965 ;
        RECT 63.165 101.735 63.915 101.740 ;
        RECT 63.170 96.325 63.920 96.330 ;
        RECT 63.165 96.095 63.920 96.325 ;
        RECT 63.170 96.010 63.920 96.095 ;
        RECT 63.220 96.005 63.860 96.010 ;
        RECT 64.070 94.725 64.300 103.350 ;
        RECT 65.360 102.505 65.590 104.215 ;
        RECT 66.650 102.505 66.880 107.915 ;
        RECT 67.940 102.505 68.170 107.915 ;
        RECT 68.465 102.505 68.785 107.915 ;
        RECT 69.080 108.145 69.310 108.385 ;
        RECT 70.370 108.145 70.610 108.385 ;
        RECT 69.080 107.915 70.650 108.145 ;
        RECT 72.905 108.035 73.225 108.385 ;
        RECT 75.485 108.035 75.805 108.385 ;
        RECT 78.065 108.035 78.385 108.385 ;
        RECT 80.645 108.035 80.965 108.385 ;
        RECT 83.225 108.035 83.545 108.385 ;
        RECT 85.805 108.145 86.125 108.385 ;
        RECT 87.090 108.145 87.410 108.385 ;
        RECT 85.805 108.035 87.410 108.145 ;
        RECT 69.080 106.585 69.310 107.915 ;
        RECT 70.370 106.585 70.610 107.915 ;
        RECT 72.950 106.585 73.180 108.035 ;
        RECT 74.195 106.815 74.515 107.455 ;
        RECT 69.035 105.945 69.355 106.585 ;
        RECT 70.325 105.945 70.645 106.585 ;
        RECT 72.905 105.945 73.225 106.585 ;
        RECT 69.080 104.855 69.310 105.945 ;
        RECT 70.370 104.855 70.610 105.945 ;
        RECT 71.615 105.060 71.935 105.700 ;
        RECT 69.035 104.215 69.355 104.855 ;
        RECT 70.325 104.215 70.645 104.855 ;
        RECT 64.455 102.275 68.785 102.505 ;
        RECT 64.460 101.965 65.210 102.060 ;
        RECT 64.455 101.740 65.210 101.965 ;
        RECT 64.455 101.735 65.205 101.740 ;
        RECT 64.460 96.325 65.210 96.330 ;
        RECT 64.455 96.095 65.210 96.325 ;
        RECT 64.460 96.010 65.210 96.095 ;
        RECT 64.510 96.005 65.150 96.010 ;
        RECT 64.025 94.085 64.345 94.725 ;
        RECT 62.735 93.040 63.055 93.680 ;
        RECT 62.780 92.045 63.010 93.040 ;
        RECT 62.735 91.405 63.055 92.045 ;
        RECT 62.780 89.435 63.010 91.405 ;
        RECT 62.735 89.200 63.055 89.205 ;
        RECT 61.865 88.895 63.930 89.200 ;
        RECT 62.735 88.885 63.055 88.895 ;
        RECT 61.930 87.055 62.570 87.145 ;
        RECT 63.220 87.055 63.860 87.145 ;
        RECT 60.200 86.825 61.725 87.055 ;
        RECT 61.875 86.825 62.625 87.055 ;
        RECT 63.165 86.825 63.915 87.055 ;
        RECT 60.200 86.005 60.430 86.825 ;
        RECT 61.490 86.005 61.725 86.825 ;
        RECT 60.200 85.775 61.725 86.005 ;
        RECT 61.875 85.775 62.625 86.005 ;
        RECT 61.930 85.685 62.570 85.775 ;
        RECT 60.200 85.235 61.720 85.465 ;
        RECT 60.200 84.415 60.430 85.235 ;
        RECT 61.490 84.415 61.720 85.235 ;
        RECT 62.780 85.130 63.010 86.665 ;
        RECT 64.070 86.165 64.300 94.085 ;
        RECT 65.360 93.680 65.590 102.275 ;
        RECT 66.475 102.060 68.170 102.065 ;
        RECT 65.750 101.965 68.170 102.060 ;
        RECT 65.745 101.740 68.170 101.965 ;
        RECT 65.745 101.735 66.495 101.740 ;
        RECT 67.035 101.735 67.785 101.740 ;
        RECT 66.650 97.210 66.880 101.530 ;
        RECT 66.650 96.530 66.885 97.210 ;
        RECT 66.655 96.335 66.885 96.530 ;
        RECT 67.940 96.335 68.170 101.740 ;
        RECT 66.475 96.330 68.170 96.335 ;
        RECT 65.750 96.325 68.170 96.330 ;
        RECT 65.745 96.095 68.170 96.325 ;
        RECT 65.750 96.010 68.170 96.095 ;
        RECT 65.800 96.005 66.440 96.010 ;
        RECT 65.310 93.360 65.630 93.680 ;
        RECT 65.315 93.040 65.635 93.360 ;
        RECT 65.360 92.045 65.590 93.040 ;
        RECT 65.315 91.405 65.635 92.045 ;
        RECT 65.360 89.435 65.590 91.405 ;
        RECT 64.440 88.895 66.515 89.200 ;
        RECT 65.315 88.880 65.635 88.895 ;
        RECT 64.510 87.055 65.150 87.145 ;
        RECT 65.800 87.055 66.440 87.145 ;
        RECT 66.655 87.055 66.885 96.010 ;
        RECT 67.035 95.555 68.170 95.785 ;
        RECT 67.940 90.145 68.170 95.555 ;
        RECT 67.035 89.915 68.170 90.145 ;
        RECT 67.940 89.910 68.170 89.915 ;
        RECT 68.465 89.660 68.785 102.275 ;
        RECT 69.080 102.505 69.310 104.215 ;
        RECT 70.370 102.505 70.610 104.215 ;
        RECT 70.815 103.985 71.135 103.990 ;
        RECT 70.815 103.350 71.455 103.985 ;
        RECT 71.135 103.345 71.455 103.350 ;
        RECT 69.080 102.275 70.610 102.505 ;
        RECT 69.080 101.965 69.310 102.275 ;
        RECT 70.370 101.965 70.610 102.275 ;
        RECT 69.080 101.735 70.610 101.965 ;
        RECT 70.755 101.735 71.505 102.055 ;
        RECT 69.080 96.325 69.310 101.735 ;
        RECT 70.370 101.365 70.610 101.735 ;
        RECT 70.370 96.325 70.600 101.365 ;
        RECT 69.080 96.095 70.600 96.325 ;
        RECT 69.080 95.785 69.310 96.095 ;
        RECT 70.370 95.785 70.600 96.095 ;
        RECT 70.755 96.005 71.505 96.325 ;
        RECT 69.080 95.555 70.600 95.785 ;
        RECT 69.080 93.680 69.310 95.555 ;
        RECT 70.370 93.680 70.600 95.555 ;
        RECT 69.035 93.040 69.355 93.680 ;
        RECT 70.325 93.040 70.645 93.680 ;
        RECT 69.080 92.045 69.310 93.040 ;
        RECT 70.370 92.045 70.600 93.040 ;
        RECT 71.660 92.855 71.890 105.060 ;
        RECT 72.950 104.855 73.180 105.945 ;
        RECT 72.905 104.215 73.225 104.855 ;
        RECT 72.045 101.735 72.795 102.055 ;
        RECT 72.045 96.005 72.795 96.325 ;
        RECT 72.950 93.680 73.180 104.215 ;
        RECT 73.335 101.735 74.085 102.055 ;
        RECT 73.335 96.005 74.085 96.325 ;
        RECT 72.905 93.040 73.225 93.680 ;
        RECT 71.615 92.215 71.935 92.855 ;
        RECT 72.950 92.045 73.180 93.040 ;
        RECT 69.035 91.405 69.355 92.045 ;
        RECT 70.325 91.405 70.645 92.045 ;
        RECT 72.905 91.405 73.225 92.045 ;
        RECT 69.080 90.145 69.310 91.405 ;
        RECT 70.370 90.145 70.600 91.405 ;
        RECT 69.080 90.010 70.645 90.145 ;
        RECT 72.950 90.010 73.180 91.405 ;
        RECT 74.240 91.255 74.470 106.815 ;
        RECT 75.530 106.585 75.760 108.035 ;
        RECT 78.110 106.590 78.340 108.035 ;
        RECT 79.355 106.815 79.675 107.455 ;
        RECT 75.480 105.945 75.800 106.585 ;
        RECT 78.065 105.950 78.385 106.590 ;
        RECT 75.530 104.855 75.760 105.945 ;
        RECT 76.775 105.060 77.095 105.700 ;
        RECT 75.485 104.215 75.805 104.855 ;
        RECT 74.625 101.735 75.375 102.055 ;
        RECT 74.625 96.005 75.375 96.325 ;
        RECT 75.530 93.680 75.760 104.215 ;
        RECT 75.915 101.735 76.665 102.055 ;
        RECT 76.825 101.530 77.055 105.060 ;
        RECT 78.110 104.855 78.340 105.950 ;
        RECT 78.065 104.215 78.385 104.855 ;
        RECT 77.205 101.735 77.955 102.055 ;
        RECT 76.820 96.530 77.055 101.530 ;
        RECT 75.915 96.005 76.665 96.325 ;
        RECT 75.485 93.040 75.805 93.680 ;
        RECT 75.530 92.045 75.760 93.040 ;
        RECT 76.825 92.855 77.055 96.530 ;
        RECT 77.205 96.005 77.955 96.325 ;
        RECT 78.110 93.680 78.340 104.215 ;
        RECT 78.495 101.735 79.245 102.055 ;
        RECT 78.495 96.005 79.245 96.325 ;
        RECT 78.065 93.040 78.385 93.680 ;
        RECT 76.775 92.215 77.095 92.855 ;
        RECT 75.485 91.405 75.805 92.045 ;
        RECT 74.195 90.615 74.515 91.255 ;
        RECT 75.530 90.010 75.760 91.405 ;
        RECT 69.035 89.915 70.645 90.010 ;
        RECT 69.035 89.660 69.355 89.915 ;
        RECT 70.325 89.660 70.645 89.915 ;
        RECT 72.905 89.660 73.225 90.010 ;
        RECT 75.485 89.660 75.805 90.010 ;
        RECT 67.205 89.390 76.380 89.660 ;
        RECT 69.035 89.370 69.355 89.390 ;
        RECT 70.325 89.370 70.645 89.390 ;
        RECT 72.905 89.370 73.225 89.390 ;
        RECT 75.485 89.370 75.805 89.390 ;
        RECT 67.185 88.895 76.425 89.200 ;
        RECT 68.465 88.805 68.785 88.895 ;
        RECT 64.455 86.825 65.205 87.055 ;
        RECT 65.745 86.825 66.495 87.055 ;
        RECT 66.655 86.825 68.170 87.055 ;
        RECT 66.655 86.665 66.885 86.825 ;
        RECT 63.165 85.775 63.915 86.005 ;
        RECT 63.220 85.685 63.860 85.775 ;
        RECT 62.735 84.490 63.055 85.130 ;
        RECT 60.200 84.185 61.720 84.415 ;
        RECT 60.200 83.960 60.430 84.185 ;
        RECT 61.490 83.960 61.720 84.185 ;
        RECT 64.070 83.960 64.300 85.990 ;
        RECT 64.455 85.775 65.205 86.005 ;
        RECT 64.510 85.685 65.150 85.775 ;
        RECT 65.360 85.140 65.590 86.665 ;
        RECT 66.650 86.650 66.885 86.665 ;
        RECT 66.650 86.005 66.880 86.650 ;
        RECT 67.940 86.005 68.170 86.825 ;
        RECT 65.745 85.775 66.495 86.005 ;
        RECT 66.650 85.775 68.170 86.005 ;
        RECT 65.800 85.685 66.440 85.775 ;
        RECT 66.650 85.235 68.170 85.465 ;
        RECT 65.315 84.500 65.635 85.140 ;
        RECT 66.650 84.415 66.880 85.235 ;
        RECT 67.940 84.415 68.170 85.235 ;
        RECT 66.650 84.185 68.170 84.415 ;
        RECT 68.520 84.275 68.750 88.805 ;
        RECT 69.025 88.645 69.345 88.895 ;
        RECT 70.315 88.645 70.635 88.895 ;
        RECT 72.895 88.645 73.215 88.895 ;
        RECT 75.475 88.645 75.795 88.895 ;
        RECT 69.025 88.560 76.655 88.645 ;
        RECT 69.070 88.415 76.655 88.560 ;
        RECT 69.070 87.595 69.300 88.415 ;
        RECT 70.360 87.595 70.590 88.415 ;
        RECT 71.650 87.595 71.880 88.415 ;
        RECT 72.940 87.595 73.170 88.415 ;
        RECT 74.230 87.595 74.460 88.415 ;
        RECT 75.520 87.595 75.750 88.415 ;
        RECT 69.070 87.365 76.675 87.595 ;
        RECT 69.070 87.055 69.300 87.365 ;
        RECT 70.360 87.055 70.590 87.365 ;
        RECT 69.070 86.825 70.590 87.055 ;
        RECT 70.745 86.825 71.495 87.145 ;
        RECT 72.035 86.825 72.785 87.145 ;
        RECT 69.070 86.005 69.300 86.825 ;
        RECT 70.360 86.005 70.590 86.825 ;
        RECT 69.070 85.775 70.590 86.005 ;
        RECT 69.070 85.465 69.300 85.775 ;
        RECT 70.360 85.465 70.590 85.775 ;
        RECT 70.745 85.685 71.495 86.005 ;
        RECT 69.070 85.235 70.590 85.465 ;
        RECT 69.070 84.415 69.300 85.235 ;
        RECT 70.360 84.415 70.590 85.235 ;
        RECT 71.650 85.140 71.880 86.665 ;
        RECT 72.035 85.685 72.785 86.005 ;
        RECT 71.605 84.500 71.925 85.140 ;
        RECT 71.650 84.490 71.880 84.500 ;
        RECT 69.070 84.275 70.590 84.415 ;
        RECT 72.940 84.275 73.170 87.365 ;
        RECT 73.325 86.825 74.075 87.145 ;
        RECT 74.615 86.825 75.365 87.145 ;
        RECT 73.325 85.685 74.075 86.005 ;
        RECT 74.230 85.140 74.460 86.665 ;
        RECT 74.615 85.685 75.365 86.005 ;
        RECT 74.185 84.500 74.505 85.140 ;
        RECT 74.230 84.490 74.460 84.500 ;
        RECT 75.520 84.275 75.750 87.365 ;
        RECT 75.905 86.825 76.655 87.145 ;
        RECT 76.825 86.665 77.055 92.215 ;
        RECT 78.110 92.045 78.340 93.040 ;
        RECT 78.065 91.405 78.385 92.045 ;
        RECT 78.110 90.010 78.340 91.405 ;
        RECT 79.400 91.255 79.630 106.815 ;
        RECT 80.690 106.585 80.920 108.035 ;
        RECT 83.270 106.585 83.500 108.035 ;
        RECT 85.805 107.915 87.370 108.035 ;
        RECT 84.515 106.815 84.835 107.455 ;
        RECT 80.645 105.945 80.965 106.585 ;
        RECT 83.225 105.945 83.545 106.585 ;
        RECT 80.690 104.855 80.920 105.945 ;
        RECT 81.935 105.060 82.255 105.700 ;
        RECT 80.645 104.215 80.965 104.855 ;
        RECT 79.785 101.735 80.535 102.055 ;
        RECT 79.785 96.005 80.535 96.325 ;
        RECT 80.690 93.680 80.920 104.215 ;
        RECT 81.075 101.735 81.825 102.055 ;
        RECT 81.075 96.005 81.825 96.325 ;
        RECT 80.645 93.040 80.965 93.680 ;
        RECT 80.690 92.045 80.920 93.040 ;
        RECT 81.980 92.855 82.210 105.060 ;
        RECT 83.270 104.855 83.500 105.945 ;
        RECT 83.225 104.215 83.545 104.855 ;
        RECT 82.365 101.735 83.115 102.055 ;
        RECT 82.365 96.005 83.115 96.325 ;
        RECT 83.270 93.680 83.500 104.215 ;
        RECT 83.655 101.735 84.405 102.055 ;
        RECT 83.655 96.005 84.405 96.325 ;
        RECT 83.225 93.040 83.545 93.680 ;
        RECT 81.935 92.215 82.255 92.855 ;
        RECT 83.270 92.045 83.500 93.040 ;
        RECT 80.645 91.405 80.965 92.045 ;
        RECT 83.225 91.405 83.545 92.045 ;
        RECT 79.355 90.615 79.675 91.255 ;
        RECT 80.690 90.010 80.920 91.405 ;
        RECT 83.270 90.010 83.500 91.405 ;
        RECT 84.560 91.255 84.790 106.815 ;
        RECT 85.850 106.585 86.080 107.915 ;
        RECT 87.140 106.585 87.370 107.915 ;
        RECT 85.805 105.945 86.125 106.585 ;
        RECT 87.095 105.945 87.415 106.585 ;
        RECT 85.850 104.855 86.080 105.945 ;
        RECT 87.140 104.855 87.370 105.945 ;
        RECT 85.805 104.215 86.125 104.855 ;
        RECT 87.095 104.215 87.415 104.855 ;
        RECT 85.850 102.505 86.080 104.215 ;
        RECT 87.140 102.505 87.370 104.215 ;
        RECT 85.850 102.275 87.370 102.505 ;
        RECT 84.945 101.735 85.695 102.055 ;
        RECT 85.850 101.965 86.080 102.275 ;
        RECT 87.140 101.965 87.370 102.275 ;
        RECT 85.850 101.735 87.370 101.965 ;
        RECT 85.850 96.325 86.080 101.735 ;
        RECT 87.140 96.325 87.370 101.735 ;
        RECT 84.945 96.005 85.695 96.325 ;
        RECT 85.850 96.095 87.370 96.325 ;
        RECT 85.850 95.785 86.080 96.095 ;
        RECT 87.140 95.785 87.370 96.095 ;
        RECT 85.850 95.555 87.370 95.785 ;
        RECT 85.850 93.680 86.080 95.555 ;
        RECT 87.140 93.680 87.370 95.555 ;
        RECT 85.805 93.040 86.125 93.680 ;
        RECT 87.095 93.040 87.415 93.680 ;
        RECT 85.850 92.045 86.080 93.040 ;
        RECT 87.140 92.045 87.370 93.040 ;
        RECT 85.805 91.405 86.125 92.045 ;
        RECT 87.095 91.405 87.415 92.045 ;
        RECT 84.520 90.615 84.840 91.255 ;
        RECT 85.850 90.145 86.080 91.405 ;
        RECT 87.140 90.145 87.370 91.405 ;
        RECT 85.805 90.010 87.370 90.145 ;
        RECT 78.065 89.650 78.385 90.010 ;
        RECT 80.645 89.650 80.965 90.010 ;
        RECT 83.225 89.650 83.545 90.010 ;
        RECT 85.805 89.915 87.410 90.010 ;
        RECT 85.805 89.650 86.125 89.915 ;
        RECT 87.090 89.650 87.410 89.915 ;
        RECT 77.360 89.375 87.410 89.650 ;
        RECT 87.660 89.425 87.980 108.385 ;
        RECT 88.260 108.145 88.485 108.385 ;
        RECT 89.550 108.145 89.780 108.385 ;
        RECT 88.260 107.915 89.780 108.145 ;
        RECT 88.260 107.710 88.485 107.915 ;
        RECT 88.260 106.585 88.490 107.710 ;
        RECT 89.550 106.585 89.780 107.915 ;
        RECT 92.130 106.585 92.360 108.385 ;
        RECT 94.710 106.585 94.940 108.385 ;
        RECT 97.290 108.145 97.520 108.385 ;
        RECT 98.580 108.145 98.810 108.385 ;
        RECT 97.290 107.915 98.810 108.145 ;
        RECT 97.290 106.585 97.520 107.915 ;
        RECT 98.580 106.585 98.810 107.915 ;
        RECT 88.215 105.945 88.535 106.585 ;
        RECT 89.505 105.945 89.825 106.585 ;
        RECT 92.085 105.945 92.405 106.585 ;
        RECT 94.665 105.945 94.985 106.585 ;
        RECT 97.245 105.945 97.565 106.585 ;
        RECT 98.535 105.945 98.855 106.585 ;
        RECT 88.260 104.855 88.490 105.945 ;
        RECT 89.550 104.855 89.780 105.945 ;
        RECT 92.130 104.855 92.360 105.945 ;
        RECT 88.215 104.215 88.535 104.855 ;
        RECT 89.505 104.215 89.825 104.855 ;
        RECT 92.085 104.215 92.405 104.855 ;
        RECT 88.260 102.505 88.490 104.215 ;
        RECT 89.550 102.505 89.780 104.215 ;
        RECT 90.795 102.740 91.115 104.075 ;
        RECT 88.260 102.275 89.780 102.505 ;
        RECT 88.260 101.965 88.490 102.275 ;
        RECT 89.550 101.965 89.780 102.275 ;
        RECT 89.990 101.965 90.630 102.055 ;
        RECT 88.260 101.735 89.780 101.965 ;
        RECT 89.935 101.735 90.685 101.965 ;
        RECT 88.260 96.325 88.490 101.735 ;
        RECT 89.550 96.325 89.780 101.735 ;
        RECT 88.260 96.095 89.780 96.325 ;
        RECT 89.935 96.095 90.685 96.325 ;
        RECT 88.260 95.345 88.490 96.095 ;
        RECT 88.215 93.835 88.535 95.115 ;
        RECT 78.065 89.370 78.385 89.375 ;
        RECT 80.645 89.370 80.965 89.375 ;
        RECT 83.225 89.370 83.545 89.375 ;
        RECT 85.805 89.370 86.125 89.375 ;
        RECT 87.090 89.370 87.410 89.375 ;
        RECT 77.335 88.905 87.235 89.200 ;
        RECT 78.060 88.645 78.380 88.905 ;
        RECT 80.635 88.645 80.955 88.905 ;
        RECT 83.215 88.645 83.535 88.905 ;
        RECT 84.505 88.645 84.825 88.905 ;
        RECT 77.195 88.560 84.825 88.645 ;
        RECT 77.195 88.415 84.780 88.560 ;
        RECT 78.100 87.595 78.330 88.415 ;
        RECT 79.390 87.595 79.620 88.415 ;
        RECT 80.680 87.595 80.910 88.415 ;
        RECT 81.970 87.595 82.200 88.415 ;
        RECT 83.260 87.595 83.490 88.415 ;
        RECT 84.550 87.595 84.780 88.415 ;
        RECT 77.195 87.365 84.780 87.595 ;
        RECT 77.195 86.825 77.945 87.145 ;
        RECT 76.810 86.165 77.055 86.665 ;
        RECT 75.905 85.685 76.655 86.005 ;
        RECT 66.650 83.960 66.880 84.185 ;
        RECT 67.940 83.960 68.170 84.185 ;
        RECT 68.465 83.960 68.785 84.275 ;
        RECT 69.015 84.185 70.625 84.275 ;
        RECT 69.015 83.960 69.335 84.185 ;
        RECT 70.305 83.960 70.625 84.185 ;
        RECT 72.885 83.960 73.205 84.275 ;
        RECT 75.465 83.960 75.785 84.275 ;
        RECT 59.555 83.635 76.460 83.960 ;
        RECT 75.520 83.625 75.750 83.635 ;
        RECT 60.315 83.490 60.635 83.495 ;
        RECT 68.180 83.490 68.500 83.495 ;
        RECT 70.310 83.490 70.630 83.495 ;
        RECT 72.890 83.490 73.210 83.495 ;
        RECT 73.945 83.490 74.490 83.495 ;
        RECT 60.315 83.150 75.060 83.490 ;
        RECT 60.315 76.800 60.635 83.150 ;
        RECT 63.450 82.850 63.770 83.150 ;
        RECT 67.945 82.855 68.735 83.150 ;
        RECT 70.310 82.855 70.630 83.150 ;
        RECT 72.890 82.855 73.210 83.150 ;
        RECT 74.170 82.855 74.490 83.150 ;
        RECT 60.935 82.165 62.455 82.395 ;
        RECT 60.935 81.255 61.165 82.165 ;
        RECT 62.225 81.255 62.455 82.165 ;
        RECT 60.935 81.025 62.455 81.255 ;
        RECT 60.935 80.715 61.165 81.025 ;
        RECT 62.225 80.715 62.455 81.025 ;
        RECT 60.935 80.485 62.455 80.715 ;
        RECT 62.610 80.485 63.360 80.950 ;
        RECT 60.935 79.575 61.165 80.485 ;
        RECT 62.225 79.575 62.455 80.485 ;
        RECT 60.935 79.345 62.455 79.575 ;
        RECT 60.935 79.035 61.165 79.345 ;
        RECT 62.225 79.035 62.455 79.345 ;
        RECT 62.610 79.210 63.360 79.575 ;
        RECT 60.935 78.805 62.455 79.035 ;
        RECT 60.935 77.895 61.165 78.805 ;
        RECT 62.225 77.895 62.455 78.805 ;
        RECT 60.935 77.665 62.455 77.895 ;
        RECT 59.755 76.545 60.075 76.600 ;
        RECT 59.755 76.255 60.800 76.545 ;
        RECT 61.445 76.540 62.065 76.550 ;
        RECT 61.435 76.270 62.065 76.540 ;
        RECT 61.445 76.260 62.065 76.270 ;
        RECT 59.755 70.775 60.075 76.255 ;
        RECT 60.385 76.005 60.615 76.255 ;
        RECT 61.675 76.005 61.915 76.260 ;
        RECT 60.385 75.775 61.915 76.005 ;
        RECT 60.385 74.785 60.615 75.775 ;
        RECT 61.675 74.785 61.915 75.775 ;
        RECT 62.225 75.255 62.455 77.665 ;
        RECT 63.515 77.035 63.745 82.850 ;
        RECT 66.600 81.840 66.920 82.480 ;
        RECT 63.900 80.485 65.045 80.950 ;
        RECT 64.805 79.575 65.045 80.485 ;
        RECT 63.900 79.210 65.045 79.575 ;
        RECT 63.335 76.745 63.925 77.035 ;
        RECT 60.385 74.555 61.915 74.785 ;
        RECT 60.385 74.245 60.615 74.555 ;
        RECT 61.675 74.245 61.915 74.555 ;
        RECT 62.060 74.475 62.815 75.255 ;
        RECT 60.385 74.015 61.915 74.245 ;
        RECT 60.385 73.025 60.615 74.015 ;
        RECT 61.675 73.035 61.915 74.015 ;
        RECT 62.060 74.015 62.810 74.335 ;
        RECT 61.675 73.025 61.905 73.035 ;
        RECT 60.385 72.795 61.905 73.025 ;
        RECT 60.385 72.485 60.615 72.795 ;
        RECT 61.675 72.485 61.905 72.795 ;
        RECT 62.060 73.025 62.305 74.015 ;
        RECT 62.555 73.025 62.810 74.015 ;
        RECT 62.060 72.705 62.810 73.025 ;
        RECT 62.960 74.305 63.280 76.275 ;
        RECT 64.255 74.305 64.485 76.225 ;
        RECT 62.960 73.985 64.485 74.305 ;
        RECT 62.960 73.055 63.280 73.985 ;
        RECT 64.255 73.055 64.485 73.985 ;
        RECT 62.960 72.735 64.485 73.055 ;
        RECT 60.385 72.255 61.905 72.485 ;
        RECT 60.385 71.460 60.615 72.255 ;
        RECT 60.325 71.265 60.645 71.460 ;
        RECT 61.675 71.425 61.905 72.255 ;
        RECT 62.060 71.785 62.810 72.565 ;
        RECT 61.630 71.265 61.950 71.425 ;
        RECT 60.325 71.035 61.950 71.265 ;
        RECT 60.325 70.775 60.645 71.035 ;
        RECT 61.630 70.780 61.950 71.035 ;
        RECT 59.755 70.485 60.830 70.775 ;
        RECT 61.485 70.515 62.075 70.780 ;
        RECT 59.755 69.050 60.075 70.485 ;
        RECT 62.300 69.555 62.620 71.785 ;
        RECT 62.960 70.225 63.280 72.735 ;
        RECT 64.255 70.545 64.485 72.735 ;
        RECT 64.805 70.720 65.045 79.210 ;
        RECT 66.655 76.945 66.885 81.840 ;
        RECT 67.105 80.930 67.745 80.950 ;
        RECT 67.040 80.700 67.790 80.930 ;
        RECT 67.105 80.630 67.745 80.700 ;
        RECT 67.040 79.210 67.790 79.530 ;
        RECT 67.945 77.050 68.175 82.855 ;
        RECT 68.505 82.490 68.735 82.855 ;
        RECT 70.355 82.615 70.585 82.855 ;
        RECT 72.935 82.615 73.165 82.855 ;
        RECT 74.225 82.615 74.455 82.855 ;
        RECT 70.355 82.490 74.455 82.615 ;
        RECT 68.505 82.385 74.455 82.490 ;
        RECT 68.505 82.260 70.585 82.385 ;
        RECT 68.505 81.385 68.735 82.260 ;
        RECT 69.795 81.385 70.025 82.260 ;
        RECT 70.355 81.385 70.585 82.260 ;
        RECT 71.645 81.385 71.875 82.385 ;
        RECT 72.935 81.385 73.165 82.385 ;
        RECT 74.225 81.385 74.455 82.385 ;
        RECT 68.505 81.120 74.455 81.385 ;
        RECT 68.505 77.050 68.735 81.120 ;
        RECT 69.795 79.875 70.205 80.375 ;
        RECT 66.045 76.290 66.395 76.550 ;
        RECT 66.600 76.305 66.920 76.945 ;
        RECT 67.360 76.305 67.680 76.945 ;
        RECT 67.945 76.760 68.735 77.050 ;
        RECT 65.250 74.165 65.890 74.285 ;
        RECT 65.200 73.935 65.950 74.165 ;
        RECT 65.200 72.885 65.950 73.115 ;
        RECT 65.265 72.765 65.905 72.885 ;
        RECT 66.105 71.475 66.335 76.290 ;
        RECT 66.070 71.155 66.390 71.475 ;
        RECT 66.065 70.770 66.385 71.155 ;
        RECT 64.210 70.225 64.530 70.545 ;
        RECT 65.915 70.520 66.505 70.770 ;
        RECT 67.395 70.720 67.625 76.305 ;
        RECT 68.490 76.265 69.110 76.555 ;
        RECT 67.835 74.165 68.475 74.235 ;
        RECT 67.780 73.935 68.530 74.165 ;
        RECT 67.835 73.915 68.475 73.935 ;
        RECT 67.830 73.115 68.470 73.155 ;
        RECT 67.780 72.885 68.530 73.115 ;
        RECT 67.830 72.835 68.470 72.885 ;
        RECT 68.685 71.475 68.915 76.265 ;
        RECT 69.975 74.235 70.205 79.875 ;
        RECT 70.355 77.095 70.585 81.120 ;
        RECT 72.935 80.845 73.165 81.120 ;
        RECT 74.225 80.845 74.455 81.120 ;
        RECT 72.035 80.615 72.775 80.845 ;
        RECT 70.940 80.245 71.875 80.410 ;
        RECT 70.935 79.820 71.875 80.245 ;
        RECT 70.935 78.050 71.575 79.820 ;
        RECT 72.285 79.615 72.515 80.615 ;
        RECT 72.935 80.610 74.455 80.845 ;
        RECT 72.935 79.620 73.165 80.610 ;
        RECT 74.225 79.620 74.455 80.610 ;
        RECT 72.035 78.835 72.775 79.615 ;
        RECT 72.935 79.385 74.455 79.620 ;
        RECT 72.935 79.080 73.165 79.385 ;
        RECT 74.225 79.080 74.455 79.385 ;
        RECT 72.935 78.845 74.455 79.080 ;
        RECT 70.355 76.745 70.690 77.095 ;
        RECT 69.120 74.165 70.205 74.235 ;
        RECT 69.070 73.935 70.205 74.165 ;
        RECT 69.120 73.915 70.205 73.935 ;
        RECT 69.975 73.155 70.205 73.915 ;
        RECT 69.125 73.115 70.205 73.155 ;
        RECT 69.070 72.885 70.205 73.115 ;
        RECT 69.125 72.835 70.205 72.885 ;
        RECT 68.640 70.770 68.960 71.475 ;
        RECT 68.505 70.515 69.095 70.770 ;
        RECT 69.975 70.720 70.205 72.835 ;
        RECT 70.935 70.550 71.150 78.050 ;
        RECT 71.340 70.550 71.575 78.050 ;
        RECT 72.035 77.915 72.775 78.695 ;
        RECT 72.285 76.985 72.515 77.915 ;
        RECT 72.935 77.845 73.165 78.845 ;
        RECT 74.225 77.845 74.455 78.845 ;
        RECT 72.935 77.610 74.455 77.845 ;
        RECT 72.935 77.030 73.165 77.610 ;
        RECT 74.225 77.030 74.455 77.610 ;
        RECT 74.740 77.030 75.060 83.150 ;
        RECT 76.815 80.900 77.055 86.165 ;
        RECT 77.195 85.685 77.945 86.005 ;
        RECT 78.100 84.275 78.330 87.365 ;
        RECT 78.485 86.825 79.235 87.145 ;
        RECT 79.775 86.825 80.525 87.145 ;
        RECT 78.485 85.685 79.235 86.005 ;
        RECT 79.390 85.140 79.620 86.665 ;
        RECT 79.775 85.685 80.525 86.005 ;
        RECT 79.345 84.500 79.665 85.140 ;
        RECT 79.390 84.490 79.620 84.500 ;
        RECT 80.680 84.275 80.910 87.365 ;
        RECT 81.065 86.825 81.815 87.145 ;
        RECT 82.355 86.825 83.105 87.145 ;
        RECT 83.260 87.055 83.490 87.365 ;
        RECT 84.550 87.055 84.780 87.365 ;
        RECT 83.260 86.825 84.780 87.055 ;
        RECT 81.065 85.685 81.815 86.005 ;
        RECT 81.970 85.140 82.200 86.665 ;
        RECT 83.260 86.005 83.490 86.825 ;
        RECT 84.550 86.005 84.780 86.825 ;
        RECT 82.355 85.685 83.105 86.005 ;
        RECT 83.260 85.775 84.780 86.005 ;
        RECT 83.260 85.465 83.490 85.775 ;
        RECT 84.550 85.465 84.780 85.775 ;
        RECT 83.260 85.235 84.780 85.465 ;
        RECT 81.925 84.500 82.245 85.140 ;
        RECT 81.970 84.490 82.200 84.500 ;
        RECT 83.260 84.415 83.490 85.235 ;
        RECT 84.550 84.415 84.780 85.235 ;
        RECT 83.260 84.275 84.780 84.415 ;
        RECT 78.050 83.960 78.370 84.275 ;
        RECT 80.630 83.960 80.950 84.275 ;
        RECT 83.210 84.185 84.820 84.275 ;
        RECT 83.210 83.960 83.530 84.185 ;
        RECT 84.500 83.960 84.820 84.185 ;
        RECT 85.130 83.960 85.360 88.905 ;
        RECT 85.625 88.645 85.945 88.905 ;
        RECT 86.915 88.645 87.235 88.905 ;
        RECT 85.625 88.560 87.235 88.645 ;
        RECT 85.670 88.415 87.190 88.560 ;
        RECT 85.670 87.595 85.900 88.415 ;
        RECT 86.960 87.595 87.190 88.415 ;
        RECT 85.670 87.365 87.190 87.595 ;
        RECT 85.670 87.055 85.900 87.365 ;
        RECT 86.960 87.055 87.190 87.365 ;
        RECT 87.400 87.055 88.040 87.145 ;
        RECT 85.670 86.825 87.190 87.055 ;
        RECT 87.345 86.825 88.095 87.055 ;
        RECT 85.670 86.005 85.900 86.825 ;
        RECT 86.960 86.005 87.190 86.825 ;
        RECT 88.250 86.620 88.490 93.835 ;
        RECT 89.550 93.680 89.780 96.095 ;
        RECT 89.990 96.005 90.630 96.095 ;
        RECT 90.840 95.115 91.070 102.740 ;
        RECT 91.280 101.965 91.920 102.055 ;
        RECT 91.225 101.735 91.975 101.965 ;
        RECT 91.225 96.095 91.975 96.325 ;
        RECT 91.280 96.005 91.920 96.095 ;
        RECT 90.795 93.835 91.115 95.115 ;
        RECT 92.130 93.680 92.360 104.215 ;
        RECT 92.570 101.965 93.210 105.700 ;
        RECT 93.420 104.020 93.650 104.300 ;
        RECT 93.375 102.740 93.695 104.020 ;
        RECT 92.515 101.735 93.265 101.965 ;
        RECT 92.515 96.095 93.265 96.325 ;
        RECT 89.505 93.040 89.825 93.680 ;
        RECT 92.085 93.040 92.405 93.680 ;
        RECT 89.550 92.045 89.780 93.040 ;
        RECT 92.130 92.045 92.360 93.040 ;
        RECT 92.570 92.215 93.210 96.095 ;
        RECT 93.420 95.120 93.650 102.740 ;
        RECT 93.860 101.965 94.500 105.700 ;
        RECT 94.710 104.855 94.940 105.945 ;
        RECT 97.290 104.855 97.520 105.945 ;
        RECT 98.580 104.855 98.810 105.945 ;
        RECT 94.665 104.215 94.985 104.855 ;
        RECT 93.805 101.735 94.555 101.965 ;
        RECT 93.805 96.095 94.555 96.325 ;
        RECT 93.860 95.995 94.500 96.095 ;
        RECT 93.375 93.835 93.695 95.120 ;
        RECT 89.505 91.405 89.825 92.045 ;
        RECT 92.085 91.405 92.405 92.045 ;
        RECT 89.550 90.010 89.780 91.405 ;
        RECT 90.830 91.255 91.060 91.305 ;
        RECT 90.795 90.615 91.115 91.255 ;
        RECT 89.500 89.370 89.820 90.010 ;
        RECT 88.630 88.900 90.680 89.200 ;
        RECT 89.495 88.560 89.815 88.900 ;
        RECT 88.690 87.055 89.330 87.145 ;
        RECT 88.635 86.825 89.385 87.055 ;
        RECT 88.250 86.165 88.480 86.620 ;
        RECT 85.670 85.775 87.190 86.005 ;
        RECT 87.345 85.775 88.095 86.005 ;
        RECT 88.635 85.775 89.385 86.005 ;
        RECT 85.670 85.465 85.900 85.775 ;
        RECT 86.960 85.465 87.190 85.775 ;
        RECT 87.400 85.685 88.040 85.775 ;
        RECT 88.690 85.685 89.330 85.775 ;
        RECT 85.670 85.235 87.190 85.465 ;
        RECT 85.670 84.415 85.900 85.235 ;
        RECT 86.960 84.415 87.190 85.235 ;
        RECT 85.670 84.275 87.190 84.415 ;
        RECT 89.540 84.275 89.770 88.560 ;
        RECT 89.980 87.055 90.620 87.145 ;
        RECT 90.830 87.055 91.060 90.615 ;
        RECT 92.130 90.005 92.360 91.405 ;
        RECT 92.080 89.365 92.400 90.005 ;
        RECT 91.220 88.900 93.270 89.200 ;
        RECT 92.080 88.560 92.400 88.900 ;
        RECT 91.270 87.055 91.910 87.145 ;
        RECT 89.925 86.825 91.965 87.055 ;
        RECT 90.830 86.005 91.060 86.825 ;
        RECT 89.925 85.775 91.965 86.005 ;
        RECT 89.980 85.685 90.620 85.775 ;
        RECT 91.270 85.685 91.910 85.775 ;
        RECT 92.120 84.275 92.350 88.560 ;
        RECT 92.560 87.055 93.200 87.145 ;
        RECT 92.505 86.825 93.255 87.055 ;
        RECT 93.410 86.635 93.650 93.835 ;
        RECT 93.860 92.855 94.495 95.995 ;
        RECT 94.710 93.680 94.940 104.215 ;
        RECT 96.000 104.020 96.230 104.325 ;
        RECT 97.245 104.215 97.565 104.855 ;
        RECT 98.535 104.215 98.855 104.855 ;
        RECT 95.955 102.740 96.275 104.020 ;
        RECT 95.150 101.965 95.790 102.055 ;
        RECT 95.095 101.735 95.845 101.965 ;
        RECT 95.095 96.095 95.845 96.325 ;
        RECT 95.150 96.005 95.790 96.095 ;
        RECT 96.000 95.115 96.230 102.740 ;
        RECT 97.290 102.505 97.520 104.215 ;
        RECT 98.580 102.505 98.810 104.215 ;
        RECT 97.290 102.275 98.810 102.505 ;
        RECT 96.440 101.965 97.080 102.055 ;
        RECT 97.290 101.965 97.520 102.275 ;
        RECT 98.580 101.965 98.810 102.275 ;
        RECT 96.385 101.735 97.135 101.965 ;
        RECT 97.290 101.735 98.810 101.965 ;
        RECT 97.290 96.325 97.520 101.735 ;
        RECT 98.580 96.325 98.810 101.735 ;
        RECT 96.385 96.095 97.135 96.325 ;
        RECT 97.290 96.095 98.810 96.325 ;
        RECT 96.440 96.005 97.080 96.095 ;
        RECT 95.955 93.835 96.275 95.115 ;
        RECT 97.290 93.680 97.520 96.095 ;
        RECT 98.580 95.390 98.810 96.095 ;
        RECT 94.665 93.040 94.985 93.680 ;
        RECT 97.235 93.040 97.555 93.680 ;
        RECT 93.855 92.215 94.495 92.855 ;
        RECT 94.710 92.045 94.940 93.040 ;
        RECT 97.290 92.045 97.520 93.040 ;
        RECT 94.665 91.405 94.985 92.045 ;
        RECT 97.235 91.405 97.555 92.045 ;
        RECT 94.710 90.005 94.940 91.405 ;
        RECT 97.290 90.010 97.520 91.405 ;
        RECT 94.665 89.365 94.985 90.005 ;
        RECT 97.235 89.370 97.555 90.010 ;
        RECT 93.810 88.905 96.865 89.205 ;
        RECT 94.655 88.700 94.975 88.905 ;
        RECT 95.940 88.700 96.260 88.905 ;
        RECT 94.655 88.560 96.260 88.700 ;
        RECT 94.700 88.415 96.220 88.560 ;
        RECT 94.700 87.595 94.930 88.415 ;
        RECT 95.990 87.595 96.220 88.415 ;
        RECT 94.700 87.365 96.220 87.595 ;
        RECT 93.850 87.055 94.490 87.145 ;
        RECT 94.700 87.055 94.930 87.365 ;
        RECT 95.990 87.055 96.220 87.365 ;
        RECT 93.795 86.825 94.545 87.055 ;
        RECT 94.700 86.825 96.220 87.055 ;
        RECT 93.410 86.165 93.640 86.635 ;
        RECT 94.700 86.005 94.930 86.825 ;
        RECT 95.990 86.005 96.220 86.825 ;
        RECT 92.505 85.775 93.255 86.005 ;
        RECT 93.795 85.775 94.545 86.005 ;
        RECT 94.700 85.775 96.220 86.005 ;
        RECT 92.560 85.685 93.200 85.775 ;
        RECT 93.850 85.685 94.490 85.775 ;
        RECT 94.700 85.465 94.930 85.775 ;
        RECT 95.990 85.465 96.220 85.775 ;
        RECT 94.700 85.235 96.220 85.465 ;
        RECT 94.700 84.415 94.930 85.235 ;
        RECT 95.990 84.415 96.220 85.235 ;
        RECT 94.700 84.275 96.220 84.415 ;
        RECT 85.625 84.185 87.230 84.275 ;
        RECT 85.625 83.960 85.945 84.185 ;
        RECT 86.910 83.960 87.230 84.185 ;
        RECT 89.490 83.960 89.810 84.275 ;
        RECT 92.070 83.960 92.390 84.275 ;
        RECT 94.655 84.185 96.265 84.275 ;
        RECT 94.655 83.960 94.975 84.185 ;
        RECT 95.945 83.960 96.265 84.185 ;
        RECT 77.265 83.640 96.265 83.960 ;
        RECT 96.505 83.640 96.865 88.905 ;
        RECT 78.050 83.635 78.370 83.640 ;
        RECT 76.770 80.260 77.090 80.900 ;
        RECT 71.770 76.345 72.090 76.985 ;
        RECT 72.235 76.345 72.555 76.985 ;
        RECT 72.830 76.740 73.420 77.030 ;
        RECT 74.060 76.740 75.060 77.030 ;
        RECT 74.740 76.715 75.060 76.740 ;
        RECT 71.825 73.275 72.055 76.345 ;
        RECT 72.920 76.260 73.540 76.550 ;
        RECT 74.200 76.275 75.245 76.565 ;
        RECT 73.085 75.925 73.345 76.260 ;
        RECT 74.405 75.925 74.635 76.275 ;
        RECT 72.210 75.695 74.635 75.925 ;
        RECT 73.085 74.875 73.345 75.695 ;
        RECT 74.405 74.875 74.635 75.695 ;
        RECT 72.210 74.645 74.635 74.875 ;
        RECT 72.270 73.915 72.910 74.235 ;
        RECT 73.085 74.165 73.345 74.645 ;
        RECT 74.405 74.165 74.635 74.645 ;
        RECT 73.085 73.935 74.635 74.165 ;
        RECT 70.935 70.230 71.575 70.550 ;
        RECT 71.795 70.550 72.055 73.275 ;
        RECT 72.265 72.835 72.905 73.155 ;
        RECT 73.085 73.115 73.345 73.935 ;
        RECT 74.405 73.115 74.635 73.935 ;
        RECT 73.085 72.885 74.635 73.115 ;
        RECT 73.085 72.405 73.345 72.885 ;
        RECT 74.405 72.405 74.635 72.885 ;
        RECT 72.210 72.175 74.635 72.405 ;
        RECT 73.085 71.475 73.345 72.175 ;
        RECT 74.405 71.490 74.635 72.175 ;
        RECT 73.055 71.355 73.375 71.475 ;
        RECT 74.360 71.355 74.680 71.490 ;
        RECT 72.210 71.170 74.680 71.355 ;
        RECT 72.210 71.125 74.685 71.170 ;
        RECT 73.055 70.780 73.375 71.125 ;
        RECT 74.365 70.790 74.685 71.125 ;
        RECT 74.925 70.790 75.245 76.275 ;
        RECT 71.795 70.230 72.115 70.550 ;
        RECT 72.915 70.490 73.505 70.780 ;
        RECT 74.205 70.500 75.245 70.790 ;
        RECT 79.860 70.755 80.180 83.640 ;
        RECT 80.630 83.635 80.950 83.640 ;
        RECT 83.210 83.635 83.530 83.640 ;
        RECT 84.500 83.635 84.820 83.640 ;
        RECT 85.625 83.635 85.945 83.640 ;
        RECT 86.910 83.635 87.230 83.640 ;
        RECT 89.490 83.635 89.810 83.640 ;
        RECT 92.070 83.635 92.390 83.640 ;
        RECT 94.655 83.635 94.975 83.640 ;
        RECT 95.945 83.635 96.265 83.640 ;
        RECT 97.695 81.070 98.755 95.120 ;
        RECT 99.075 89.370 99.835 108.385 ;
        RECT 100.160 108.145 100.390 108.385 ;
        RECT 101.450 108.145 101.680 108.385 ;
        RECT 101.890 108.145 102.530 108.225 ;
        RECT 103.180 108.145 103.820 108.225 ;
        RECT 100.160 107.915 101.680 108.145 ;
        RECT 101.835 107.915 102.585 108.145 ;
        RECT 103.125 107.915 103.875 108.145 ;
        RECT 100.160 106.585 100.390 107.915 ;
        RECT 101.450 106.585 101.680 107.915 ;
        RECT 101.890 107.905 102.530 107.915 ;
        RECT 103.180 107.905 103.820 107.915 ;
        RECT 100.115 105.945 100.435 106.585 ;
        RECT 101.405 105.945 101.725 106.585 ;
        RECT 100.160 104.855 100.390 105.945 ;
        RECT 101.450 104.855 101.680 105.945 ;
        RECT 100.115 104.215 100.435 104.855 ;
        RECT 101.405 104.215 101.725 104.855 ;
        RECT 100.160 93.680 100.390 104.215 ;
        RECT 101.450 93.680 101.680 104.215 ;
        RECT 100.115 93.040 100.435 93.680 ;
        RECT 101.405 93.040 101.725 93.680 ;
        RECT 100.160 92.045 100.390 93.040 ;
        RECT 101.450 92.045 101.680 93.040 ;
        RECT 100.115 91.405 100.435 92.045 ;
        RECT 101.405 91.405 101.725 92.045 ;
        RECT 100.160 90.010 100.390 91.405 ;
        RECT 101.450 90.010 101.680 91.405 ;
        RECT 100.115 89.370 100.435 90.010 ;
        RECT 101.405 89.370 101.725 90.010 ;
        RECT 100.160 83.495 100.390 89.370 ;
        RECT 101.450 83.495 101.680 89.370 ;
        RECT 100.115 82.855 100.435 83.495 ;
        RECT 101.405 82.855 101.725 83.495 ;
        RECT 89.560 80.655 90.200 80.900 ;
        RECT 88.330 80.405 90.435 80.655 ;
        RECT 89.560 80.260 90.200 80.405 ;
        RECT 94.705 79.845 98.755 81.070 ;
        RECT 87.800 78.320 97.500 78.415 ;
        RECT 87.790 78.290 97.510 78.320 ;
        RECT 87.140 78.030 98.000 78.290 ;
        RECT 95.905 76.715 97.185 76.745 ;
        RECT 87.460 76.465 89.565 76.715 ;
        RECT 95.585 76.465 97.690 76.715 ;
        RECT 89.065 72.860 89.385 76.465 ;
        RECT 95.905 76.425 97.185 76.465 ;
        RECT 87.955 72.550 90.050 72.860 ;
        RECT 87.670 71.265 97.520 71.320 ;
        RECT 87.660 71.035 97.530 71.265 ;
        RECT 87.670 71.015 97.520 71.035 ;
        RECT 64.265 69.555 64.585 69.615 ;
        RECT 70.430 69.555 70.750 69.595 ;
        RECT 60.520 69.305 62.625 69.555 ;
        RECT 64.265 69.305 66.370 69.555 ;
        RECT 68.645 69.305 70.750 69.555 ;
        RECT 64.265 69.295 64.585 69.305 ;
        RECT 70.430 69.275 70.750 69.305 ;
        RECT 72.390 69.555 72.710 69.590 ;
        RECT 72.390 69.305 74.495 69.555 ;
        RECT 72.390 69.270 72.710 69.305 ;
        RECT 74.925 69.015 75.245 70.500 ;
        RECT 100.160 61.505 100.390 82.855 ;
        RECT 101.450 61.505 101.680 82.855 ;
        RECT 102.740 77.225 102.970 107.710 ;
        RECT 104.030 106.585 104.260 108.385 ;
        RECT 104.470 108.145 105.110 108.225 ;
        RECT 105.760 108.145 106.400 108.225 ;
        RECT 104.415 107.915 105.165 108.145 ;
        RECT 105.705 107.915 106.455 108.145 ;
        RECT 104.470 107.905 105.110 107.915 ;
        RECT 105.760 107.905 106.400 107.915 ;
        RECT 103.985 105.945 104.305 106.585 ;
        RECT 104.030 104.855 104.260 105.945 ;
        RECT 103.985 104.215 104.305 104.855 ;
        RECT 104.030 93.680 104.260 104.215 ;
        RECT 103.985 93.040 104.305 93.680 ;
        RECT 104.030 92.045 104.260 93.040 ;
        RECT 103.985 91.405 104.305 92.045 ;
        RECT 104.030 90.010 104.260 91.405 ;
        RECT 103.985 89.370 104.305 90.010 ;
        RECT 104.030 83.495 104.260 89.370 ;
        RECT 103.985 82.855 104.305 83.495 ;
        RECT 102.695 76.170 103.015 77.225 ;
        RECT 102.675 73.900 103.035 76.170 ;
        RECT 102.740 61.710 102.970 73.900 ;
        RECT 101.890 61.505 102.530 61.595 ;
        RECT 103.180 61.505 103.820 61.595 ;
        RECT 100.160 61.040 101.680 61.505 ;
        RECT 101.835 61.275 102.585 61.505 ;
        RECT 103.125 61.275 103.875 61.505 ;
        RECT 104.030 61.040 104.260 82.855 ;
        RECT 105.320 77.225 105.550 107.710 ;
        RECT 106.610 106.585 106.840 108.385 ;
        RECT 107.050 108.145 107.690 108.225 ;
        RECT 108.340 108.145 108.980 108.225 ;
        RECT 106.995 107.915 107.745 108.145 ;
        RECT 108.285 107.915 109.035 108.145 ;
        RECT 107.050 107.905 107.690 107.915 ;
        RECT 108.340 107.905 108.980 107.915 ;
        RECT 106.565 105.945 106.885 106.585 ;
        RECT 106.610 104.855 106.840 105.945 ;
        RECT 106.565 104.215 106.885 104.855 ;
        RECT 106.610 93.680 106.840 104.215 ;
        RECT 106.565 93.040 106.885 93.680 ;
        RECT 106.610 92.045 106.840 93.040 ;
        RECT 106.565 91.405 106.885 92.045 ;
        RECT 106.610 90.010 106.840 91.405 ;
        RECT 106.565 89.370 106.885 90.010 ;
        RECT 106.610 83.495 106.840 89.370 ;
        RECT 106.565 82.855 106.885 83.495 ;
        RECT 105.270 76.000 105.590 77.225 ;
        RECT 105.250 73.835 105.610 76.000 ;
        RECT 105.320 61.710 105.550 73.835 ;
        RECT 104.470 61.505 105.110 61.595 ;
        RECT 105.760 61.505 106.400 61.595 ;
        RECT 104.415 61.275 105.165 61.505 ;
        RECT 105.705 61.275 106.455 61.505 ;
        RECT 106.610 61.040 106.840 82.855 ;
        RECT 107.900 77.225 108.130 107.710 ;
        RECT 109.190 106.585 109.420 108.385 ;
        RECT 109.630 108.145 110.270 108.225 ;
        RECT 110.920 108.145 111.560 108.225 ;
        RECT 109.575 107.915 110.325 108.145 ;
        RECT 110.865 107.915 111.615 108.145 ;
        RECT 109.630 107.905 110.270 107.915 ;
        RECT 110.920 107.905 111.560 107.915 ;
        RECT 109.145 105.945 109.465 106.585 ;
        RECT 109.190 104.855 109.420 105.945 ;
        RECT 109.145 104.215 109.465 104.855 ;
        RECT 109.190 93.680 109.420 104.215 ;
        RECT 109.145 93.040 109.465 93.680 ;
        RECT 109.190 92.045 109.420 93.040 ;
        RECT 109.145 91.405 109.465 92.045 ;
        RECT 109.190 90.010 109.420 91.405 ;
        RECT 109.145 89.370 109.465 90.010 ;
        RECT 109.190 83.495 109.420 89.370 ;
        RECT 109.145 82.855 109.465 83.495 ;
        RECT 107.855 75.980 108.175 77.225 ;
        RECT 107.835 73.840 108.195 75.980 ;
        RECT 107.900 61.710 108.130 73.840 ;
        RECT 107.050 61.505 107.690 61.595 ;
        RECT 108.335 61.505 108.975 61.595 ;
        RECT 106.995 61.275 107.745 61.505 ;
        RECT 108.285 61.275 109.035 61.505 ;
        RECT 109.190 61.040 109.420 82.855 ;
        RECT 110.480 77.225 110.710 107.710 ;
        RECT 111.770 106.585 112.000 108.385 ;
        RECT 112.210 108.145 112.850 108.225 ;
        RECT 113.500 108.145 114.140 108.225 ;
        RECT 112.155 107.915 112.905 108.145 ;
        RECT 113.445 107.915 114.195 108.145 ;
        RECT 112.210 107.905 112.850 107.915 ;
        RECT 113.500 107.905 114.140 107.915 ;
        RECT 111.725 105.945 112.045 106.585 ;
        RECT 111.770 104.855 112.000 105.945 ;
        RECT 111.725 104.215 112.045 104.855 ;
        RECT 111.770 93.680 112.000 104.215 ;
        RECT 111.725 93.040 112.045 93.680 ;
        RECT 111.770 92.045 112.000 93.040 ;
        RECT 111.725 91.405 112.045 92.045 ;
        RECT 111.770 90.010 112.000 91.405 ;
        RECT 111.725 89.370 112.045 90.010 ;
        RECT 111.770 83.495 112.000 89.370 ;
        RECT 111.725 82.855 112.045 83.495 ;
        RECT 110.435 75.970 110.755 77.225 ;
        RECT 110.415 73.820 110.775 75.970 ;
        RECT 110.435 73.345 110.755 73.820 ;
        RECT 110.480 61.710 110.710 73.345 ;
        RECT 109.625 61.505 110.265 61.595 ;
        RECT 110.915 61.505 111.555 61.595 ;
        RECT 109.575 61.275 110.325 61.505 ;
        RECT 110.865 61.275 111.615 61.505 ;
        RECT 99.950 61.035 101.890 61.040 ;
        RECT 103.820 61.035 104.460 61.040 ;
        RECT 106.400 61.035 107.055 61.040 ;
        RECT 108.940 61.035 109.580 61.040 ;
        RECT 111.770 61.035 112.000 82.855 ;
        RECT 113.060 77.225 113.290 107.710 ;
        RECT 114.350 106.585 114.580 108.385 ;
        RECT 114.790 108.145 115.430 108.225 ;
        RECT 116.080 108.145 116.720 108.225 ;
        RECT 114.735 107.915 115.485 108.145 ;
        RECT 116.025 107.915 116.775 108.145 ;
        RECT 116.930 107.915 120.880 108.385 ;
        RECT 121.090 108.145 121.730 108.225 ;
        RECT 122.380 108.145 123.020 108.225 ;
        RECT 121.035 107.915 121.785 108.145 ;
        RECT 122.325 107.915 123.075 108.145 ;
        RECT 114.790 107.905 115.430 107.915 ;
        RECT 116.080 107.905 116.720 107.915 ;
        RECT 114.305 105.945 114.625 106.585 ;
        RECT 114.350 104.855 114.580 105.945 ;
        RECT 114.305 104.215 114.625 104.855 ;
        RECT 114.350 93.680 114.580 104.215 ;
        RECT 114.305 93.040 114.625 93.680 ;
        RECT 114.350 92.045 114.580 93.040 ;
        RECT 114.305 91.405 114.625 92.045 ;
        RECT 114.350 90.010 114.580 91.405 ;
        RECT 114.305 89.370 114.625 90.010 ;
        RECT 114.350 83.495 114.580 89.370 ;
        RECT 114.305 82.855 114.625 83.495 ;
        RECT 113.015 75.990 113.335 77.225 ;
        RECT 112.995 73.850 113.355 75.990 ;
        RECT 113.060 61.710 113.290 73.850 ;
        RECT 112.210 61.505 112.850 61.595 ;
        RECT 113.500 61.505 114.140 61.595 ;
        RECT 112.155 61.275 112.905 61.505 ;
        RECT 113.445 61.275 114.195 61.505 ;
        RECT 114.350 61.035 114.580 82.855 ;
        RECT 115.640 77.225 115.870 107.710 ;
        RECT 116.930 106.585 117.160 107.915 ;
        RECT 116.885 105.945 117.205 106.585 ;
        RECT 118.220 106.555 118.450 107.915 ;
        RECT 118.790 106.585 119.020 107.915 ;
        RECT 118.155 105.975 118.515 106.555 ;
        RECT 116.930 104.855 117.160 105.945 ;
        RECT 118.220 104.855 118.450 105.975 ;
        RECT 118.740 105.945 119.060 106.585 ;
        RECT 119.360 106.555 119.590 107.915 ;
        RECT 120.650 106.555 120.880 107.915 ;
        RECT 121.090 107.905 121.730 107.915 ;
        RECT 122.380 107.905 123.020 107.915 ;
        RECT 119.295 105.975 119.655 106.555 ;
        RECT 120.585 105.975 120.945 106.555 ;
        RECT 118.790 104.855 119.020 105.945 ;
        RECT 119.360 104.855 119.590 105.975 ;
        RECT 120.650 104.855 120.880 105.975 ;
        RECT 116.885 104.215 117.205 104.855 ;
        RECT 118.175 104.215 118.495 104.855 ;
        RECT 118.745 104.215 119.065 104.855 ;
        RECT 119.315 104.215 119.635 104.855 ;
        RECT 120.605 104.215 120.925 104.855 ;
        RECT 116.930 93.680 117.160 104.215 ;
        RECT 116.885 93.040 117.205 93.680 ;
        RECT 118.220 93.675 118.450 104.215 ;
        RECT 118.790 93.680 119.020 104.215 ;
        RECT 119.360 93.680 119.590 104.215 ;
        RECT 120.650 93.680 120.880 104.215 ;
        RECT 116.930 92.045 117.160 93.040 ;
        RECT 118.175 93.035 118.495 93.675 ;
        RECT 118.745 93.040 119.065 93.680 ;
        RECT 119.320 93.040 119.640 93.680 ;
        RECT 120.605 93.040 120.925 93.680 ;
        RECT 118.220 92.045 118.450 93.035 ;
        RECT 118.790 92.045 119.020 93.040 ;
        RECT 119.360 92.045 119.590 93.040 ;
        RECT 120.650 92.045 120.880 93.040 ;
        RECT 116.885 91.405 117.205 92.045 ;
        RECT 118.175 91.405 118.495 92.045 ;
        RECT 118.735 91.405 119.055 92.045 ;
        RECT 119.315 91.405 119.635 92.045 ;
        RECT 120.605 91.405 120.925 92.045 ;
        RECT 116.930 90.005 117.160 91.405 ;
        RECT 118.220 90.010 118.450 91.405 ;
        RECT 118.790 90.010 119.020 91.405 ;
        RECT 119.360 90.010 119.590 91.405 ;
        RECT 120.650 90.010 120.880 91.405 ;
        RECT 116.885 89.365 117.205 90.005 ;
        RECT 118.175 89.370 118.495 90.010 ;
        RECT 118.740 89.370 119.060 90.010 ;
        RECT 119.315 89.370 119.635 90.010 ;
        RECT 120.605 89.370 120.925 90.010 ;
        RECT 116.930 83.495 117.160 89.365 ;
        RECT 118.220 83.495 118.450 89.370 ;
        RECT 118.790 83.495 119.020 89.370 ;
        RECT 119.360 83.495 119.590 89.370 ;
        RECT 120.650 83.495 120.880 89.370 ;
        RECT 116.885 82.855 117.205 83.495 ;
        RECT 118.175 82.855 118.495 83.495 ;
        RECT 118.740 82.855 119.060 83.495 ;
        RECT 119.315 82.855 119.635 83.495 ;
        RECT 120.605 82.855 120.925 83.495 ;
        RECT 115.595 75.995 115.915 77.225 ;
        RECT 115.575 73.845 115.935 75.995 ;
        RECT 115.640 61.710 115.870 73.845 ;
        RECT 114.785 61.505 115.425 61.595 ;
        RECT 116.080 61.505 116.720 61.595 ;
        RECT 116.930 61.505 117.160 82.855 ;
        RECT 118.220 74.640 118.450 82.855 ;
        RECT 118.175 73.345 118.495 74.640 ;
        RECT 118.220 61.505 118.450 73.345 ;
        RECT 118.790 61.505 119.020 82.855 ;
        RECT 119.360 61.505 119.590 82.855 ;
        RECT 120.650 61.505 120.880 82.855 ;
        RECT 121.940 77.135 122.170 107.710 ;
        RECT 123.230 106.555 123.460 108.385 ;
        RECT 123.670 108.145 124.310 108.225 ;
        RECT 124.960 108.145 125.600 108.225 ;
        RECT 123.615 107.915 124.365 108.145 ;
        RECT 124.905 107.915 125.655 108.145 ;
        RECT 123.670 107.905 124.310 107.915 ;
        RECT 124.960 107.905 125.600 107.915 ;
        RECT 123.165 105.975 123.525 106.555 ;
        RECT 123.230 104.855 123.460 105.975 ;
        RECT 123.185 104.215 123.505 104.855 ;
        RECT 123.230 93.680 123.460 104.215 ;
        RECT 123.185 93.040 123.505 93.680 ;
        RECT 123.230 92.045 123.460 93.040 ;
        RECT 123.185 91.405 123.505 92.045 ;
        RECT 123.230 90.010 123.460 91.405 ;
        RECT 123.185 89.370 123.505 90.010 ;
        RECT 123.230 83.495 123.460 89.370 ;
        RECT 123.185 82.855 123.505 83.495 ;
        RECT 121.875 75.870 122.235 77.135 ;
        RECT 121.940 61.710 122.170 75.870 ;
        RECT 121.090 61.505 121.730 61.595 ;
        RECT 122.380 61.505 123.020 61.595 ;
        RECT 114.735 61.275 115.485 61.505 ;
        RECT 116.025 61.275 116.775 61.505 ;
        RECT 116.930 61.035 120.880 61.505 ;
        RECT 121.035 61.275 121.785 61.505 ;
        RECT 122.325 61.275 123.075 61.505 ;
        RECT 123.230 61.035 123.460 82.855 ;
        RECT 124.520 77.120 124.750 107.710 ;
        RECT 125.810 106.555 126.040 108.385 ;
        RECT 126.250 108.145 126.890 108.225 ;
        RECT 127.540 108.145 128.180 108.225 ;
        RECT 126.195 107.915 126.945 108.145 ;
        RECT 127.485 107.915 128.235 108.145 ;
        RECT 126.250 107.905 126.890 107.915 ;
        RECT 127.540 107.905 128.180 107.915 ;
        RECT 125.745 105.975 126.105 106.555 ;
        RECT 125.810 104.855 126.040 105.975 ;
        RECT 125.765 104.215 126.085 104.855 ;
        RECT 125.810 93.680 126.040 104.215 ;
        RECT 125.765 93.040 126.085 93.680 ;
        RECT 125.810 92.045 126.040 93.040 ;
        RECT 125.765 91.405 126.085 92.045 ;
        RECT 125.810 90.010 126.040 91.405 ;
        RECT 125.765 89.370 126.085 90.010 ;
        RECT 125.810 83.495 126.040 89.370 ;
        RECT 125.765 82.855 126.085 83.495 ;
        RECT 124.455 75.870 124.815 77.120 ;
        RECT 124.520 61.710 124.750 75.870 ;
        RECT 123.670 61.505 124.310 61.595 ;
        RECT 124.960 61.505 125.600 61.595 ;
        RECT 123.615 61.275 124.365 61.505 ;
        RECT 124.905 61.275 125.655 61.505 ;
        RECT 124.465 61.035 125.105 61.040 ;
        RECT 125.810 61.035 126.040 82.855 ;
        RECT 127.100 77.135 127.330 107.710 ;
        RECT 128.390 106.555 128.620 108.385 ;
        RECT 128.830 108.145 129.470 108.225 ;
        RECT 130.120 108.145 130.760 108.225 ;
        RECT 128.775 107.915 129.525 108.145 ;
        RECT 130.065 107.915 130.815 108.145 ;
        RECT 128.830 107.905 129.470 107.915 ;
        RECT 130.120 107.905 130.760 107.915 ;
        RECT 128.325 105.975 128.685 106.555 ;
        RECT 128.390 104.855 128.620 105.975 ;
        RECT 128.345 104.215 128.665 104.855 ;
        RECT 128.390 93.680 128.620 104.215 ;
        RECT 128.345 93.040 128.665 93.680 ;
        RECT 128.390 92.045 128.620 93.040 ;
        RECT 128.345 91.405 128.665 92.045 ;
        RECT 128.390 90.010 128.620 91.405 ;
        RECT 128.345 89.370 128.665 90.010 ;
        RECT 128.390 83.495 128.620 89.370 ;
        RECT 128.345 82.855 128.665 83.495 ;
        RECT 127.035 75.870 127.395 77.135 ;
        RECT 127.100 61.710 127.330 75.870 ;
        RECT 126.250 61.505 126.890 61.595 ;
        RECT 127.540 61.505 128.180 61.595 ;
        RECT 126.195 61.275 126.945 61.505 ;
        RECT 127.485 61.275 128.235 61.505 ;
        RECT 127.045 61.035 127.685 61.040 ;
        RECT 128.390 61.035 128.620 82.855 ;
        RECT 129.680 77.135 129.910 107.710 ;
        RECT 130.970 106.555 131.200 108.385 ;
        RECT 131.410 108.145 132.050 108.225 ;
        RECT 132.700 108.145 133.340 108.225 ;
        RECT 131.355 107.915 132.105 108.145 ;
        RECT 132.645 107.915 133.395 108.145 ;
        RECT 131.410 107.905 132.050 107.915 ;
        RECT 132.700 107.905 133.340 107.915 ;
        RECT 130.905 105.975 131.265 106.555 ;
        RECT 130.970 104.855 131.200 105.975 ;
        RECT 130.925 104.215 131.245 104.855 ;
        RECT 130.970 93.680 131.200 104.215 ;
        RECT 130.925 93.040 131.245 93.680 ;
        RECT 130.970 92.045 131.200 93.040 ;
        RECT 130.925 91.405 131.245 92.045 ;
        RECT 130.970 90.010 131.200 91.405 ;
        RECT 130.925 89.370 131.245 90.010 ;
        RECT 130.970 83.495 131.200 89.370 ;
        RECT 130.925 82.855 131.245 83.495 ;
        RECT 129.615 75.870 129.975 77.135 ;
        RECT 129.680 61.710 129.910 75.870 ;
        RECT 128.830 61.505 129.470 61.595 ;
        RECT 130.120 61.505 130.760 61.595 ;
        RECT 128.775 61.275 129.525 61.505 ;
        RECT 130.065 61.275 130.815 61.505 ;
        RECT 129.625 61.035 130.265 61.040 ;
        RECT 130.970 61.035 131.200 82.855 ;
        RECT 132.260 77.155 132.490 107.710 ;
        RECT 133.550 106.555 133.780 108.385 ;
        RECT 133.990 108.145 134.630 108.225 ;
        RECT 135.280 108.145 135.920 108.225 ;
        RECT 133.935 107.915 134.685 108.145 ;
        RECT 135.225 107.915 135.975 108.145 ;
        RECT 133.990 107.905 134.630 107.915 ;
        RECT 135.280 107.905 135.920 107.915 ;
        RECT 133.485 105.975 133.845 106.555 ;
        RECT 133.550 104.855 133.780 105.975 ;
        RECT 133.505 104.215 133.825 104.855 ;
        RECT 133.550 93.680 133.780 104.215 ;
        RECT 133.505 93.040 133.825 93.680 ;
        RECT 133.550 92.045 133.780 93.040 ;
        RECT 133.505 91.405 133.825 92.045 ;
        RECT 133.550 90.010 133.780 91.405 ;
        RECT 133.505 89.370 133.825 90.010 ;
        RECT 133.550 83.495 133.780 89.370 ;
        RECT 133.505 82.855 133.825 83.495 ;
        RECT 132.195 75.870 132.555 77.155 ;
        RECT 132.260 61.710 132.490 75.870 ;
        RECT 131.410 61.505 132.050 61.595 ;
        RECT 132.700 61.505 133.340 61.595 ;
        RECT 131.355 61.275 132.105 61.505 ;
        RECT 132.645 61.275 133.395 61.505 ;
        RECT 132.210 61.035 132.850 61.040 ;
        RECT 133.550 61.035 133.780 82.855 ;
        RECT 134.840 77.140 135.070 107.710 ;
        RECT 136.130 106.555 136.360 108.385 ;
        RECT 136.570 108.145 137.210 108.225 ;
        RECT 136.515 107.915 137.265 108.145 ;
        RECT 137.420 107.915 138.940 108.145 ;
        RECT 136.570 107.905 137.210 107.915 ;
        RECT 136.065 105.975 136.425 106.555 ;
        RECT 136.130 104.855 136.360 105.975 ;
        RECT 136.085 104.215 136.405 104.855 ;
        RECT 136.130 93.680 136.360 104.215 ;
        RECT 136.085 93.040 136.405 93.680 ;
        RECT 136.130 92.045 136.360 93.040 ;
        RECT 136.085 91.405 136.405 92.045 ;
        RECT 136.130 90.010 136.360 91.405 ;
        RECT 136.085 89.370 136.405 90.010 ;
        RECT 136.130 83.495 136.360 89.370 ;
        RECT 136.085 82.855 136.405 83.495 ;
        RECT 134.775 75.870 135.135 77.140 ;
        RECT 134.840 61.710 135.070 75.870 ;
        RECT 133.990 61.505 134.630 61.595 ;
        RECT 135.280 61.505 135.920 61.595 ;
        RECT 133.935 61.275 134.685 61.505 ;
        RECT 135.225 61.275 135.975 61.505 ;
        RECT 136.130 61.035 136.360 82.855 ;
        RECT 137.420 77.125 137.650 107.915 ;
        RECT 138.710 77.135 138.940 107.915 ;
        RECT 137.355 75.870 137.715 77.125 ;
        RECT 138.645 75.875 139.005 77.135 ;
        RECT 136.570 61.505 137.210 61.595 ;
        RECT 137.420 61.505 137.650 75.870 ;
        RECT 138.710 61.505 138.940 75.875 ;
        RECT 136.515 61.275 137.265 61.505 ;
        RECT 137.420 61.275 138.940 61.505 ;
        RECT 99.950 60.720 139.060 61.035 ;
      LAYER met2 ;
        RECT 6.845 215.705 8.700 215.725 ;
        RECT 6.770 215.185 42.965 215.705 ;
        RECT 6.845 215.175 8.700 215.185 ;
        RECT 42.600 213.380 48.225 214.340 ;
        RECT 60.320 214.165 140.320 214.600 ;
        RECT 60.320 213.830 101.755 214.165 ;
        RECT 102.040 214.160 140.320 214.165 ;
        RECT 102.455 213.540 138.230 214.020 ;
        RECT 75.035 212.610 85.675 213.250 ;
        RECT 43.405 212.560 43.680 212.570 ;
        RECT 8.755 210.405 42.695 211.730 ;
        RECT 43.370 209.605 53.005 212.560 ;
        RECT 78.905 212.380 79.225 212.385 ;
        RECT 119.045 212.380 119.305 212.400 ;
        RECT 120.185 212.380 120.445 212.400 ;
        RECT 121.475 212.380 121.735 212.400 ;
        RECT 124.055 212.380 124.315 212.400 ;
        RECT 126.635 212.380 126.895 212.400 ;
        RECT 129.215 212.380 129.475 212.400 ;
        RECT 131.795 212.380 132.055 212.400 ;
        RECT 134.375 212.380 134.635 212.400 ;
        RECT 60.320 211.740 140.320 212.380 ;
        RECT 119.045 211.720 119.305 211.740 ;
        RECT 120.185 211.720 120.445 211.740 ;
        RECT 121.475 211.720 121.735 211.740 ;
        RECT 124.055 211.720 124.315 211.740 ;
        RECT 126.635 211.720 126.895 211.740 ;
        RECT 129.215 211.720 129.475 211.740 ;
        RECT 131.795 211.720 132.055 211.740 ;
        RECT 134.375 211.720 134.635 211.740 ;
        RECT 72.455 210.855 95.340 211.495 ;
        RECT 60.320 210.010 140.320 210.650 ;
        RECT 43.405 209.565 43.680 209.605 ;
        RECT 64.865 209.145 86.475 209.785 ;
        RECT 64.910 209.140 86.475 209.145 ;
        RECT 62.720 207.535 67.280 207.855 ;
        RECT 71.650 207.850 72.340 209.140 ;
        RECT 78.725 207.850 79.415 209.140 ;
        RECT 85.785 207.850 86.475 209.140 ;
        RECT 91.635 208.535 134.600 209.870 ;
        RECT 90.830 207.850 97.910 207.860 ;
        RECT 62.770 207.530 63.410 207.535 ;
        RECT 64.060 207.530 64.700 207.535 ;
        RECT 65.350 207.530 65.990 207.535 ;
        RECT 66.635 207.530 67.275 207.535 ;
        RECT 71.650 207.530 86.480 207.850 ;
        RECT 90.830 207.530 97.920 207.850 ;
        RECT 62.770 201.805 67.280 202.125 ;
        RECT 64.060 201.800 64.700 201.805 ;
        RECT 65.350 201.800 65.990 201.805 ;
        RECT 66.640 201.800 67.280 201.805 ;
        RECT 71.650 201.800 86.480 202.120 ;
        RECT 71.650 200.520 72.340 201.800 ;
        RECT 78.755 200.520 79.445 201.800 ;
        RECT 85.790 200.520 86.480 201.800 ;
        RECT 90.815 201.790 97.920 202.120 ;
        RECT 89.060 200.910 134.600 200.915 ;
        RECT 64.865 199.880 86.480 200.520 ;
        RECT 64.910 199.875 86.480 199.880 ;
        RECT 89.055 199.630 134.600 200.910 ;
        RECT 60.320 198.835 140.320 199.475 ;
        RECT 119.015 198.830 119.335 198.835 ;
        RECT 72.455 198.010 95.335 198.650 ;
        RECT 60.320 197.200 140.320 197.840 ;
        RECT 8.755 195.705 12.890 196.665 ;
        RECT 75.035 196.410 91.955 197.050 ;
        RECT 60.320 195.165 140.320 195.805 ;
        RECT 60.320 195.135 60.740 195.165 ;
        RECT 92.920 195.160 93.240 195.165 ;
        RECT 95.505 195.160 95.825 195.165 ;
        RECT 117.725 195.160 118.045 195.165 ;
        RECT 63.575 194.995 63.895 195.000 ;
        RECT 8.755 194.340 43.015 194.880 ;
        RECT 60.320 194.355 140.320 194.995 ;
        RECT 55.775 193.080 65.185 194.150 ;
        RECT 55.775 193.075 60.800 193.080 ;
        RECT 64.865 192.940 65.185 193.080 ;
        RECT 62.770 192.620 63.410 192.940 ;
        RECT 64.060 192.620 65.990 192.940 ;
        RECT 66.640 192.620 67.280 192.940 ;
        RECT 64.820 191.800 65.120 192.620 ;
        RECT 71.640 192.590 83.890 192.960 ;
        RECT 88.240 192.620 95.330 192.940 ;
        RECT 62.770 191.480 63.410 191.800 ;
        RECT 64.060 191.480 65.990 191.800 ;
        RECT 66.640 191.480 67.280 191.800 ;
        RECT 71.640 191.455 83.890 191.825 ;
        RECT 88.240 191.480 95.330 191.800 ;
        RECT 63.575 190.285 83.085 190.935 ;
        RECT 60.320 189.430 140.320 190.070 ;
        RECT 60.320 188.650 140.320 189.290 ;
        RECT 60.355 188.630 60.750 188.650 ;
        RECT 61.155 188.645 61.475 188.650 ;
        RECT 64.290 188.645 64.610 188.650 ;
        RECT 75.580 188.645 75.900 188.650 ;
        RECT 67.440 187.635 83.750 188.275 ;
        RECT 63.490 186.425 68.585 186.745 ;
        RECT 77.610 186.055 91.045 186.695 ;
        RECT 63.450 185.005 68.585 185.325 ;
        RECT 72.875 183.710 73.615 185.410 ;
        RECT 60.320 182.930 76.340 183.570 ;
        RECT 80.700 183.390 140.320 184.350 ;
        RECT 80.700 183.380 87.400 183.390 ;
        RECT 88.150 183.380 140.320 183.390 ;
        RECT 67.440 182.100 68.520 182.740 ;
        RECT 72.610 182.140 73.395 182.780 ;
        RECT 62.885 181.275 90.225 181.915 ;
        RECT 96.425 181.740 153.265 183.020 ;
        RECT 62.900 180.270 63.655 181.050 ;
        RECT 62.900 179.810 63.650 180.270 ;
        RECT 64.245 180.080 66.715 180.100 ;
        RECT 64.245 179.780 66.730 180.080 ;
        RECT 66.090 179.760 66.730 179.780 ;
        RECT 68.675 179.710 73.750 180.030 ;
        RECT 66.105 178.850 66.745 178.880 ;
        RECT 62.900 177.580 63.650 178.820 ;
        RECT 64.245 178.530 66.745 178.850 ;
        RECT 68.670 178.630 73.745 178.950 ;
        RECT 73.965 178.150 140.320 178.820 ;
        RECT 60.320 177.220 136.780 177.350 ;
        RECT 60.320 176.550 140.320 177.220 ;
        RECT 63.800 176.020 65.425 176.340 ;
        RECT 65.105 175.090 65.425 176.020 ;
        RECT 71.270 176.025 72.415 176.345 ;
        RECT 72.635 176.025 73.550 176.345 ;
        RECT 71.270 175.070 71.590 176.025 ;
        RECT 73.230 175.065 73.550 176.025 ;
        RECT 102.460 167.070 138.230 167.480 ;
        RECT 100.280 166.410 140.320 166.835 ;
        RECT 59.480 108.370 139.480 108.805 ;
        RECT 59.480 108.035 100.915 108.370 ;
        RECT 101.200 108.365 139.480 108.370 ;
        RECT 101.615 107.745 137.390 108.225 ;
        RECT 74.195 106.815 84.835 107.455 ;
        RECT 78.065 106.585 78.385 106.590 ;
        RECT 118.205 106.585 118.465 106.605 ;
        RECT 119.345 106.585 119.605 106.605 ;
        RECT 120.635 106.585 120.895 106.605 ;
        RECT 123.215 106.585 123.475 106.605 ;
        RECT 125.795 106.585 126.055 106.605 ;
        RECT 128.375 106.585 128.635 106.605 ;
        RECT 130.955 106.585 131.215 106.605 ;
        RECT 133.535 106.585 133.795 106.605 ;
        RECT 59.480 105.945 139.480 106.585 ;
        RECT 118.205 105.925 118.465 105.945 ;
        RECT 119.345 105.925 119.605 105.945 ;
        RECT 120.635 105.925 120.895 105.945 ;
        RECT 123.215 105.925 123.475 105.945 ;
        RECT 125.795 105.925 126.055 105.945 ;
        RECT 128.375 105.925 128.635 105.945 ;
        RECT 130.955 105.925 131.215 105.945 ;
        RECT 133.535 105.925 133.795 105.945 ;
        RECT 71.615 105.060 94.500 105.700 ;
        RECT 59.480 104.215 139.480 104.855 ;
        RECT 64.025 103.350 85.635 103.990 ;
        RECT 64.070 103.345 85.635 103.350 ;
        RECT 61.880 101.740 66.440 102.060 ;
        RECT 70.810 102.055 71.500 103.345 ;
        RECT 77.885 102.055 78.575 103.345 ;
        RECT 84.945 102.055 85.635 103.345 ;
        RECT 90.795 102.740 133.760 104.075 ;
        RECT 89.990 102.055 97.070 102.065 ;
        RECT 61.930 101.735 62.570 101.740 ;
        RECT 63.220 101.735 63.860 101.740 ;
        RECT 64.510 101.735 65.150 101.740 ;
        RECT 65.795 101.735 66.435 101.740 ;
        RECT 70.810 101.735 85.640 102.055 ;
        RECT 89.990 101.735 97.080 102.055 ;
        RECT 61.930 96.010 66.440 96.330 ;
        RECT 63.220 96.005 63.860 96.010 ;
        RECT 64.510 96.005 65.150 96.010 ;
        RECT 65.800 96.005 66.440 96.010 ;
        RECT 70.810 96.005 85.640 96.325 ;
        RECT 70.810 94.725 71.500 96.005 ;
        RECT 77.915 94.725 78.605 96.005 ;
        RECT 84.950 94.725 85.640 96.005 ;
        RECT 89.975 95.995 97.080 96.325 ;
        RECT 88.220 95.115 133.760 95.120 ;
        RECT 64.025 94.085 85.640 94.725 ;
        RECT 64.070 94.080 85.640 94.085 ;
        RECT 88.215 93.835 133.760 95.115 ;
        RECT 59.480 93.040 139.480 93.680 ;
        RECT 118.175 93.035 118.495 93.040 ;
        RECT 71.615 92.215 94.495 92.855 ;
        RECT 59.480 91.405 139.480 92.045 ;
        RECT 74.195 90.615 91.115 91.255 ;
        RECT 59.480 89.370 139.480 90.010 ;
        RECT 59.480 89.340 59.900 89.370 ;
        RECT 92.080 89.365 92.400 89.370 ;
        RECT 94.665 89.365 94.985 89.370 ;
        RECT 116.885 89.365 117.205 89.370 ;
        RECT 62.735 89.200 63.055 89.205 ;
        RECT 59.480 88.560 139.480 89.200 ;
        RECT 55.775 87.285 64.345 88.355 ;
        RECT 55.775 87.280 60.795 87.285 ;
        RECT 55.775 87.255 59.565 87.280 ;
        RECT 64.025 87.145 64.345 87.285 ;
        RECT 61.930 86.825 62.570 87.145 ;
        RECT 63.220 86.825 65.150 87.145 ;
        RECT 65.800 86.825 66.440 87.145 ;
        RECT 63.980 86.005 64.280 86.825 ;
        RECT 70.800 86.795 83.050 87.165 ;
        RECT 87.400 86.825 94.490 87.145 ;
        RECT 61.930 85.685 62.570 86.005 ;
        RECT 63.220 85.685 65.150 86.005 ;
        RECT 65.800 85.685 66.440 86.005 ;
        RECT 70.800 85.660 83.050 86.030 ;
        RECT 87.400 85.685 94.490 86.005 ;
        RECT 62.735 84.490 82.245 85.140 ;
        RECT 59.480 83.635 139.480 84.275 ;
        RECT 59.480 82.855 139.480 83.495 ;
        RECT 60.315 82.850 60.635 82.855 ;
        RECT 63.450 82.850 63.770 82.855 ;
        RECT 74.740 82.850 75.060 82.855 ;
        RECT 66.600 81.840 82.910 82.480 ;
        RECT 62.650 80.630 67.745 80.950 ;
        RECT 76.770 80.260 90.205 80.900 ;
        RECT 62.610 79.210 67.745 79.530 ;
        RECT 72.035 77.915 72.775 79.615 ;
        RECT 59.480 77.135 75.500 77.775 ;
        RECT 79.860 77.595 139.480 78.555 ;
        RECT 79.860 77.585 86.560 77.595 ;
        RECT 87.310 77.585 139.480 77.595 ;
        RECT 66.600 76.305 67.680 76.945 ;
        RECT 71.770 76.345 72.555 76.985 ;
        RECT 62.045 75.480 89.385 76.120 ;
        RECT 95.585 75.945 148.495 77.225 ;
        RECT 62.060 74.475 62.815 75.255 ;
        RECT 62.060 74.015 62.810 74.475 ;
        RECT 63.405 74.285 65.875 74.305 ;
        RECT 63.405 73.985 65.890 74.285 ;
        RECT 65.250 73.965 65.890 73.985 ;
        RECT 67.835 73.915 72.910 74.235 ;
        RECT 65.265 73.055 65.905 73.085 ;
        RECT 62.060 71.785 62.810 73.025 ;
        RECT 63.405 72.735 65.905 73.055 ;
        RECT 67.830 72.835 72.905 73.155 ;
        RECT 73.125 72.355 139.480 73.025 ;
        RECT 59.480 71.425 135.940 71.555 ;
        RECT 59.480 70.755 139.480 71.425 ;
        RECT 62.960 70.225 64.585 70.545 ;
        RECT 64.265 69.295 64.585 70.225 ;
        RECT 70.430 70.230 71.575 70.550 ;
        RECT 71.795 70.230 72.710 70.550 ;
        RECT 70.430 69.275 70.750 70.230 ;
        RECT 72.390 69.270 72.710 70.230 ;
        RECT 101.620 61.275 137.390 61.685 ;
        RECT 99.440 60.615 139.480 61.040 ;
      LAYER met3 ;
        RECT 6.795 215.190 8.750 215.735 ;
        RECT 46.205 213.380 48.225 220.105 ;
        RECT 51.050 210.420 52.960 212.490 ;
        RECT 60.320 195.365 60.785 214.600 ;
        RECT 61.085 195.365 61.550 214.600 ;
        RECT 61.850 195.365 62.315 214.600 ;
        RECT 62.615 195.365 63.080 214.600 ;
        RECT 63.380 195.365 63.845 214.600 ;
        RECT 64.145 195.365 64.610 214.600 ;
        RECT 64.910 195.365 65.375 214.600 ;
        RECT 65.675 195.365 66.140 214.600 ;
        RECT 66.440 195.365 66.905 214.600 ;
        RECT 67.205 195.365 67.670 214.600 ;
        RECT 67.970 195.365 68.435 214.600 ;
        RECT 68.735 195.365 69.200 214.600 ;
        RECT 69.500 195.365 69.965 214.600 ;
        RECT 70.265 195.365 70.730 214.600 ;
        RECT 71.030 195.365 71.495 214.600 ;
        RECT 71.795 195.365 72.260 214.600 ;
        RECT 72.560 195.365 73.025 214.600 ;
        RECT 73.325 195.365 73.790 214.600 ;
        RECT 74.090 195.365 74.555 214.600 ;
        RECT 74.855 195.365 75.320 214.600 ;
        RECT 75.620 195.365 76.085 214.600 ;
        RECT 76.385 195.365 76.850 214.600 ;
        RECT 77.150 195.365 77.615 214.600 ;
        RECT 77.915 210.395 78.380 214.600 ;
        RECT 78.680 210.395 79.145 214.600 ;
        RECT 79.445 210.395 79.910 214.600 ;
        RECT 78.225 195.230 79.910 209.785 ;
        RECT 80.210 195.365 80.675 214.600 ;
        RECT 80.975 195.365 81.440 214.600 ;
        RECT 81.740 195.365 82.205 214.600 ;
        RECT 82.505 195.365 82.970 214.600 ;
        RECT 83.270 195.365 83.735 214.600 ;
        RECT 84.035 195.365 84.500 214.600 ;
        RECT 84.800 195.365 85.265 214.600 ;
        RECT 85.565 195.365 86.030 214.600 ;
        RECT 86.330 195.365 86.795 214.600 ;
        RECT 87.095 195.365 87.560 214.600 ;
        RECT 87.860 195.365 88.325 214.600 ;
        RECT 88.625 195.365 89.090 214.600 ;
        RECT 89.390 195.365 89.855 214.600 ;
        RECT 90.155 195.365 90.620 214.600 ;
        RECT 90.920 195.365 91.385 214.600 ;
        RECT 91.685 195.365 92.150 214.600 ;
        RECT 92.450 195.365 92.915 214.600 ;
        RECT 93.215 195.365 93.680 214.600 ;
        RECT 93.980 195.365 94.445 214.600 ;
        RECT 94.745 195.365 95.210 214.600 ;
        RECT 95.510 195.365 95.975 214.600 ;
        RECT 96.275 195.365 96.740 214.600 ;
        RECT 97.040 195.365 97.505 214.600 ;
        RECT 55.780 193.100 57.775 193.715 ;
        RECT 60.320 192.795 60.785 195.060 ;
        RECT 6.770 189.900 60.785 192.795 ;
        RECT 60.320 189.430 60.785 189.900 ;
        RECT 61.085 189.430 61.550 195.060 ;
        RECT 61.850 189.430 62.315 195.060 ;
        RECT 62.615 193.855 63.080 195.060 ;
        RECT 60.320 182.930 60.785 189.130 ;
        RECT 61.085 182.930 61.550 189.060 ;
        RECT 61.850 182.930 62.315 189.060 ;
        RECT 8.755 180.435 54.945 180.440 ;
        RECT 60.320 180.435 60.785 182.295 ;
        RECT 6.770 177.540 60.785 180.435 ;
        RECT 60.320 174.400 60.785 177.540 ;
        RECT 61.085 174.400 61.550 182.295 ;
        RECT 61.850 174.400 62.315 182.295 ;
        RECT 62.885 181.275 63.290 192.965 ;
        RECT 63.590 189.430 64.055 195.060 ;
        RECT 64.355 189.430 64.820 195.060 ;
        RECT 65.120 189.430 65.585 195.060 ;
        RECT 65.885 189.430 66.350 195.060 ;
        RECT 66.650 193.860 67.115 195.060 ;
        RECT 63.590 182.930 64.055 189.060 ;
        RECT 64.355 182.930 64.820 189.060 ;
        RECT 65.120 182.930 65.585 189.060 ;
        RECT 65.885 182.930 66.350 189.060 ;
        RECT 62.710 174.400 63.175 180.795 ;
        RECT 63.590 174.400 64.055 182.295 ;
        RECT 64.355 174.400 64.820 182.295 ;
        RECT 65.120 174.400 65.585 182.295 ;
        RECT 65.885 174.400 66.350 182.295 ;
        RECT 66.755 181.275 67.160 192.965 ;
        RECT 67.460 189.430 67.925 195.060 ;
        RECT 68.225 189.430 68.690 195.060 ;
        RECT 68.990 189.430 69.455 195.060 ;
        RECT 69.755 189.430 70.220 195.060 ;
        RECT 70.520 189.430 70.985 195.060 ;
        RECT 71.640 193.860 72.105 195.060 ;
        RECT 67.460 182.930 67.925 189.060 ;
        RECT 68.225 182.930 68.690 189.060 ;
        RECT 68.990 182.930 69.455 189.060 ;
        RECT 69.755 182.930 70.220 189.060 ;
        RECT 70.520 182.930 70.985 189.060 ;
        RECT 71.775 187.635 72.145 192.960 ;
        RECT 72.815 189.430 73.280 195.060 ;
        RECT 73.580 189.430 74.045 195.060 ;
        RECT 74.345 189.430 74.810 195.060 ;
        RECT 75.110 189.430 75.575 195.060 ;
        RECT 75.875 189.430 76.340 195.060 ;
        RECT 76.640 189.430 77.105 195.060 ;
        RECT 77.405 189.430 77.870 195.060 ;
        RECT 71.285 182.930 71.750 186.810 ;
        RECT 72.050 182.930 72.515 186.810 ;
        RECT 72.815 182.930 73.280 189.060 ;
        RECT 73.580 182.930 74.045 189.060 ;
        RECT 74.345 182.930 74.810 189.060 ;
        RECT 75.110 182.930 75.575 189.060 ;
        RECT 75.875 182.930 76.340 189.060 ;
        RECT 66.650 174.400 67.115 180.795 ;
        RECT 67.460 174.400 67.925 182.295 ;
        RECT 68.225 174.400 68.690 182.295 ;
        RECT 68.990 174.400 69.455 182.295 ;
        RECT 69.755 174.400 70.220 182.295 ;
        RECT 70.520 174.400 70.985 182.295 ;
        RECT 71.285 174.400 71.750 182.295 ;
        RECT 72.050 174.400 72.515 182.295 ;
        RECT 72.815 174.400 73.280 182.295 ;
        RECT 73.580 174.400 74.045 182.295 ;
        RECT 74.345 174.400 74.810 182.295 ;
        RECT 75.110 174.400 75.575 182.295 ;
        RECT 75.875 174.400 76.340 182.295 ;
        RECT 78.225 164.315 79.905 195.230 ;
        RECT 97.805 195.165 98.270 214.600 ;
        RECT 98.570 195.165 99.035 214.600 ;
        RECT 99.335 195.165 99.800 214.600 ;
        RECT 100.100 195.165 100.925 214.600 ;
        RECT 80.205 189.430 80.670 195.060 ;
        RECT 80.970 189.430 81.435 195.060 ;
        RECT 81.735 189.430 82.200 195.060 ;
        RECT 82.500 189.430 82.965 195.060 ;
        RECT 83.280 193.860 83.745 195.060 ;
        RECT 83.380 191.825 83.750 192.960 ;
        RECT 83.375 191.455 83.750 191.825 ;
        RECT 83.380 187.635 83.750 191.455 ;
        RECT 84.050 189.430 84.515 195.060 ;
        RECT 84.815 189.430 85.280 195.060 ;
        RECT 85.580 189.430 86.045 195.060 ;
        RECT 86.345 189.430 86.810 195.060 ;
        RECT 87.110 189.430 87.575 195.060 ;
        RECT 87.875 189.430 88.340 195.060 ;
        RECT 88.640 189.430 89.105 195.060 ;
        RECT 89.405 189.430 89.870 195.060 ;
        RECT 90.170 189.430 90.635 195.060 ;
        RECT 90.935 189.430 91.400 195.060 ;
        RECT 91.700 189.430 92.165 195.060 ;
        RECT 92.465 189.430 92.930 195.060 ;
        RECT 93.230 189.430 93.695 195.060 ;
        RECT 93.995 189.430 94.460 195.060 ;
        RECT 94.760 189.430 95.225 195.060 ;
        RECT 95.525 189.430 95.990 195.060 ;
        RECT 96.290 189.430 96.755 195.060 ;
        RECT 97.055 189.430 97.520 195.060 ;
        RECT 100.460 166.410 100.925 195.165 ;
        RECT 101.225 166.410 101.690 214.600 ;
        RECT 102.470 167.070 103.630 214.020 ;
        RECT 104.285 166.410 104.750 214.600 ;
        RECT 105.050 167.070 106.280 214.020 ;
        RECT 106.580 166.410 107.045 214.600 ;
        RECT 107.345 166.410 107.810 214.600 ;
        RECT 108.110 166.410 108.575 214.600 ;
        RECT 108.875 166.410 109.340 214.600 ;
        RECT 109.640 166.410 110.105 214.600 ;
        RECT 110.405 183.350 110.880 214.600 ;
        RECT 111.180 183.345 111.655 214.600 ;
        RECT 111.955 183.345 112.430 214.600 ;
        RECT 112.730 183.345 113.205 214.600 ;
        RECT 113.510 183.345 114.090 214.600 ;
        RECT 59.555 150.590 75.415 162.990 ;
        RECT 76.615 150.590 92.475 162.990 ;
        RECT 93.675 150.590 109.535 162.990 ;
        RECT 59.555 136.990 75.415 149.390 ;
        RECT 76.615 136.990 92.475 149.390 ;
        RECT 93.675 136.990 109.535 149.390 ;
        RECT 59.555 123.390 75.415 135.790 ;
        RECT 76.615 123.390 92.475 135.790 ;
        RECT 93.675 123.390 109.535 135.790 ;
        RECT 110.570 120.600 112.250 183.020 ;
        RECT 112.550 120.600 114.230 183.020 ;
        RECT 114.530 166.410 114.995 214.600 ;
        RECT 115.295 166.410 115.760 214.600 ;
        RECT 116.060 166.410 116.525 214.600 ;
        RECT 116.825 166.410 117.290 214.600 ;
        RECT 117.590 166.410 118.055 214.600 ;
        RECT 118.355 166.410 118.820 214.600 ;
        RECT 119.120 166.410 119.585 214.600 ;
        RECT 119.885 166.410 120.350 214.600 ;
        RECT 120.650 166.410 121.115 214.600 ;
        RECT 121.415 166.410 121.880 214.600 ;
        RECT 122.180 183.335 122.645 214.600 ;
        RECT 122.945 183.335 123.410 214.600 ;
        RECT 123.710 183.335 124.175 214.600 ;
        RECT 124.475 183.335 124.940 214.600 ;
        RECT 125.240 183.335 125.705 214.600 ;
        RECT 126.005 183.335 126.470 214.600 ;
        RECT 122.750 180.430 124.435 183.020 ;
        RECT 122.750 120.605 124.430 180.430 ;
        RECT 124.810 120.600 126.490 183.020 ;
        RECT 126.790 166.410 127.255 214.600 ;
        RECT 127.555 166.410 128.020 214.600 ;
        RECT 128.320 166.410 128.785 214.600 ;
        RECT 129.085 166.410 129.550 214.600 ;
        RECT 129.850 166.410 130.315 214.600 ;
        RECT 130.850 167.070 132.010 214.020 ;
        RECT 132.520 166.410 132.985 214.600 ;
        RECT 133.430 167.070 134.590 214.020 ;
        RECT 134.890 166.410 135.355 214.600 ;
        RECT 135.655 166.410 136.600 214.600 ;
        RECT 136.900 166.410 137.365 214.600 ;
        RECT 137.665 166.410 138.130 214.600 ;
        RECT 138.430 166.410 138.895 214.600 ;
        RECT 139.195 166.410 139.660 214.600 ;
        RECT 151.310 181.805 153.190 182.970 ;
        RECT 59.480 89.570 59.945 108.805 ;
        RECT 60.245 89.570 60.710 108.805 ;
        RECT 61.010 89.570 61.475 108.805 ;
        RECT 61.775 89.570 62.240 108.805 ;
        RECT 62.540 89.570 63.005 108.805 ;
        RECT 63.305 89.570 63.770 108.805 ;
        RECT 64.070 89.570 64.535 108.805 ;
        RECT 64.835 89.570 65.300 108.805 ;
        RECT 65.600 89.570 66.065 108.805 ;
        RECT 66.365 89.570 66.830 108.805 ;
        RECT 67.130 89.570 67.595 108.805 ;
        RECT 67.895 89.570 68.360 108.805 ;
        RECT 68.660 89.570 69.125 108.805 ;
        RECT 69.425 89.570 69.890 108.805 ;
        RECT 70.190 89.570 70.655 108.805 ;
        RECT 70.955 89.570 71.420 108.805 ;
        RECT 71.720 89.570 72.185 108.805 ;
        RECT 72.485 89.570 72.950 108.805 ;
        RECT 73.250 89.570 73.715 108.805 ;
        RECT 74.015 89.570 74.480 108.805 ;
        RECT 74.780 89.570 75.245 108.805 ;
        RECT 75.545 89.570 76.010 108.805 ;
        RECT 76.310 89.570 76.775 108.805 ;
        RECT 77.075 104.600 77.540 108.805 ;
        RECT 77.840 104.600 78.305 108.805 ;
        RECT 78.605 104.600 79.070 108.805 ;
        RECT 77.385 89.435 79.070 103.990 ;
        RECT 79.370 89.570 79.835 108.805 ;
        RECT 80.135 89.570 80.600 108.805 ;
        RECT 80.900 89.570 81.365 108.805 ;
        RECT 81.665 89.570 82.130 108.805 ;
        RECT 82.430 89.570 82.895 108.805 ;
        RECT 83.195 89.570 83.660 108.805 ;
        RECT 83.960 89.570 84.425 108.805 ;
        RECT 84.725 89.570 85.190 108.805 ;
        RECT 85.490 89.570 85.955 108.805 ;
        RECT 86.255 89.570 86.720 108.805 ;
        RECT 87.020 89.570 87.485 108.805 ;
        RECT 87.785 89.570 88.250 108.805 ;
        RECT 88.550 89.570 89.015 108.805 ;
        RECT 89.315 89.570 89.780 108.805 ;
        RECT 90.080 89.570 90.545 108.805 ;
        RECT 90.845 89.570 91.310 108.805 ;
        RECT 91.610 89.570 92.075 108.805 ;
        RECT 92.375 89.570 92.840 108.805 ;
        RECT 93.140 89.570 93.605 108.805 ;
        RECT 93.905 89.570 94.370 108.805 ;
        RECT 94.670 89.570 95.135 108.805 ;
        RECT 95.435 89.570 95.900 108.805 ;
        RECT 96.200 89.570 96.665 108.805 ;
        RECT 55.765 87.280 57.780 87.920 ;
        RECT 8.755 86.905 55.190 86.910 ;
        RECT 59.480 86.905 59.945 89.265 ;
        RECT 6.770 84.010 59.945 86.905 ;
        RECT 59.480 83.635 59.945 84.010 ;
        RECT 60.245 83.635 60.710 89.265 ;
        RECT 61.010 83.635 61.475 89.265 ;
        RECT 61.775 88.060 62.240 89.265 ;
        RECT 59.480 77.135 59.945 83.335 ;
        RECT 60.245 77.135 60.710 83.265 ;
        RECT 61.010 77.135 61.475 83.265 ;
        RECT 8.755 74.485 55.190 74.490 ;
        RECT 59.480 74.485 59.945 76.500 ;
        RECT 6.770 71.590 59.945 74.485 ;
        RECT 59.480 68.605 59.945 71.590 ;
        RECT 60.245 68.605 60.710 76.500 ;
        RECT 61.010 68.605 61.475 76.500 ;
        RECT 62.045 75.480 62.450 87.170 ;
        RECT 62.750 83.635 63.215 89.265 ;
        RECT 63.515 83.635 63.980 89.265 ;
        RECT 64.280 83.635 64.745 89.265 ;
        RECT 65.045 83.635 65.510 89.265 ;
        RECT 65.810 88.065 66.275 89.265 ;
        RECT 62.750 77.135 63.215 83.265 ;
        RECT 63.515 77.135 63.980 83.265 ;
        RECT 64.280 77.135 64.745 83.265 ;
        RECT 65.045 77.135 65.510 83.265 ;
        RECT 61.870 68.605 62.335 75.000 ;
        RECT 62.750 68.605 63.215 76.500 ;
        RECT 63.515 68.605 63.980 76.500 ;
        RECT 64.280 68.605 64.745 76.500 ;
        RECT 65.045 68.605 65.510 76.500 ;
        RECT 65.915 75.480 66.320 87.170 ;
        RECT 66.620 83.635 67.085 89.265 ;
        RECT 67.385 83.635 67.850 89.265 ;
        RECT 68.150 83.635 68.615 89.265 ;
        RECT 68.915 83.635 69.380 89.265 ;
        RECT 69.680 83.635 70.145 89.265 ;
        RECT 70.800 88.065 71.265 89.265 ;
        RECT 66.620 77.135 67.085 83.265 ;
        RECT 67.385 77.135 67.850 83.265 ;
        RECT 68.150 77.135 68.615 83.265 ;
        RECT 68.915 77.135 69.380 83.265 ;
        RECT 69.680 77.135 70.145 83.265 ;
        RECT 70.935 81.840 71.305 87.165 ;
        RECT 71.975 83.635 72.440 89.265 ;
        RECT 72.740 83.635 73.205 89.265 ;
        RECT 73.505 83.635 73.970 89.265 ;
        RECT 74.270 83.635 74.735 89.265 ;
        RECT 75.035 83.635 75.500 89.265 ;
        RECT 75.800 83.635 76.265 89.265 ;
        RECT 76.565 83.635 77.030 89.265 ;
        RECT 70.445 77.135 70.910 81.015 ;
        RECT 71.210 77.135 71.675 81.015 ;
        RECT 71.975 77.135 72.440 83.265 ;
        RECT 72.740 77.135 73.205 83.265 ;
        RECT 73.505 77.135 73.970 83.265 ;
        RECT 74.270 77.135 74.735 83.265 ;
        RECT 75.035 77.135 75.500 83.265 ;
        RECT 65.810 68.605 66.275 75.000 ;
        RECT 66.620 68.605 67.085 76.500 ;
        RECT 67.385 68.605 67.850 76.500 ;
        RECT 68.150 68.605 68.615 76.500 ;
        RECT 68.915 68.605 69.380 76.500 ;
        RECT 69.680 68.605 70.145 76.500 ;
        RECT 70.445 68.605 70.910 76.500 ;
        RECT 71.210 68.605 71.675 76.500 ;
        RECT 71.975 68.605 72.440 76.500 ;
        RECT 72.740 68.605 73.205 76.500 ;
        RECT 73.505 68.605 73.970 76.500 ;
        RECT 74.270 68.605 74.735 76.500 ;
        RECT 75.035 68.605 75.500 76.500 ;
        RECT 77.385 58.520 79.065 89.435 ;
        RECT 96.965 89.370 97.430 108.805 ;
        RECT 97.730 89.370 98.195 108.805 ;
        RECT 98.495 89.370 98.960 108.805 ;
        RECT 99.260 89.370 100.085 108.805 ;
        RECT 79.365 83.635 79.830 89.265 ;
        RECT 80.130 83.635 80.595 89.265 ;
        RECT 80.895 83.635 81.360 89.265 ;
        RECT 81.660 83.635 82.125 89.265 ;
        RECT 82.440 88.065 82.905 89.265 ;
        RECT 82.540 86.030 82.910 87.165 ;
        RECT 82.535 85.660 82.910 86.030 ;
        RECT 82.540 81.840 82.910 85.660 ;
        RECT 83.210 83.635 83.675 89.265 ;
        RECT 83.975 83.635 84.440 89.265 ;
        RECT 84.740 83.635 85.205 89.265 ;
        RECT 85.505 83.635 85.970 89.265 ;
        RECT 86.270 83.635 86.735 89.265 ;
        RECT 87.035 83.635 87.500 89.265 ;
        RECT 87.800 83.635 88.265 89.265 ;
        RECT 88.565 83.635 89.030 89.265 ;
        RECT 89.330 83.635 89.795 89.265 ;
        RECT 90.095 83.635 90.560 89.265 ;
        RECT 90.860 83.635 91.325 89.265 ;
        RECT 91.625 83.635 92.090 89.265 ;
        RECT 92.390 83.635 92.855 89.265 ;
        RECT 93.155 83.635 93.620 89.265 ;
        RECT 93.920 83.635 94.385 89.265 ;
        RECT 94.685 83.635 95.150 89.265 ;
        RECT 95.450 83.635 95.915 89.265 ;
        RECT 96.215 83.635 96.680 89.265 ;
        RECT 99.620 60.615 100.085 89.370 ;
        RECT 100.385 60.615 100.850 108.805 ;
        RECT 101.630 61.275 102.790 108.225 ;
        RECT 103.445 60.615 103.910 108.805 ;
        RECT 104.210 61.275 105.440 108.225 ;
        RECT 105.740 60.615 106.205 108.805 ;
        RECT 106.505 60.615 106.970 108.805 ;
        RECT 107.270 60.615 107.735 108.805 ;
        RECT 108.035 60.615 108.500 108.805 ;
        RECT 108.800 60.615 109.265 108.805 ;
        RECT 109.565 77.555 110.040 108.805 ;
        RECT 110.340 77.550 110.815 108.805 ;
        RECT 111.115 77.550 111.590 108.805 ;
        RECT 111.890 77.550 112.365 108.805 ;
        RECT 112.670 77.550 113.250 108.805 ;
        RECT 58.715 44.795 74.575 57.195 ;
        RECT 75.775 44.795 91.635 57.195 ;
        RECT 92.835 44.795 108.695 57.195 ;
        RECT 58.715 31.195 74.575 43.595 ;
        RECT 75.775 31.195 91.635 43.595 ;
        RECT 92.835 31.195 108.695 43.595 ;
        RECT 58.715 17.595 74.575 29.995 ;
        RECT 75.775 17.595 91.635 29.995 ;
        RECT 92.835 17.595 108.695 29.995 ;
        RECT 109.730 14.805 111.410 77.225 ;
        RECT 111.710 14.805 113.390 77.225 ;
        RECT 113.690 60.615 114.155 108.805 ;
        RECT 114.455 60.615 114.920 108.805 ;
        RECT 115.220 60.615 115.685 108.805 ;
        RECT 115.985 60.615 116.450 108.805 ;
        RECT 116.750 60.615 117.215 108.805 ;
        RECT 117.515 60.615 117.980 108.805 ;
        RECT 118.280 60.615 118.745 108.805 ;
        RECT 119.045 60.615 119.510 108.805 ;
        RECT 119.810 60.615 120.275 108.805 ;
        RECT 120.575 60.615 121.040 108.805 ;
        RECT 121.340 77.540 121.805 108.805 ;
        RECT 122.105 77.540 122.570 108.805 ;
        RECT 122.870 77.540 123.335 108.805 ;
        RECT 123.635 77.540 124.100 108.805 ;
        RECT 124.400 77.540 124.865 108.805 ;
        RECT 125.165 77.540 125.630 108.805 ;
        RECT 121.910 74.635 123.595 77.225 ;
        RECT 121.910 14.810 123.590 74.635 ;
        RECT 123.970 14.805 125.650 77.225 ;
        RECT 125.950 60.615 126.415 108.805 ;
        RECT 126.715 60.615 127.180 108.805 ;
        RECT 127.480 60.615 127.945 108.805 ;
        RECT 128.245 60.615 128.710 108.805 ;
        RECT 129.010 60.615 129.475 108.805 ;
        RECT 130.010 61.275 131.170 108.225 ;
        RECT 131.680 60.615 132.145 108.805 ;
        RECT 132.590 61.275 133.750 108.225 ;
        RECT 134.050 60.615 134.515 108.805 ;
        RECT 134.815 60.615 135.760 108.805 ;
        RECT 136.060 60.615 136.525 108.805 ;
        RECT 136.825 60.615 137.290 108.805 ;
        RECT 137.590 60.615 138.055 108.805 ;
        RECT 138.355 60.615 138.820 108.805 ;
        RECT 146.595 76.025 148.470 77.170 ;
      LAYER met4 ;
        RECT 68.510 224.210 70.435 224.760 ;
        RECT 8.770 222.285 70.435 224.210 ;
        RECT 46.205 218.180 141.725 220.105 ;
        RECT 50.995 7.790 53.005 214.950 ;
        RECT 55.775 12.630 57.775 214.950 ;
        RECT 135.650 189.520 141.725 194.975 ;
        RECT 74.895 164.315 109.960 165.095 ;
        RECT 66.495 162.595 67.015 163.590 ;
        RECT 59.950 150.985 73.560 162.595 ;
        RECT 66.495 148.995 67.015 150.985 ;
        RECT 59.950 137.385 73.560 148.995 ;
        RECT 66.495 135.395 67.015 137.385 ;
        RECT 59.950 123.785 73.560 135.395 ;
        RECT 66.495 122.410 67.200 123.785 ;
        RECT 74.895 122.790 75.840 164.315 ;
        RECT 83.555 162.595 84.075 163.590 ;
        RECT 77.010 150.985 90.620 162.595 ;
        RECT 83.555 148.995 84.075 150.985 ;
        RECT 77.010 137.385 90.620 148.995 ;
        RECT 83.555 135.395 84.075 137.385 ;
        RECT 77.010 123.785 90.620 135.395 ;
        RECT 83.470 122.410 84.175 123.785 ;
        RECT 91.955 122.790 92.900 164.315 ;
        RECT 100.615 162.595 101.135 163.590 ;
        RECT 94.070 150.985 107.680 162.595 ;
        RECT 100.615 148.995 101.135 150.985 ;
        RECT 94.070 137.385 107.680 148.995 ;
        RECT 100.615 135.395 101.135 137.385 ;
        RECT 94.070 123.785 107.680 135.395 ;
        RECT 100.370 122.410 101.405 123.785 ;
        RECT 109.015 122.790 109.960 164.315 ;
        RECT 66.435 120.600 126.490 122.410 ;
        RECT 134.815 83.720 141.725 89.175 ;
        RECT 74.055 58.520 109.120 59.300 ;
        RECT 65.655 56.800 66.175 57.795 ;
        RECT 59.110 45.190 72.720 56.800 ;
        RECT 65.655 43.200 66.175 45.190 ;
        RECT 59.110 31.590 72.720 43.200 ;
        RECT 65.655 29.600 66.175 31.590 ;
        RECT 59.110 17.990 72.720 29.600 ;
        RECT 65.655 16.615 66.360 17.990 ;
        RECT 74.055 16.995 75.000 58.520 ;
        RECT 82.715 56.800 83.235 57.795 ;
        RECT 76.170 45.190 89.780 56.800 ;
        RECT 82.715 43.200 83.235 45.190 ;
        RECT 76.170 31.590 89.780 43.200 ;
        RECT 82.715 29.600 83.235 31.590 ;
        RECT 76.170 17.990 89.780 29.600 ;
        RECT 82.630 16.615 83.335 17.990 ;
        RECT 91.115 16.995 92.060 58.520 ;
        RECT 99.775 56.800 100.295 57.795 ;
        RECT 93.230 45.190 106.840 56.800 ;
        RECT 99.775 43.200 100.295 45.190 ;
        RECT 93.230 31.590 106.840 43.200 ;
        RECT 99.775 29.600 100.295 31.590 ;
        RECT 93.230 17.990 106.840 29.600 ;
        RECT 99.530 16.615 100.565 17.990 ;
        RECT 108.175 16.995 109.120 58.520 ;
        RECT 65.595 14.805 125.650 16.615 ;
        RECT 55.775 11.815 57.780 12.630 ;
        RECT 55.775 11.810 91.580 11.815 ;
        RECT 55.775 9.815 95.175 11.810 ;
        RECT 70.380 7.795 75.985 7.800 ;
        RECT 54.605 7.790 75.985 7.795 ;
        RECT 50.995 5.790 75.985 7.790 ;
        RECT 73.965 1.000 75.985 5.790 ;
        RECT 93.175 1.570 95.175 9.815 ;
        RECT 73.965 0.995 74.530 1.000 ;
        RECT 75.430 0.995 75.985 1.000 ;
        RECT 93.180 1.000 95.175 1.570 ;
        RECT 93.180 0.995 93.850 1.000 ;
        RECT 94.750 0.995 95.175 1.000 ;
        RECT 112.690 8.930 141.725 10.910 ;
        RECT 112.690 8.910 143.725 8.930 ;
        RECT 112.690 1.000 114.690 8.910 ;
        RECT 146.495 5.725 148.495 214.950 ;
        RECT 132.100 3.725 148.495 5.725 ;
        RECT 132.105 2.385 134.105 3.725 ;
        RECT 132.100 1.800 134.105 2.385 ;
        RECT 132.105 1.620 134.105 1.800 ;
        RECT 112.690 0.990 113.170 1.000 ;
        RECT 114.070 0.990 114.690 1.000 ;
        RECT 132.110 1.000 134.105 1.620 ;
        RECT 132.110 0.995 132.490 1.000 ;
        RECT 133.390 0.995 134.105 1.000 ;
        RECT 151.265 1.000 153.265 214.950 ;
        RECT 151.265 0.995 151.810 1.000 ;
        RECT 152.710 0.995 153.265 1.000 ;
  END
END tt_um_ctw_ldo
END LIBRARY
